VERSION 5.8 ;
BUSBITCHARS "[]" ;
DIVIDERCHAR "/" ;
UNITS
    DATABASE MICRONS 1000 ;
END UNITS

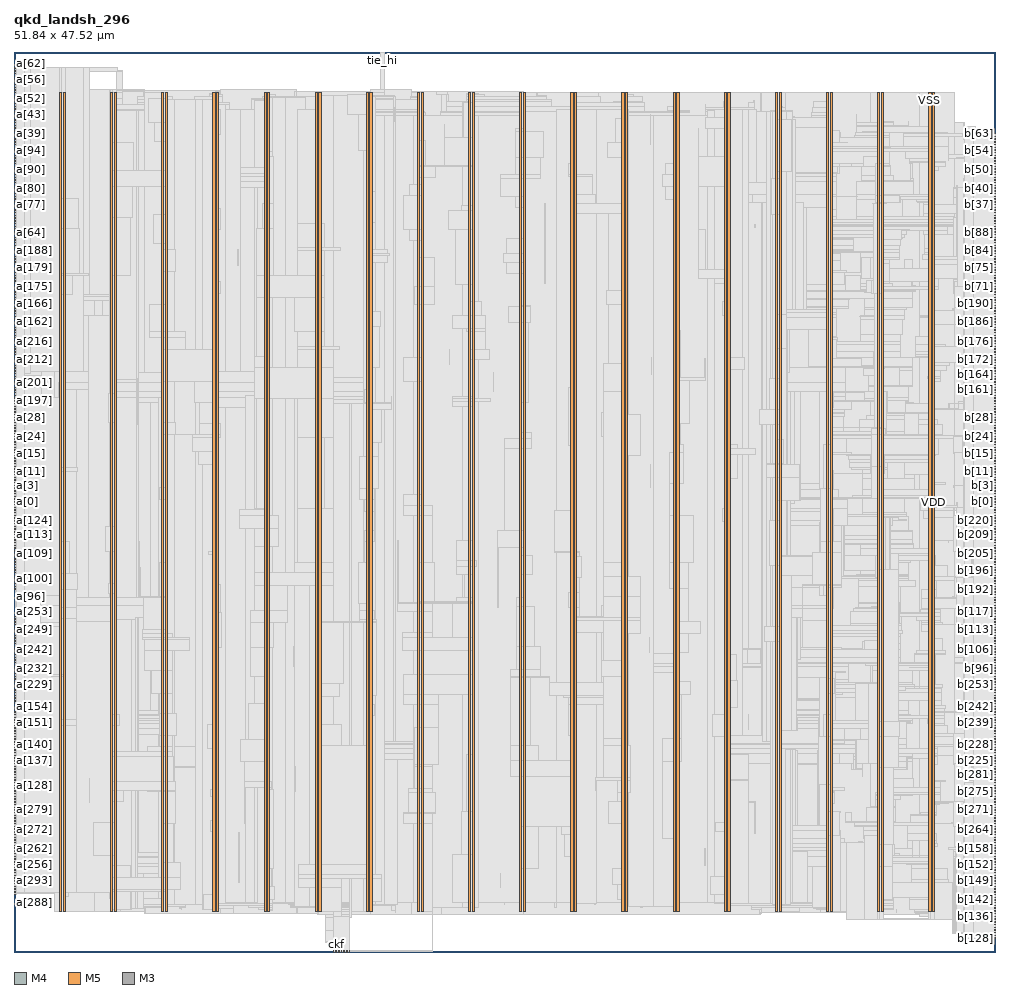
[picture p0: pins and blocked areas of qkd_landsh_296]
MACRO qkd_landsh_296
  FOREIGN qkd_landsh_296 0 0 ;
  CLASS BLOCK ;
  SIZE 51.84 BY 47.52 ;
  PIN a[0]
    DIRECTION INPUT ;
    USE SIGNAL ;
    PORT
      LAYER M4 ;
        RECT  0 23.76 0.084 23.784 ;
    END
  END a[0]
  PIN a[100]
    DIRECTION INPUT ;
    USE SIGNAL ;
    PORT
      LAYER M4 ;
        RECT  0 19.728 0.084 19.752 ;
    END
  END a[100]
  PIN a[101]
    DIRECTION INPUT ;
    USE SIGNAL ;
    PORT
      LAYER M4 ;
        RECT  0 19.872 0.084 19.896 ;
    END
  END a[101]
  PIN a[102]
    DIRECTION INPUT ;
    USE SIGNAL ;
    PORT
      LAYER M4 ;
        RECT  0 20.016 0.084 20.04 ;
    END
  END a[102]
  PIN a[103]
    DIRECTION INPUT ;
    USE SIGNAL ;
    PORT
      LAYER M4 ;
        RECT  0 20.16 0.084 20.184 ;
    END
  END a[103]
  PIN a[104]
    DIRECTION INPUT ;
    USE SIGNAL ;
    PORT
      LAYER M4 ;
        RECT  0 20.304 0.084 20.328 ;
    END
  END a[104]
  PIN a[105]
    DIRECTION INPUT ;
    USE SIGNAL ;
    PORT
      LAYER M4 ;
        RECT  0 20.448 0.084 20.472 ;
    END
  END a[105]
  PIN a[106]
    DIRECTION INPUT ;
    USE SIGNAL ;
    PORT
      LAYER M4 ;
        RECT  0 20.592 0.084 20.616 ;
    END
  END a[106]
  PIN a[107]
    DIRECTION INPUT ;
    USE SIGNAL ;
    PORT
      LAYER M4 ;
        RECT  0 20.736 0.084 20.76 ;
    END
  END a[107]
  PIN a[108]
    DIRECTION INPUT ;
    USE SIGNAL ;
    PORT
      LAYER M4 ;
        RECT  0 20.88 0.084 20.904 ;
    END
  END a[108]
  PIN a[109]
    DIRECTION INPUT ;
    USE SIGNAL ;
    PORT
      LAYER M4 ;
        RECT  0 21.024 0.084 21.048 ;
    END
  END a[109]
  PIN a[10]
    DIRECTION INPUT ;
    USE SIGNAL ;
    PORT
      LAYER M4 ;
        RECT  0 25.2 0.084 25.224 ;
    END
  END a[10]
  PIN a[110]
    DIRECTION INPUT ;
    USE SIGNAL ;
    PORT
      LAYER M4 ;
        RECT  0 21.168 0.084 21.192 ;
    END
  END a[110]
  PIN a[111]
    DIRECTION INPUT ;
    USE SIGNAL ;
    PORT
      LAYER M4 ;
        RECT  0 21.312 0.084 21.336 ;
    END
  END a[111]
  PIN a[112]
    DIRECTION INPUT ;
    USE SIGNAL ;
    PORT
      LAYER M4 ;
        RECT  0 21.456 0.084 21.48 ;
    END
  END a[112]
  PIN a[113]
    DIRECTION INPUT ;
    USE SIGNAL ;
    PORT
      LAYER M4 ;
        RECT  0 21.6 0.084 21.624 ;
    END
  END a[113]
  PIN a[114]
    DIRECTION INPUT ;
    USE SIGNAL ;
    PORT
      LAYER M4 ;
        RECT  0 21.744 0.084 21.768 ;
    END
  END a[114]
  PIN a[115]
    DIRECTION INPUT ;
    USE SIGNAL ;
    PORT
      LAYER M4 ;
        RECT  0 21.888 0.084 21.912 ;
    END
  END a[115]
  PIN a[116]
    DIRECTION INPUT ;
    USE SIGNAL ;
    PORT
      LAYER M4 ;
        RECT  0 22.032 0.084 22.056 ;
    END
  END a[116]
  PIN a[117]
    DIRECTION INPUT ;
    USE SIGNAL ;
    PORT
      LAYER M4 ;
        RECT  0 22.176 0.084 22.2 ;
    END
  END a[117]
  PIN a[118]
    DIRECTION INPUT ;
    USE SIGNAL ;
    PORT
      LAYER M4 ;
        RECT  0 22.32 0.084 22.344 ;
    END
  END a[118]
  PIN a[119]
    DIRECTION INPUT ;
    USE SIGNAL ;
    PORT
      LAYER M4 ;
        RECT  0 22.464 0.084 22.488 ;
    END
  END a[119]
  PIN a[11]
    DIRECTION INPUT ;
    USE SIGNAL ;
    PORT
      LAYER M4 ;
        RECT  0 25.344 0.084 25.368 ;
    END
  END a[11]
  PIN a[120]
    DIRECTION INPUT ;
    USE SIGNAL ;
    PORT
      LAYER M4 ;
        RECT  0 22.608 0.084 22.632 ;
    END
  END a[120]
  PIN a[121]
    DIRECTION INPUT ;
    USE SIGNAL ;
    PORT
      LAYER M4 ;
        RECT  0 22.752 0.084 22.776 ;
    END
  END a[121]
  PIN a[122]
    DIRECTION INPUT ;
    USE SIGNAL ;
    PORT
      LAYER M4 ;
        RECT  0 22.896 0.084 22.92 ;
    END
  END a[122]
  PIN a[123]
    DIRECTION INPUT ;
    USE SIGNAL ;
    PORT
      LAYER M4 ;
        RECT  0 23.04 0.084 23.064 ;
    END
  END a[123]
  PIN a[124]
    DIRECTION INPUT ;
    USE SIGNAL ;
    PORT
      LAYER M4 ;
        RECT  0 23.184 0.084 23.208 ;
    END
  END a[124]
  PIN a[125]
    DIRECTION INPUT ;
    USE SIGNAL ;
    PORT
      LAYER M4 ;
        RECT  0 23.328 0.084 23.352 ;
    END
  END a[125]
  PIN a[126]
    DIRECTION INPUT ;
    USE SIGNAL ;
    PORT
      LAYER M4 ;
        RECT  0 23.472 0.084 23.496 ;
    END
  END a[126]
  PIN a[127]
    DIRECTION INPUT ;
    USE SIGNAL ;
    PORT
      LAYER M4 ;
        RECT  0 23.616 0.084 23.64 ;
    END
  END a[127]
  PIN a[128]
    DIRECTION INPUT ;
    USE SIGNAL ;
    PORT
      LAYER M4 ;
        RECT  0 8.784 0.084 8.808 ;
    END
  END a[128]
  PIN a[129]
    DIRECTION INPUT ;
    USE SIGNAL ;
    PORT
      LAYER M4 ;
        RECT  0 8.928 0.084 8.952 ;
    END
  END a[129]
  PIN a[12]
    DIRECTION INPUT ;
    USE SIGNAL ;
    PORT
      LAYER M4 ;
        RECT  0 25.488 0.084 25.512 ;
    END
  END a[12]
  PIN a[130]
    DIRECTION INPUT ;
    USE SIGNAL ;
    PORT
      LAYER M4 ;
        RECT  0 9.072 0.084 9.096 ;
    END
  END a[130]
  PIN a[131]
    DIRECTION INPUT ;
    USE SIGNAL ;
    PORT
      LAYER M4 ;
        RECT  0 9.216 0.084 9.24 ;
    END
  END a[131]
  PIN a[132]
    DIRECTION INPUT ;
    USE SIGNAL ;
    PORT
      LAYER M4 ;
        RECT  0 9.36 0.084 9.384 ;
    END
  END a[132]
  PIN a[133]
    DIRECTION INPUT ;
    USE SIGNAL ;
    PORT
      LAYER M4 ;
        RECT  0 9.504 0.084 9.528 ;
    END
  END a[133]
  PIN a[134]
    DIRECTION INPUT ;
    USE SIGNAL ;
    PORT
      LAYER M4 ;
        RECT  0 9.648 0.084 9.672 ;
    END
  END a[134]
  PIN a[135]
    DIRECTION INPUT ;
    USE SIGNAL ;
    PORT
      LAYER M4 ;
        RECT  0 9.792 0.084 9.816 ;
    END
  END a[135]
  PIN a[136]
    DIRECTION INPUT ;
    USE SIGNAL ;
    PORT
      LAYER M4 ;
        RECT  0 9.936 0.084 9.96 ;
    END
  END a[136]
  PIN a[137]
    DIRECTION INPUT ;
    USE SIGNAL ;
    PORT
      LAYER M4 ;
        RECT  0 10.08 0.084 10.104 ;
    END
  END a[137]
  PIN a[138]
    DIRECTION INPUT ;
    USE SIGNAL ;
    PORT
      LAYER M4 ;
        RECT  0 10.224 0.084 10.248 ;
    END
  END a[138]
  PIN a[139]
    DIRECTION INPUT ;
    USE SIGNAL ;
    PORT
      LAYER M4 ;
        RECT  0 10.368 0.084 10.392 ;
    END
  END a[139]
  PIN a[13]
    DIRECTION INPUT ;
    USE SIGNAL ;
    PORT
      LAYER M4 ;
        RECT  0 25.632 0.084 25.656 ;
    END
  END a[13]
  PIN a[140]
    DIRECTION INPUT ;
    USE SIGNAL ;
    PORT
      LAYER M4 ;
        RECT  0 10.512 0.084 10.536 ;
    END
  END a[140]
  PIN a[141]
    DIRECTION INPUT ;
    USE SIGNAL ;
    PORT
      LAYER M4 ;
        RECT  0 10.656 0.084 10.68 ;
    END
  END a[141]
  PIN a[142]
    DIRECTION INPUT ;
    USE SIGNAL ;
    PORT
      LAYER M4 ;
        RECT  0 10.8 0.084 10.824 ;
    END
  END a[142]
  PIN a[143]
    DIRECTION INPUT ;
    USE SIGNAL ;
    PORT
      LAYER M4 ;
        RECT  0 10.944 0.084 10.968 ;
    END
  END a[143]
  PIN a[144]
    DIRECTION INPUT ;
    USE SIGNAL ;
    PORT
      LAYER M4 ;
        RECT  0 11.088 0.084 11.112 ;
    END
  END a[144]
  PIN a[145]
    DIRECTION INPUT ;
    USE SIGNAL ;
    PORT
      LAYER M4 ;
        RECT  0 11.232 0.084 11.256 ;
    END
  END a[145]
  PIN a[146]
    DIRECTION INPUT ;
    USE SIGNAL ;
    PORT
      LAYER M4 ;
        RECT  0 11.376 0.084 11.4 ;
    END
  END a[146]
  PIN a[147]
    DIRECTION INPUT ;
    USE SIGNAL ;
    PORT
      LAYER M4 ;
        RECT  0 11.52 0.084 11.544 ;
    END
  END a[147]
  PIN a[148]
    DIRECTION INPUT ;
    USE SIGNAL ;
    PORT
      LAYER M4 ;
        RECT  0 11.664 0.084 11.688 ;
    END
  END a[148]
  PIN a[149]
    DIRECTION INPUT ;
    USE SIGNAL ;
    PORT
      LAYER M4 ;
        RECT  0 11.808 0.084 11.832 ;
    END
  END a[149]
  PIN a[14]
    DIRECTION INPUT ;
    USE SIGNAL ;
    PORT
      LAYER M4 ;
        RECT  0 25.776 0.084 25.8 ;
    END
  END a[14]
  PIN a[150]
    DIRECTION INPUT ;
    USE SIGNAL ;
    PORT
      LAYER M4 ;
        RECT  0 11.952 0.084 11.976 ;
    END
  END a[150]
  PIN a[151]
    DIRECTION INPUT ;
    USE SIGNAL ;
    PORT
      LAYER M4 ;
        RECT  0 12.096 0.084 12.12 ;
    END
  END a[151]
  PIN a[152]
    DIRECTION INPUT ;
    USE SIGNAL ;
    PORT
      LAYER M4 ;
        RECT  0 12.24 0.084 12.264 ;
    END
  END a[152]
  PIN a[153]
    DIRECTION INPUT ;
    USE SIGNAL ;
    PORT
      LAYER M4 ;
        RECT  0 12.384 0.084 12.408 ;
    END
  END a[153]
  PIN a[154]
    DIRECTION INPUT ;
    USE SIGNAL ;
    PORT
      LAYER M4 ;
        RECT  0 12.528 0.084 12.552 ;
    END
  END a[154]
  PIN a[155]
    DIRECTION INPUT ;
    USE SIGNAL ;
    PORT
      LAYER M4 ;
        RECT  0 12.672 0.084 12.696 ;
    END
  END a[155]
  PIN a[156]
    DIRECTION INPUT ;
    USE SIGNAL ;
    PORT
      LAYER M4 ;
        RECT  0 12.816 0.084 12.84 ;
    END
  END a[156]
  PIN a[157]
    DIRECTION INPUT ;
    USE SIGNAL ;
    PORT
      LAYER M4 ;
        RECT  0 12.96 0.084 12.984 ;
    END
  END a[157]
  PIN a[158]
    DIRECTION INPUT ;
    USE SIGNAL ;
    PORT
      LAYER M4 ;
        RECT  0 13.104 0.084 13.128 ;
    END
  END a[158]
  PIN a[159]
    DIRECTION INPUT ;
    USE SIGNAL ;
    PORT
      LAYER M4 ;
        RECT  0 13.248 0.084 13.272 ;
    END
  END a[159]
  PIN a[15]
    DIRECTION INPUT ;
    USE SIGNAL ;
    PORT
      LAYER M4 ;
        RECT  0 25.92 0.084 25.944 ;
    END
  END a[15]
  PIN a[160]
    DIRECTION INPUT ;
    USE SIGNAL ;
    PORT
      LAYER M4 ;
        RECT  0 32.976 0.084 33 ;
    END
  END a[160]
  PIN a[161]
    DIRECTION INPUT ;
    USE SIGNAL ;
    PORT
      LAYER M4 ;
        RECT  0 33.12 0.084 33.144 ;
    END
  END a[161]
  PIN a[162]
    DIRECTION INPUT ;
    USE SIGNAL ;
    PORT
      LAYER M4 ;
        RECT  0 33.264 0.084 33.288 ;
    END
  END a[162]
  PIN a[163]
    DIRECTION INPUT ;
    USE SIGNAL ;
    PORT
      LAYER M4 ;
        RECT  0 33.408 0.084 33.432 ;
    END
  END a[163]
  PIN a[164]
    DIRECTION INPUT ;
    USE SIGNAL ;
    PORT
      LAYER M4 ;
        RECT  0 33.552 0.084 33.576 ;
    END
  END a[164]
  PIN a[165]
    DIRECTION INPUT ;
    USE SIGNAL ;
    PORT
      LAYER M4 ;
        RECT  0 33.696 0.084 33.72 ;
    END
  END a[165]
  PIN a[166]
    DIRECTION INPUT ;
    USE SIGNAL ;
    PORT
      LAYER M4 ;
        RECT  0 33.84 0.084 33.864 ;
    END
  END a[166]
  PIN a[167]
    DIRECTION INPUT ;
    USE SIGNAL ;
    PORT
      LAYER M4 ;
        RECT  0 33.984 0.084 34.008 ;
    END
  END a[167]
  PIN a[168]
    DIRECTION INPUT ;
    USE SIGNAL ;
    PORT
      LAYER M4 ;
        RECT  0 34.128 0.084 34.152 ;
    END
  END a[168]
  PIN a[169]
    DIRECTION INPUT ;
    USE SIGNAL ;
    PORT
      LAYER M4 ;
        RECT  0 34.272 0.084 34.296 ;
    END
  END a[169]
  PIN a[16]
    DIRECTION INPUT ;
    USE SIGNAL ;
    PORT
      LAYER M4 ;
        RECT  0 26.064 0.084 26.088 ;
    END
  END a[16]
  PIN a[170]
    DIRECTION INPUT ;
    USE SIGNAL ;
    PORT
      LAYER M4 ;
        RECT  0 34.416 0.084 34.44 ;
    END
  END a[170]
  PIN a[171]
    DIRECTION INPUT ;
    USE SIGNAL ;
    PORT
      LAYER M4 ;
        RECT  0 34.56 0.084 34.584 ;
    END
  END a[171]
  PIN a[172]
    DIRECTION INPUT ;
    USE SIGNAL ;
    PORT
      LAYER M4 ;
        RECT  0 34.704 0.084 34.728 ;
    END
  END a[172]
  PIN a[173]
    DIRECTION INPUT ;
    USE SIGNAL ;
    PORT
      LAYER M4 ;
        RECT  0 34.848 0.084 34.872 ;
    END
  END a[173]
  PIN a[174]
    DIRECTION INPUT ;
    USE SIGNAL ;
    PORT
      LAYER M4 ;
        RECT  0 34.992 0.084 35.016 ;
    END
  END a[174]
  PIN a[175]
    DIRECTION INPUT ;
    USE SIGNAL ;
    PORT
      LAYER M4 ;
        RECT  0 35.136 0.084 35.16 ;
    END
  END a[175]
  PIN a[176]
    DIRECTION INPUT ;
    USE SIGNAL ;
    PORT
      LAYER M4 ;
        RECT  0 35.28 0.084 35.304 ;
    END
  END a[176]
  PIN a[177]
    DIRECTION INPUT ;
    USE SIGNAL ;
    PORT
      LAYER M4 ;
        RECT  0 35.424 0.084 35.448 ;
    END
  END a[177]
  PIN a[178]
    DIRECTION INPUT ;
    USE SIGNAL ;
    PORT
      LAYER M4 ;
        RECT  0 35.568 0.084 35.592 ;
    END
  END a[178]
  PIN a[179]
    DIRECTION INPUT ;
    USE SIGNAL ;
    PORT
      LAYER M4 ;
        RECT  0 35.712 0.084 35.736 ;
    END
  END a[179]
  PIN a[17]
    DIRECTION INPUT ;
    USE SIGNAL ;
    PORT
      LAYER M4 ;
        RECT  0 26.208 0.084 26.232 ;
    END
  END a[17]
  PIN a[180]
    DIRECTION INPUT ;
    USE SIGNAL ;
    PORT
      LAYER M4 ;
        RECT  0 35.856 0.084 35.88 ;
    END
  END a[180]
  PIN a[181]
    DIRECTION INPUT ;
    USE SIGNAL ;
    PORT
      LAYER M4 ;
        RECT  0 36 0.084 36.024 ;
    END
  END a[181]
  PIN a[182]
    DIRECTION INPUT ;
    USE SIGNAL ;
    PORT
      LAYER M4 ;
        RECT  0 36.144 0.084 36.168 ;
    END
  END a[182]
  PIN a[183]
    DIRECTION INPUT ;
    USE SIGNAL ;
    PORT
      LAYER M4 ;
        RECT  0 36.288 0.084 36.312 ;
    END
  END a[183]
  PIN a[184]
    DIRECTION INPUT ;
    USE SIGNAL ;
    PORT
      LAYER M4 ;
        RECT  0 36.432 0.084 36.456 ;
    END
  END a[184]
  PIN a[185]
    DIRECTION INPUT ;
    USE SIGNAL ;
    PORT
      LAYER M4 ;
        RECT  0 36.576 0.084 36.6 ;
    END
  END a[185]
  PIN a[186]
    DIRECTION INPUT ;
    USE SIGNAL ;
    PORT
      LAYER M4 ;
        RECT  0 36.72 0.084 36.744 ;
    END
  END a[186]
  PIN a[187]
    DIRECTION INPUT ;
    USE SIGNAL ;
    PORT
      LAYER M4 ;
        RECT  0 36.864 0.084 36.888 ;
    END
  END a[187]
  PIN a[188]
    DIRECTION INPUT ;
    USE SIGNAL ;
    PORT
      LAYER M4 ;
        RECT  0 37.008 0.084 37.032 ;
    END
  END a[188]
  PIN a[189]
    DIRECTION INPUT ;
    USE SIGNAL ;
    PORT
      LAYER M4 ;
        RECT  0 37.152 0.084 37.176 ;
    END
  END a[189]
  PIN a[18]
    DIRECTION INPUT ;
    USE SIGNAL ;
    PORT
      LAYER M4 ;
        RECT  0 26.352 0.084 26.376 ;
    END
  END a[18]
  PIN a[190]
    DIRECTION INPUT ;
    USE SIGNAL ;
    PORT
      LAYER M4 ;
        RECT  0 37.296 0.084 37.32 ;
    END
  END a[190]
  PIN a[191]
    DIRECTION INPUT ;
    USE SIGNAL ;
    PORT
      LAYER M4 ;
        RECT  0 37.44 0.084 37.464 ;
    END
  END a[191]
  PIN a[192]
    DIRECTION INPUT ;
    USE SIGNAL ;
    PORT
      LAYER M4 ;
        RECT  0 28.368 0.084 28.392 ;
    END
  END a[192]
  PIN a[193]
    DIRECTION INPUT ;
    USE SIGNAL ;
    PORT
      LAYER M4 ;
        RECT  0 28.512 0.084 28.536 ;
    END
  END a[193]
  PIN a[194]
    DIRECTION INPUT ;
    USE SIGNAL ;
    PORT
      LAYER M4 ;
        RECT  0 28.656 0.084 28.68 ;
    END
  END a[194]
  PIN a[195]
    DIRECTION INPUT ;
    USE SIGNAL ;
    PORT
      LAYER M4 ;
        RECT  0 28.8 0.084 28.824 ;
    END
  END a[195]
  PIN a[196]
    DIRECTION INPUT ;
    USE SIGNAL ;
    PORT
      LAYER M4 ;
        RECT  0 28.944 0.084 28.968 ;
    END
  END a[196]
  PIN a[197]
    DIRECTION INPUT ;
    USE SIGNAL ;
    PORT
      LAYER M4 ;
        RECT  0 29.088 0.084 29.112 ;
    END
  END a[197]
  PIN a[198]
    DIRECTION INPUT ;
    USE SIGNAL ;
    PORT
      LAYER M4 ;
        RECT  0 29.232 0.084 29.256 ;
    END
  END a[198]
  PIN a[199]
    DIRECTION INPUT ;
    USE SIGNAL ;
    PORT
      LAYER M4 ;
        RECT  0 29.376 0.084 29.4 ;
    END
  END a[199]
  PIN a[19]
    DIRECTION INPUT ;
    USE SIGNAL ;
    PORT
      LAYER M4 ;
        RECT  0 26.496 0.084 26.52 ;
    END
  END a[19]
  PIN a[1]
    DIRECTION INPUT ;
    USE SIGNAL ;
    PORT
      LAYER M4 ;
        RECT  0 23.904 0.084 23.928 ;
    END
  END a[1]
  PIN a[200]
    DIRECTION INPUT ;
    USE SIGNAL ;
    PORT
      LAYER M4 ;
        RECT  0 29.52 0.084 29.544 ;
    END
  END a[200]
  PIN a[201]
    DIRECTION INPUT ;
    USE SIGNAL ;
    PORT
      LAYER M4 ;
        RECT  0 29.664 0.084 29.688 ;
    END
  END a[201]
  PIN a[202]
    DIRECTION INPUT ;
    USE SIGNAL ;
    PORT
      LAYER M4 ;
        RECT  0 29.808 0.084 29.832 ;
    END
  END a[202]
  PIN a[203]
    DIRECTION INPUT ;
    USE SIGNAL ;
    PORT
      LAYER M4 ;
        RECT  0 29.952 0.084 29.976 ;
    END
  END a[203]
  PIN a[204]
    DIRECTION INPUT ;
    USE SIGNAL ;
    PORT
      LAYER M4 ;
        RECT  0 30.096 0.084 30.12 ;
    END
  END a[204]
  PIN a[205]
    DIRECTION INPUT ;
    USE SIGNAL ;
    PORT
      LAYER M4 ;
        RECT  0 30.24 0.084 30.264 ;
    END
  END a[205]
  PIN a[206]
    DIRECTION INPUT ;
    USE SIGNAL ;
    PORT
      LAYER M4 ;
        RECT  0 30.384 0.084 30.408 ;
    END
  END a[206]
  PIN a[207]
    DIRECTION INPUT ;
    USE SIGNAL ;
    PORT
      LAYER M4 ;
        RECT  0 30.528 0.084 30.552 ;
    END
  END a[207]
  PIN a[208]
    DIRECTION INPUT ;
    USE SIGNAL ;
    PORT
      LAYER M4 ;
        RECT  0 30.672 0.084 30.696 ;
    END
  END a[208]
  PIN a[209]
    DIRECTION INPUT ;
    USE SIGNAL ;
    PORT
      LAYER M4 ;
        RECT  0 30.816 0.084 30.84 ;
    END
  END a[209]
  PIN a[20]
    DIRECTION INPUT ;
    USE SIGNAL ;
    PORT
      LAYER M4 ;
        RECT  0 26.64 0.084 26.664 ;
    END
  END a[20]
  PIN a[210]
    DIRECTION INPUT ;
    USE SIGNAL ;
    PORT
      LAYER M4 ;
        RECT  0 30.96 0.084 30.984 ;
    END
  END a[210]
  PIN a[211]
    DIRECTION INPUT ;
    USE SIGNAL ;
    PORT
      LAYER M4 ;
        RECT  0 31.104 0.084 31.128 ;
    END
  END a[211]
  PIN a[212]
    DIRECTION INPUT ;
    USE SIGNAL ;
    PORT
      LAYER M4 ;
        RECT  0 31.248 0.084 31.272 ;
    END
  END a[212]
  PIN a[213]
    DIRECTION INPUT ;
    USE SIGNAL ;
    PORT
      LAYER M4 ;
        RECT  0 31.392 0.084 31.416 ;
    END
  END a[213]
  PIN a[214]
    DIRECTION INPUT ;
    USE SIGNAL ;
    PORT
      LAYER M4 ;
        RECT  0 31.536 0.084 31.56 ;
    END
  END a[214]
  PIN a[215]
    DIRECTION INPUT ;
    USE SIGNAL ;
    PORT
      LAYER M4 ;
        RECT  0 31.68 0.084 31.704 ;
    END
  END a[215]
  PIN a[216]
    DIRECTION INPUT ;
    USE SIGNAL ;
    PORT
      LAYER M4 ;
        RECT  0 31.824 0.084 31.848 ;
    END
  END a[216]
  PIN a[217]
    DIRECTION INPUT ;
    USE SIGNAL ;
    PORT
      LAYER M4 ;
        RECT  0 31.968 0.084 31.992 ;
    END
  END a[217]
  PIN a[218]
    DIRECTION INPUT ;
    USE SIGNAL ;
    PORT
      LAYER M4 ;
        RECT  0 32.112 0.084 32.136 ;
    END
  END a[218]
  PIN a[219]
    DIRECTION INPUT ;
    USE SIGNAL ;
    PORT
      LAYER M4 ;
        RECT  0 32.256 0.084 32.28 ;
    END
  END a[219]
  PIN a[21]
    DIRECTION INPUT ;
    USE SIGNAL ;
    PORT
      LAYER M4 ;
        RECT  0 26.784 0.084 26.808 ;
    END
  END a[21]
  PIN a[220]
    DIRECTION INPUT ;
    USE SIGNAL ;
    PORT
      LAYER M4 ;
        RECT  0 32.4 0.084 32.424 ;
    END
  END a[220]
  PIN a[221]
    DIRECTION INPUT ;
    USE SIGNAL ;
    PORT
      LAYER M4 ;
        RECT  0 32.544 0.084 32.568 ;
    END
  END a[221]
  PIN a[222]
    DIRECTION INPUT ;
    USE SIGNAL ;
    PORT
      LAYER M4 ;
        RECT  0 32.688 0.084 32.712 ;
    END
  END a[222]
  PIN a[223]
    DIRECTION INPUT ;
    USE SIGNAL ;
    PORT
      LAYER M4 ;
        RECT  0 32.832 0.084 32.856 ;
    END
  END a[223]
  PIN a[224]
    DIRECTION INPUT ;
    USE SIGNAL ;
    PORT
      LAYER M4 ;
        RECT  0 13.392 0.084 13.416 ;
    END
  END a[224]
  PIN a[225]
    DIRECTION INPUT ;
    USE SIGNAL ;
    PORT
      LAYER M4 ;
        RECT  0 13.536 0.084 13.56 ;
    END
  END a[225]
  PIN a[226]
    DIRECTION INPUT ;
    USE SIGNAL ;
    PORT
      LAYER M4 ;
        RECT  0 13.68 0.084 13.704 ;
    END
  END a[226]
  PIN a[227]
    DIRECTION INPUT ;
    USE SIGNAL ;
    PORT
      LAYER M4 ;
        RECT  0 13.824 0.084 13.848 ;
    END
  END a[227]
  PIN a[228]
    DIRECTION INPUT ;
    USE SIGNAL ;
    PORT
      LAYER M4 ;
        RECT  0 13.968 0.084 13.992 ;
    END
  END a[228]
  PIN a[229]
    DIRECTION INPUT ;
    USE SIGNAL ;
    PORT
      LAYER M4 ;
        RECT  0 14.112 0.084 14.136 ;
    END
  END a[229]
  PIN a[22]
    DIRECTION INPUT ;
    USE SIGNAL ;
    PORT
      LAYER M4 ;
        RECT  0 26.928 0.084 26.952 ;
    END
  END a[22]
  PIN a[230]
    DIRECTION INPUT ;
    USE SIGNAL ;
    PORT
      LAYER M4 ;
        RECT  0 14.256 0.084 14.28 ;
    END
  END a[230]
  PIN a[231]
    DIRECTION INPUT ;
    USE SIGNAL ;
    PORT
      LAYER M4 ;
        RECT  0 14.4 0.084 14.424 ;
    END
  END a[231]
  PIN a[232]
    DIRECTION INPUT ;
    USE SIGNAL ;
    PORT
      LAYER M4 ;
        RECT  0 14.544 0.084 14.568 ;
    END
  END a[232]
  PIN a[233]
    DIRECTION INPUT ;
    USE SIGNAL ;
    PORT
      LAYER M4 ;
        RECT  0 14.688 0.084 14.712 ;
    END
  END a[233]
  PIN a[234]
    DIRECTION INPUT ;
    USE SIGNAL ;
    PORT
      LAYER M4 ;
        RECT  0 14.832 0.084 14.856 ;
    END
  END a[234]
  PIN a[235]
    DIRECTION INPUT ;
    USE SIGNAL ;
    PORT
      LAYER M4 ;
        RECT  0 14.976 0.084 15 ;
    END
  END a[235]
  PIN a[236]
    DIRECTION INPUT ;
    USE SIGNAL ;
    PORT
      LAYER M4 ;
        RECT  0 15.12 0.084 15.144 ;
    END
  END a[236]
  PIN a[237]
    DIRECTION INPUT ;
    USE SIGNAL ;
    PORT
      LAYER M4 ;
        RECT  0 15.264 0.084 15.288 ;
    END
  END a[237]
  PIN a[238]
    DIRECTION INPUT ;
    USE SIGNAL ;
    PORT
      LAYER M4 ;
        RECT  0 15.408 0.084 15.432 ;
    END
  END a[238]
  PIN a[239]
    DIRECTION INPUT ;
    USE SIGNAL ;
    PORT
      LAYER M4 ;
        RECT  0 15.552 0.084 15.576 ;
    END
  END a[239]
  PIN a[23]
    DIRECTION INPUT ;
    USE SIGNAL ;
    PORT
      LAYER M4 ;
        RECT  0 27.072 0.084 27.096 ;
    END
  END a[23]
  PIN a[240]
    DIRECTION INPUT ;
    USE SIGNAL ;
    PORT
      LAYER M4 ;
        RECT  0 15.696 0.084 15.72 ;
    END
  END a[240]
  PIN a[241]
    DIRECTION INPUT ;
    USE SIGNAL ;
    PORT
      LAYER M4 ;
        RECT  0 15.84 0.084 15.864 ;
    END
  END a[241]
  PIN a[242]
    DIRECTION INPUT ;
    USE SIGNAL ;
    PORT
      LAYER M4 ;
        RECT  0 15.984 0.084 16.008 ;
    END
  END a[242]
  PIN a[243]
    DIRECTION INPUT ;
    USE SIGNAL ;
    PORT
      LAYER M4 ;
        RECT  0 16.128 0.084 16.152 ;
    END
  END a[243]
  PIN a[244]
    DIRECTION INPUT ;
    USE SIGNAL ;
    PORT
      LAYER M4 ;
        RECT  0 16.272 0.084 16.296 ;
    END
  END a[244]
  PIN a[245]
    DIRECTION INPUT ;
    USE SIGNAL ;
    PORT
      LAYER M4 ;
        RECT  0 16.416 0.084 16.44 ;
    END
  END a[245]
  PIN a[246]
    DIRECTION INPUT ;
    USE SIGNAL ;
    PORT
      LAYER M4 ;
        RECT  0 16.56 0.084 16.584 ;
    END
  END a[246]
  PIN a[247]
    DIRECTION INPUT ;
    USE SIGNAL ;
    PORT
      LAYER M4 ;
        RECT  0 16.704 0.084 16.728 ;
    END
  END a[247]
  PIN a[248]
    DIRECTION INPUT ;
    USE SIGNAL ;
    PORT
      LAYER M4 ;
        RECT  0 16.848 0.084 16.872 ;
    END
  END a[248]
  PIN a[249]
    DIRECTION INPUT ;
    USE SIGNAL ;
    PORT
      LAYER M4 ;
        RECT  0 16.992 0.084 17.016 ;
    END
  END a[249]
  PIN a[24]
    DIRECTION INPUT ;
    USE SIGNAL ;
    PORT
      LAYER M4 ;
        RECT  0 27.216 0.084 27.24 ;
    END
  END a[24]
  PIN a[250]
    DIRECTION INPUT ;
    USE SIGNAL ;
    PORT
      LAYER M4 ;
        RECT  0 17.136 0.084 17.16 ;
    END
  END a[250]
  PIN a[251]
    DIRECTION INPUT ;
    USE SIGNAL ;
    PORT
      LAYER M4 ;
        RECT  0 17.28 0.084 17.304 ;
    END
  END a[251]
  PIN a[252]
    DIRECTION INPUT ;
    USE SIGNAL ;
    PORT
      LAYER M4 ;
        RECT  0 17.424 0.084 17.448 ;
    END
  END a[252]
  PIN a[253]
    DIRECTION INPUT ;
    USE SIGNAL ;
    PORT
      LAYER M4 ;
        RECT  0 17.568 0.084 17.592 ;
    END
  END a[253]
  PIN a[254]
    DIRECTION INPUT ;
    USE SIGNAL ;
    PORT
      LAYER M4 ;
        RECT  0 17.712 0.084 17.736 ;
    END
  END a[254]
  PIN a[255]
    DIRECTION INPUT ;
    USE SIGNAL ;
    PORT
      LAYER M4 ;
        RECT  0 17.856 0.084 17.88 ;
    END
  END a[255]
  PIN a[256]
    DIRECTION INPUT ;
    USE SIGNAL ;
    PORT
      LAYER M4 ;
        RECT  0 4.176 0.084 4.2 ;
    END
  END a[256]
  PIN a[257]
    DIRECTION INPUT ;
    USE SIGNAL ;
    PORT
      LAYER M4 ;
        RECT  0 4.32 0.084 4.344 ;
    END
  END a[257]
  PIN a[258]
    DIRECTION INPUT ;
    USE SIGNAL ;
    PORT
      LAYER M4 ;
        RECT  0 4.464 0.084 4.488 ;
    END
  END a[258]
  PIN a[259]
    DIRECTION INPUT ;
    USE SIGNAL ;
    PORT
      LAYER M4 ;
        RECT  0 4.608 0.084 4.632 ;
    END
  END a[259]
  PIN a[25]
    DIRECTION INPUT ;
    USE SIGNAL ;
    PORT
      LAYER M4 ;
        RECT  0 27.36 0.084 27.384 ;
    END
  END a[25]
  PIN a[260]
    DIRECTION INPUT ;
    USE SIGNAL ;
    PORT
      LAYER M4 ;
        RECT  0 4.752 0.084 4.776 ;
    END
  END a[260]
  PIN a[261]
    DIRECTION INPUT ;
    USE SIGNAL ;
    PORT
      LAYER M4 ;
        RECT  0 4.896 0.084 4.92 ;
    END
  END a[261]
  PIN a[262]
    DIRECTION INPUT ;
    USE SIGNAL ;
    PORT
      LAYER M4 ;
        RECT  0 5.04 0.084 5.064 ;
    END
  END a[262]
  PIN a[263]
    DIRECTION INPUT ;
    USE SIGNAL ;
    PORT
      LAYER M4 ;
        RECT  0 5.184 0.084 5.208 ;
    END
  END a[263]
  PIN a[264]
    DIRECTION INPUT ;
    USE SIGNAL ;
    PORT
      LAYER M4 ;
        RECT  0 5.328 0.084 5.352 ;
    END
  END a[264]
  PIN a[265]
    DIRECTION INPUT ;
    USE SIGNAL ;
    PORT
      LAYER M4 ;
        RECT  0 5.472 0.084 5.496 ;
    END
  END a[265]
  PIN a[266]
    DIRECTION INPUT ;
    USE SIGNAL ;
    PORT
      LAYER M4 ;
        RECT  0 5.616 0.084 5.64 ;
    END
  END a[266]
  PIN a[267]
    DIRECTION INPUT ;
    USE SIGNAL ;
    PORT
      LAYER M4 ;
        RECT  0 5.76 0.084 5.784 ;
    END
  END a[267]
  PIN a[268]
    DIRECTION INPUT ;
    USE SIGNAL ;
    PORT
      LAYER M4 ;
        RECT  0 5.904 0.084 5.928 ;
    END
  END a[268]
  PIN a[269]
    DIRECTION INPUT ;
    USE SIGNAL ;
    PORT
      LAYER M4 ;
        RECT  0 6.048 0.084 6.072 ;
    END
  END a[269]
  PIN a[26]
    DIRECTION INPUT ;
    USE SIGNAL ;
    PORT
      LAYER M4 ;
        RECT  0 27.504 0.084 27.528 ;
    END
  END a[26]
  PIN a[270]
    DIRECTION INPUT ;
    USE SIGNAL ;
    PORT
      LAYER M4 ;
        RECT  0 6.192 0.084 6.216 ;
    END
  END a[270]
  PIN a[271]
    DIRECTION INPUT ;
    USE SIGNAL ;
    PORT
      LAYER M4 ;
        RECT  0 6.336 0.084 6.36 ;
    END
  END a[271]
  PIN a[272]
    DIRECTION INPUT ;
    USE SIGNAL ;
    PORT
      LAYER M4 ;
        RECT  0 6.48 0.084 6.504 ;
    END
  END a[272]
  PIN a[273]
    DIRECTION INPUT ;
    USE SIGNAL ;
    PORT
      LAYER M4 ;
        RECT  0 6.624 0.084 6.648 ;
    END
  END a[273]
  PIN a[274]
    DIRECTION INPUT ;
    USE SIGNAL ;
    PORT
      LAYER M4 ;
        RECT  0 6.768 0.084 6.792 ;
    END
  END a[274]
  PIN a[275]
    DIRECTION INPUT ;
    USE SIGNAL ;
    PORT
      LAYER M4 ;
        RECT  0 6.912 0.084 6.936 ;
    END
  END a[275]
  PIN a[276]
    DIRECTION INPUT ;
    USE SIGNAL ;
    PORT
      LAYER M4 ;
        RECT  0 7.056 0.084 7.08 ;
    END
  END a[276]
  PIN a[277]
    DIRECTION INPUT ;
    USE SIGNAL ;
    PORT
      LAYER M4 ;
        RECT  0 7.2 0.084 7.224 ;
    END
  END a[277]
  PIN a[278]
    DIRECTION INPUT ;
    USE SIGNAL ;
    PORT
      LAYER M4 ;
        RECT  0 7.344 0.084 7.368 ;
    END
  END a[278]
  PIN a[279]
    DIRECTION INPUT ;
    USE SIGNAL ;
    PORT
      LAYER M4 ;
        RECT  0 7.488 0.084 7.512 ;
    END
  END a[279]
  PIN a[27]
    DIRECTION INPUT ;
    USE SIGNAL ;
    PORT
      LAYER M4 ;
        RECT  0 27.648 0.084 27.672 ;
    END
  END a[27]
  PIN a[280]
    DIRECTION INPUT ;
    USE SIGNAL ;
    PORT
      LAYER M4 ;
        RECT  0 7.632 0.084 7.656 ;
    END
  END a[280]
  PIN a[281]
    DIRECTION INPUT ;
    USE SIGNAL ;
    PORT
      LAYER M4 ;
        RECT  0 7.776 0.084 7.8 ;
    END
  END a[281]
  PIN a[282]
    DIRECTION INPUT ;
    USE SIGNAL ;
    PORT
      LAYER M4 ;
        RECT  0 7.92 0.084 7.944 ;
    END
  END a[282]
  PIN a[283]
    DIRECTION INPUT ;
    USE SIGNAL ;
    PORT
      LAYER M4 ;
        RECT  0 8.064 0.084 8.088 ;
    END
  END a[283]
  PIN a[284]
    DIRECTION INPUT ;
    USE SIGNAL ;
    PORT
      LAYER M4 ;
        RECT  0 8.208 0.084 8.232 ;
    END
  END a[284]
  PIN a[285]
    DIRECTION INPUT ;
    USE SIGNAL ;
    PORT
      LAYER M4 ;
        RECT  0 8.352 0.084 8.376 ;
    END
  END a[285]
  PIN a[286]
    DIRECTION INPUT ;
    USE SIGNAL ;
    PORT
      LAYER M4 ;
        RECT  0 8.496 0.084 8.52 ;
    END
  END a[286]
  PIN a[287]
    DIRECTION INPUT ;
    USE SIGNAL ;
    PORT
      LAYER M4 ;
        RECT  0 8.64 0.084 8.664 ;
    END
  END a[287]
  PIN a[288]
    DIRECTION INPUT ;
    USE SIGNAL ;
    PORT
      LAYER M4 ;
        RECT  0 3.024 0.084 3.048 ;
    END
  END a[288]
  PIN a[289]
    DIRECTION INPUT ;
    USE SIGNAL ;
    PORT
      LAYER M4 ;
        RECT  0 3.168 0.084 3.192 ;
    END
  END a[289]
  PIN a[28]
    DIRECTION INPUT ;
    USE SIGNAL ;
    PORT
      LAYER M4 ;
        RECT  0 27.792 0.084 27.816 ;
    END
  END a[28]
  PIN a[290]
    DIRECTION INPUT ;
    USE SIGNAL ;
    PORT
      LAYER M4 ;
        RECT  0 3.312 0.084 3.336 ;
    END
  END a[290]
  PIN a[291]
    DIRECTION INPUT ;
    USE SIGNAL ;
    PORT
      LAYER M4 ;
        RECT  0 3.456 0.084 3.48 ;
    END
  END a[291]
  PIN a[292]
    DIRECTION INPUT ;
    USE SIGNAL ;
    PORT
      LAYER M4 ;
        RECT  0 3.6 0.084 3.624 ;
    END
  END a[292]
  PIN a[293]
    DIRECTION INPUT ;
    USE SIGNAL ;
    PORT
      LAYER M4 ;
        RECT  0 3.744 0.084 3.768 ;
    END
  END a[293]
  PIN a[294]
    DIRECTION INPUT ;
    USE SIGNAL ;
    PORT
      LAYER M4 ;
        RECT  0 3.888 0.084 3.912 ;
    END
  END a[294]
  PIN a[295]
    DIRECTION INPUT ;
    USE SIGNAL ;
    PORT
      LAYER M4 ;
        RECT  0 4.032 0.084 4.056 ;
    END
  END a[295]
  PIN a[29]
    DIRECTION INPUT ;
    USE SIGNAL ;
    PORT
      LAYER M4 ;
        RECT  0 27.936 0.084 27.96 ;
    END
  END a[29]
  PIN a[2]
    DIRECTION INPUT ;
    USE SIGNAL ;
    PORT
      LAYER M4 ;
        RECT  0 24.048 0.084 24.072 ;
    END
  END a[2]
  PIN a[30]
    DIRECTION INPUT ;
    USE SIGNAL ;
    PORT
      LAYER M4 ;
        RECT  0 28.08 0.084 28.104 ;
    END
  END a[30]
  PIN a[31]
    DIRECTION INPUT ;
    USE SIGNAL ;
    PORT
      LAYER M4 ;
        RECT  0 28.224 0.084 28.248 ;
    END
  END a[31]
  PIN a[32]
    DIRECTION INPUT ;
    USE SIGNAL ;
    PORT
      LAYER M4 ;
        RECT  0 42.192 0.084 42.216 ;
    END
  END a[32]
  PIN a[33]
    DIRECTION INPUT ;
    USE SIGNAL ;
    PORT
      LAYER M4 ;
        RECT  0 42.336 0.084 42.36 ;
    END
  END a[33]
  PIN a[34]
    DIRECTION INPUT ;
    USE SIGNAL ;
    PORT
      LAYER M4 ;
        RECT  0 42.48 0.084 42.504 ;
    END
  END a[34]
  PIN a[35]
    DIRECTION INPUT ;
    USE SIGNAL ;
    PORT
      LAYER M4 ;
        RECT  0 42.624 0.084 42.648 ;
    END
  END a[35]
  PIN a[36]
    DIRECTION INPUT ;
    USE SIGNAL ;
    PORT
      LAYER M4 ;
        RECT  0 42.768 0.084 42.792 ;
    END
  END a[36]
  PIN a[37]
    DIRECTION INPUT ;
    USE SIGNAL ;
    PORT
      LAYER M4 ;
        RECT  0 42.912 0.084 42.936 ;
    END
  END a[37]
  PIN a[38]
    DIRECTION INPUT ;
    USE SIGNAL ;
    PORT
      LAYER M4 ;
        RECT  0 43.056 0.084 43.08 ;
    END
  END a[38]
  PIN a[39]
    DIRECTION INPUT ;
    USE SIGNAL ;
    PORT
      LAYER M4 ;
        RECT  0 43.2 0.084 43.224 ;
    END
  END a[39]
  PIN a[3]
    DIRECTION INPUT ;
    USE SIGNAL ;
    PORT
      LAYER M4 ;
        RECT  0 24.192 0.084 24.216 ;
    END
  END a[3]
  PIN a[40]
    DIRECTION INPUT ;
    USE SIGNAL ;
    PORT
      LAYER M4 ;
        RECT  0 43.344 0.084 43.368 ;
    END
  END a[40]
  PIN a[41]
    DIRECTION INPUT ;
    USE SIGNAL ;
    PORT
      LAYER M4 ;
        RECT  0 43.488 0.084 43.512 ;
    END
  END a[41]
  PIN a[42]
    DIRECTION INPUT ;
    USE SIGNAL ;
    PORT
      LAYER M4 ;
        RECT  0 43.632 0.084 43.656 ;
    END
  END a[42]
  PIN a[43]
    DIRECTION INPUT ;
    USE SIGNAL ;
    PORT
      LAYER M4 ;
        RECT  0 43.776 0.084 43.8 ;
    END
  END a[43]
  PIN a[44]
    DIRECTION INPUT ;
    USE SIGNAL ;
    PORT
      LAYER M4 ;
        RECT  0 43.92 0.084 43.944 ;
    END
  END a[44]
  PIN a[45]
    DIRECTION INPUT ;
    USE SIGNAL ;
    PORT
      LAYER M4 ;
        RECT  0 44.064 0.084 44.088 ;
    END
  END a[45]
  PIN a[46]
    DIRECTION INPUT ;
    USE SIGNAL ;
    PORT
      LAYER M4 ;
        RECT  0 44.208 0.084 44.232 ;
    END
  END a[46]
  PIN a[47]
    DIRECTION INPUT ;
    USE SIGNAL ;
    PORT
      LAYER M4 ;
        RECT  0 44.352 0.084 44.376 ;
    END
  END a[47]
  PIN a[48]
    DIRECTION INPUT ;
    USE SIGNAL ;
    PORT
      LAYER M4 ;
        RECT  0 44.496 0.084 44.52 ;
    END
  END a[48]
  PIN a[49]
    DIRECTION INPUT ;
    USE SIGNAL ;
    PORT
      LAYER M4 ;
        RECT  0 44.64 0.084 44.664 ;
    END
  END a[49]
  PIN a[4]
    DIRECTION INPUT ;
    USE SIGNAL ;
    PORT
      LAYER M4 ;
        RECT  0 24.336 0.084 24.36 ;
    END
  END a[4]
  PIN a[50]
    DIRECTION INPUT ;
    USE SIGNAL ;
    PORT
      LAYER M4 ;
        RECT  0 44.784 0.084 44.808 ;
    END
  END a[50]
  PIN a[51]
    DIRECTION INPUT ;
    USE SIGNAL ;
    PORT
      LAYER M4 ;
        RECT  0 44.928 0.084 44.952 ;
    END
  END a[51]
  PIN a[52]
    DIRECTION INPUT ;
    USE SIGNAL ;
    PORT
      LAYER M4 ;
        RECT  0 45.072 0.084 45.096 ;
    END
  END a[52]
  PIN a[53]
    DIRECTION INPUT ;
    USE SIGNAL ;
    PORT
      LAYER M4 ;
        RECT  0 45.216 0.084 45.24 ;
    END
  END a[53]
  PIN a[54]
    DIRECTION INPUT ;
    USE SIGNAL ;
    PORT
      LAYER M4 ;
        RECT  0 45.36 0.084 45.384 ;
    END
  END a[54]
  PIN a[55]
    DIRECTION INPUT ;
    USE SIGNAL ;
    PORT
      LAYER M4 ;
        RECT  0 45.504 0.084 45.528 ;
    END
  END a[55]
  PIN a[56]
    DIRECTION INPUT ;
    USE SIGNAL ;
    PORT
      LAYER M4 ;
        RECT  0 45.648 0.084 45.672 ;
    END
  END a[56]
  PIN a[57]
    DIRECTION INPUT ;
    USE SIGNAL ;
    PORT
      LAYER M4 ;
        RECT  0 45.792 0.084 45.816 ;
    END
  END a[57]
  PIN a[58]
    DIRECTION INPUT ;
    USE SIGNAL ;
    PORT
      LAYER M4 ;
        RECT  0 45.936 0.084 45.96 ;
    END
  END a[58]
  PIN a[59]
    DIRECTION INPUT ;
    USE SIGNAL ;
    PORT
      LAYER M4 ;
        RECT  0 46.08 0.084 46.104 ;
    END
  END a[59]
  PIN a[5]
    DIRECTION INPUT ;
    USE SIGNAL ;
    PORT
      LAYER M4 ;
        RECT  0 24.48 0.084 24.504 ;
    END
  END a[5]
  PIN a[60]
    DIRECTION INPUT ;
    USE SIGNAL ;
    PORT
      LAYER M4 ;
        RECT  0 46.224 0.084 46.248 ;
    END
  END a[60]
  PIN a[61]
    DIRECTION INPUT ;
    USE SIGNAL ;
    PORT
      LAYER M4 ;
        RECT  0 46.368 0.084 46.392 ;
    END
  END a[61]
  PIN a[62]
    DIRECTION INPUT ;
    USE SIGNAL ;
    PORT
      LAYER M4 ;
        RECT  0 46.512 0.084 46.536 ;
    END
  END a[62]
  PIN a[63]
    DIRECTION INPUT ;
    USE SIGNAL ;
    PORT
      LAYER M4 ;
        RECT  0 46.656 0.084 46.68 ;
    END
  END a[63]
  PIN a[64]
    DIRECTION INPUT ;
    USE SIGNAL ;
    PORT
      LAYER M4 ;
        RECT  0 37.584 0.084 37.608 ;
    END
  END a[64]
  PIN a[65]
    DIRECTION INPUT ;
    USE SIGNAL ;
    PORT
      LAYER M4 ;
        RECT  0 37.728 0.084 37.752 ;
    END
  END a[65]
  PIN a[66]
    DIRECTION INPUT ;
    USE SIGNAL ;
    PORT
      LAYER M4 ;
        RECT  0 37.872 0.084 37.896 ;
    END
  END a[66]
  PIN a[67]
    DIRECTION INPUT ;
    USE SIGNAL ;
    PORT
      LAYER M4 ;
        RECT  0 38.016 0.084 38.04 ;
    END
  END a[67]
  PIN a[68]
    DIRECTION INPUT ;
    USE SIGNAL ;
    PORT
      LAYER M4 ;
        RECT  0 38.16 0.084 38.184 ;
    END
  END a[68]
  PIN a[69]
    DIRECTION INPUT ;
    USE SIGNAL ;
    PORT
      LAYER M4 ;
        RECT  0 38.304 0.084 38.328 ;
    END
  END a[69]
  PIN a[6]
    DIRECTION INPUT ;
    USE SIGNAL ;
    PORT
      LAYER M4 ;
        RECT  0 24.624 0.084 24.648 ;
    END
  END a[6]
  PIN a[70]
    DIRECTION INPUT ;
    USE SIGNAL ;
    PORT
      LAYER M4 ;
        RECT  0 38.448 0.084 38.472 ;
    END
  END a[70]
  PIN a[71]
    DIRECTION INPUT ;
    USE SIGNAL ;
    PORT
      LAYER M4 ;
        RECT  0 38.592 0.084 38.616 ;
    END
  END a[71]
  PIN a[72]
    DIRECTION INPUT ;
    USE SIGNAL ;
    PORT
      LAYER M4 ;
        RECT  0 38.736 0.084 38.76 ;
    END
  END a[72]
  PIN a[73]
    DIRECTION INPUT ;
    USE SIGNAL ;
    PORT
      LAYER M4 ;
        RECT  0 38.88 0.084 38.904 ;
    END
  END a[73]
  PIN a[74]
    DIRECTION INPUT ;
    USE SIGNAL ;
    PORT
      LAYER M4 ;
        RECT  0 39.024 0.084 39.048 ;
    END
  END a[74]
  PIN a[75]
    DIRECTION INPUT ;
    USE SIGNAL ;
    PORT
      LAYER M4 ;
        RECT  0 39.168 0.084 39.192 ;
    END
  END a[75]
  PIN a[76]
    DIRECTION INPUT ;
    USE SIGNAL ;
    PORT
      LAYER M4 ;
        RECT  0 39.312 0.084 39.336 ;
    END
  END a[76]
  PIN a[77]
    DIRECTION INPUT ;
    USE SIGNAL ;
    PORT
      LAYER M4 ;
        RECT  0 39.456 0.084 39.48 ;
    END
  END a[77]
  PIN a[78]
    DIRECTION INPUT ;
    USE SIGNAL ;
    PORT
      LAYER M4 ;
        RECT  0 39.6 0.084 39.624 ;
    END
  END a[78]
  PIN a[79]
    DIRECTION INPUT ;
    USE SIGNAL ;
    PORT
      LAYER M4 ;
        RECT  0 39.744 0.084 39.768 ;
    END
  END a[79]
  PIN a[7]
    DIRECTION INPUT ;
    USE SIGNAL ;
    PORT
      LAYER M4 ;
        RECT  0 24.768 0.084 24.792 ;
    END
  END a[7]
  PIN a[80]
    DIRECTION INPUT ;
    USE SIGNAL ;
    PORT
      LAYER M4 ;
        RECT  0 39.888 0.084 39.912 ;
    END
  END a[80]
  PIN a[81]
    DIRECTION INPUT ;
    USE SIGNAL ;
    PORT
      LAYER M4 ;
        RECT  0 40.032 0.084 40.056 ;
    END
  END a[81]
  PIN a[82]
    DIRECTION INPUT ;
    USE SIGNAL ;
    PORT
      LAYER M4 ;
        RECT  0 40.176 0.084 40.2 ;
    END
  END a[82]
  PIN a[83]
    DIRECTION INPUT ;
    USE SIGNAL ;
    PORT
      LAYER M4 ;
        RECT  0 40.32 0.084 40.344 ;
    END
  END a[83]
  PIN a[84]
    DIRECTION INPUT ;
    USE SIGNAL ;
    PORT
      LAYER M4 ;
        RECT  0 40.464 0.084 40.488 ;
    END
  END a[84]
  PIN a[85]
    DIRECTION INPUT ;
    USE SIGNAL ;
    PORT
      LAYER M4 ;
        RECT  0 40.608 0.084 40.632 ;
    END
  END a[85]
  PIN a[86]
    DIRECTION INPUT ;
    USE SIGNAL ;
    PORT
      LAYER M4 ;
        RECT  0 40.752 0.084 40.776 ;
    END
  END a[86]
  PIN a[87]
    DIRECTION INPUT ;
    USE SIGNAL ;
    PORT
      LAYER M4 ;
        RECT  0 40.896 0.084 40.92 ;
    END
  END a[87]
  PIN a[88]
    DIRECTION INPUT ;
    USE SIGNAL ;
    PORT
      LAYER M4 ;
        RECT  0 41.04 0.084 41.064 ;
    END
  END a[88]
  PIN a[89]
    DIRECTION INPUT ;
    USE SIGNAL ;
    PORT
      LAYER M4 ;
        RECT  0 41.184 0.084 41.208 ;
    END
  END a[89]
  PIN a[8]
    DIRECTION INPUT ;
    USE SIGNAL ;
    PORT
      LAYER M4 ;
        RECT  0 24.912 0.084 24.936 ;
    END
  END a[8]
  PIN a[90]
    DIRECTION INPUT ;
    USE SIGNAL ;
    PORT
      LAYER M4 ;
        RECT  0 41.328 0.084 41.352 ;
    END
  END a[90]
  PIN a[91]
    DIRECTION INPUT ;
    USE SIGNAL ;
    PORT
      LAYER M4 ;
        RECT  0 41.472 0.084 41.496 ;
    END
  END a[91]
  PIN a[92]
    DIRECTION INPUT ;
    USE SIGNAL ;
    PORT
      LAYER M4 ;
        RECT  0 41.616 0.084 41.64 ;
    END
  END a[92]
  PIN a[93]
    DIRECTION INPUT ;
    USE SIGNAL ;
    PORT
      LAYER M4 ;
        RECT  0 41.76 0.084 41.784 ;
    END
  END a[93]
  PIN a[94]
    DIRECTION INPUT ;
    USE SIGNAL ;
    PORT
      LAYER M4 ;
        RECT  0 41.904 0.084 41.928 ;
    END
  END a[94]
  PIN a[95]
    DIRECTION INPUT ;
    USE SIGNAL ;
    PORT
      LAYER M4 ;
        RECT  0 42.048 0.084 42.072 ;
    END
  END a[95]
  PIN a[96]
    DIRECTION INPUT ;
    USE SIGNAL ;
    PORT
      LAYER M4 ;
        RECT  0 19.152 0.084 19.176 ;
    END
  END a[96]
  PIN a[97]
    DIRECTION INPUT ;
    USE SIGNAL ;
    PORT
      LAYER M4 ;
        RECT  0 19.296 0.084 19.32 ;
    END
  END a[97]
  PIN a[98]
    DIRECTION INPUT ;
    USE SIGNAL ;
    PORT
      LAYER M4 ;
        RECT  0 19.44 0.084 19.464 ;
    END
  END a[98]
  PIN a[99]
    DIRECTION INPUT ;
    USE SIGNAL ;
    PORT
      LAYER M4 ;
        RECT  0 19.584 0.084 19.608 ;
    END
  END a[99]
  PIN a[9]
    DIRECTION INPUT ;
    USE SIGNAL ;
    PORT
      LAYER M4 ;
        RECT  0 25.056 0.084 25.08 ;
    END
  END a[9]
  PIN b[0]
    DIRECTION OUTPUT ;
    USE SIGNAL ;
    PORT
      LAYER M4 ;
        RECT  51.756 23.76 51.84 23.784 ;
    END
  END b[0]
  PIN b[100]
    DIRECTION OUTPUT ;
    USE SIGNAL ;
    PORT
      LAYER M4 ;
        RECT  51.756 15.12 51.84 15.144 ;
    END
  END b[100]
  PIN b[101]
    DIRECTION OUTPUT ;
    USE SIGNAL ;
    PORT
      LAYER M4 ;
        RECT  51.756 15.264 51.84 15.288 ;
    END
  END b[101]
  PIN b[102]
    DIRECTION OUTPUT ;
    USE SIGNAL ;
    PORT
      LAYER M4 ;
        RECT  51.756 15.408 51.84 15.432 ;
    END
  END b[102]
  PIN b[103]
    DIRECTION OUTPUT ;
    USE SIGNAL ;
    PORT
      LAYER M4 ;
        RECT  51.756 15.552 51.84 15.576 ;
    END
  END b[103]
  PIN b[104]
    DIRECTION OUTPUT ;
    USE SIGNAL ;
    PORT
      LAYER M4 ;
        RECT  51.756 15.696 51.84 15.72 ;
    END
  END b[104]
  PIN b[105]
    DIRECTION OUTPUT ;
    USE SIGNAL ;
    PORT
      LAYER M4 ;
        RECT  51.756 15.84 51.84 15.864 ;
    END
  END b[105]
  PIN b[106]
    DIRECTION OUTPUT ;
    USE SIGNAL ;
    PORT
      LAYER M4 ;
        RECT  51.756 15.984 51.84 16.008 ;
    END
  END b[106]
  PIN b[107]
    DIRECTION OUTPUT ;
    USE SIGNAL ;
    PORT
      LAYER M4 ;
        RECT  51.756 16.128 51.84 16.152 ;
    END
  END b[107]
  PIN b[108]
    DIRECTION OUTPUT ;
    USE SIGNAL ;
    PORT
      LAYER M4 ;
        RECT  51.756 16.272 51.84 16.296 ;
    END
  END b[108]
  PIN b[109]
    DIRECTION OUTPUT ;
    USE SIGNAL ;
    PORT
      LAYER M4 ;
        RECT  51.756 16.416 51.84 16.44 ;
    END
  END b[109]
  PIN b[10]
    DIRECTION OUTPUT ;
    USE SIGNAL ;
    PORT
      LAYER M4 ;
        RECT  51.756 25.2 51.84 25.224 ;
    END
  END b[10]
  PIN b[110]
    DIRECTION OUTPUT ;
    USE SIGNAL ;
    PORT
      LAYER M4 ;
        RECT  51.756 16.56 51.84 16.584 ;
    END
  END b[110]
  PIN b[111]
    DIRECTION OUTPUT ;
    USE SIGNAL ;
    PORT
      LAYER M4 ;
        RECT  51.756 16.704 51.84 16.728 ;
    END
  END b[111]
  PIN b[112]
    DIRECTION OUTPUT ;
    USE SIGNAL ;
    PORT
      LAYER M4 ;
        RECT  51.756 16.848 51.84 16.872 ;
    END
  END b[112]
  PIN b[113]
    DIRECTION OUTPUT ;
    USE SIGNAL ;
    PORT
      LAYER M4 ;
        RECT  51.756 16.992 51.84 17.016 ;
    END
  END b[113]
  PIN b[114]
    DIRECTION OUTPUT ;
    USE SIGNAL ;
    PORT
      LAYER M4 ;
        RECT  51.756 17.136 51.84 17.16 ;
    END
  END b[114]
  PIN b[115]
    DIRECTION OUTPUT ;
    USE SIGNAL ;
    PORT
      LAYER M4 ;
        RECT  51.756 17.28 51.84 17.304 ;
    END
  END b[115]
  PIN b[116]
    DIRECTION OUTPUT ;
    USE SIGNAL ;
    PORT
      LAYER M4 ;
        RECT  51.756 17.424 51.84 17.448 ;
    END
  END b[116]
  PIN b[117]
    DIRECTION OUTPUT ;
    USE SIGNAL ;
    PORT
      LAYER M4 ;
        RECT  51.756 17.568 51.84 17.592 ;
    END
  END b[117]
  PIN b[118]
    DIRECTION OUTPUT ;
    USE SIGNAL ;
    PORT
      LAYER M4 ;
        RECT  51.756 17.712 51.84 17.736 ;
    END
  END b[118]
  PIN b[119]
    DIRECTION OUTPUT ;
    USE SIGNAL ;
    PORT
      LAYER M4 ;
        RECT  51.756 17.856 51.84 17.88 ;
    END
  END b[119]
  PIN b[11]
    DIRECTION OUTPUT ;
    USE SIGNAL ;
    PORT
      LAYER M4 ;
        RECT  51.756 25.344 51.84 25.368 ;
    END
  END b[11]
  PIN b[120]
    DIRECTION OUTPUT ;
    USE SIGNAL ;
    PORT
      LAYER M4 ;
        RECT  51.756 18 51.84 18.024 ;
    END
  END b[120]
  PIN b[121]
    DIRECTION OUTPUT ;
    USE SIGNAL ;
    PORT
      LAYER M4 ;
        RECT  51.756 18.144 51.84 18.168 ;
    END
  END b[121]
  PIN b[122]
    DIRECTION OUTPUT ;
    USE SIGNAL ;
    PORT
      LAYER M4 ;
        RECT  51.756 18.288 51.84 18.312 ;
    END
  END b[122]
  PIN b[123]
    DIRECTION OUTPUT ;
    USE SIGNAL ;
    PORT
      LAYER M4 ;
        RECT  51.756 18.432 51.84 18.456 ;
    END
  END b[123]
  PIN b[124]
    DIRECTION OUTPUT ;
    USE SIGNAL ;
    PORT
      LAYER M4 ;
        RECT  51.756 18.576 51.84 18.6 ;
    END
  END b[124]
  PIN b[125]
    DIRECTION OUTPUT ;
    USE SIGNAL ;
    PORT
      LAYER M4 ;
        RECT  51.756 18.72 51.84 18.744 ;
    END
  END b[125]
  PIN b[126]
    DIRECTION OUTPUT ;
    USE SIGNAL ;
    PORT
      LAYER M4 ;
        RECT  51.756 18.864 51.84 18.888 ;
    END
  END b[126]
  PIN b[127]
    DIRECTION OUTPUT ;
    USE SIGNAL ;
    PORT
      LAYER M4 ;
        RECT  51.756 19.008 51.84 19.032 ;
    END
  END b[127]
  PIN b[128]
    DIRECTION OUTPUT ;
    USE SIGNAL ;
    PORT
      LAYER M4 ;
        RECT  51.756 0.72 51.84 0.744 ;
    END
  END b[128]
  PIN b[129]
    DIRECTION OUTPUT ;
    USE SIGNAL ;
    PORT
      LAYER M4 ;
        RECT  51.756 0.864 51.84 0.888 ;
    END
  END b[129]
  PIN b[12]
    DIRECTION OUTPUT ;
    USE SIGNAL ;
    PORT
      LAYER M4 ;
        RECT  51.756 25.488 51.84 25.512 ;
    END
  END b[12]
  PIN b[130]
    DIRECTION OUTPUT ;
    USE SIGNAL ;
    PORT
      LAYER M4 ;
        RECT  51.756 1.008 51.84 1.032 ;
    END
  END b[130]
  PIN b[131]
    DIRECTION OUTPUT ;
    USE SIGNAL ;
    PORT
      LAYER M4 ;
        RECT  51.756 1.152 51.84 1.176 ;
    END
  END b[131]
  PIN b[132]
    DIRECTION OUTPUT ;
    USE SIGNAL ;
    PORT
      LAYER M4 ;
        RECT  51.756 1.296 51.84 1.32 ;
    END
  END b[132]
  PIN b[133]
    DIRECTION OUTPUT ;
    USE SIGNAL ;
    PORT
      LAYER M4 ;
        RECT  51.756 1.44 51.84 1.464 ;
    END
  END b[133]
  PIN b[134]
    DIRECTION OUTPUT ;
    USE SIGNAL ;
    PORT
      LAYER M4 ;
        RECT  51.756 1.584 51.84 1.608 ;
    END
  END b[134]
  PIN b[135]
    DIRECTION OUTPUT ;
    USE SIGNAL ;
    PORT
      LAYER M4 ;
        RECT  51.756 1.728 51.84 1.752 ;
    END
  END b[135]
  PIN b[136]
    DIRECTION OUTPUT ;
    USE SIGNAL ;
    PORT
      LAYER M4 ;
        RECT  51.756 1.872 51.84 1.896 ;
    END
  END b[136]
  PIN b[137]
    DIRECTION OUTPUT ;
    USE SIGNAL ;
    PORT
      LAYER M4 ;
        RECT  51.756 2.016 51.84 2.04 ;
    END
  END b[137]
  PIN b[138]
    DIRECTION OUTPUT ;
    USE SIGNAL ;
    PORT
      LAYER M4 ;
        RECT  51.756 2.16 51.84 2.184 ;
    END
  END b[138]
  PIN b[139]
    DIRECTION OUTPUT ;
    USE SIGNAL ;
    PORT
      LAYER M4 ;
        RECT  51.756 2.304 51.84 2.328 ;
    END
  END b[139]
  PIN b[13]
    DIRECTION OUTPUT ;
    USE SIGNAL ;
    PORT
      LAYER M4 ;
        RECT  51.756 25.632 51.84 25.656 ;
    END
  END b[13]
  PIN b[140]
    DIRECTION OUTPUT ;
    USE SIGNAL ;
    PORT
      LAYER M4 ;
        RECT  51.756 2.448 51.84 2.472 ;
    END
  END b[140]
  PIN b[141]
    DIRECTION OUTPUT ;
    USE SIGNAL ;
    PORT
      LAYER M4 ;
        RECT  51.756 2.592 51.84 2.616 ;
    END
  END b[141]
  PIN b[142]
    DIRECTION OUTPUT ;
    USE SIGNAL ;
    PORT
      LAYER M4 ;
        RECT  51.756 2.736 51.84 2.76 ;
    END
  END b[142]
  PIN b[143]
    DIRECTION OUTPUT ;
    USE SIGNAL ;
    PORT
      LAYER M4 ;
        RECT  51.756 2.88 51.84 2.904 ;
    END
  END b[143]
  PIN b[144]
    DIRECTION OUTPUT ;
    USE SIGNAL ;
    PORT
      LAYER M4 ;
        RECT  51.756 3.024 51.84 3.048 ;
    END
  END b[144]
  PIN b[145]
    DIRECTION OUTPUT ;
    USE SIGNAL ;
    PORT
      LAYER M4 ;
        RECT  51.756 3.168 51.84 3.192 ;
    END
  END b[145]
  PIN b[146]
    DIRECTION OUTPUT ;
    USE SIGNAL ;
    PORT
      LAYER M4 ;
        RECT  51.756 3.312 51.84 3.336 ;
    END
  END b[146]
  PIN b[147]
    DIRECTION OUTPUT ;
    USE SIGNAL ;
    PORT
      LAYER M4 ;
        RECT  51.756 3.456 51.84 3.48 ;
    END
  END b[147]
  PIN b[148]
    DIRECTION OUTPUT ;
    USE SIGNAL ;
    PORT
      LAYER M4 ;
        RECT  51.756 3.6 51.84 3.624 ;
    END
  END b[148]
  PIN b[149]
    DIRECTION OUTPUT ;
    USE SIGNAL ;
    PORT
      LAYER M4 ;
        RECT  51.756 3.744 51.84 3.768 ;
    END
  END b[149]
  PIN b[14]
    DIRECTION OUTPUT ;
    USE SIGNAL ;
    PORT
      LAYER M4 ;
        RECT  51.756 25.776 51.84 25.8 ;
    END
  END b[14]
  PIN b[150]
    DIRECTION OUTPUT ;
    USE SIGNAL ;
    PORT
      LAYER M4 ;
        RECT  51.756 3.888 51.84 3.912 ;
    END
  END b[150]
  PIN b[151]
    DIRECTION OUTPUT ;
    USE SIGNAL ;
    PORT
      LAYER M4 ;
        RECT  51.756 4.032 51.84 4.056 ;
    END
  END b[151]
  PIN b[152]
    DIRECTION OUTPUT ;
    USE SIGNAL ;
    PORT
      LAYER M4 ;
        RECT  51.756 4.176 51.84 4.2 ;
    END
  END b[152]
  PIN b[153]
    DIRECTION OUTPUT ;
    USE SIGNAL ;
    PORT
      LAYER M4 ;
        RECT  51.756 4.32 51.84 4.344 ;
    END
  END b[153]
  PIN b[154]
    DIRECTION OUTPUT ;
    USE SIGNAL ;
    PORT
      LAYER M4 ;
        RECT  51.756 4.464 51.84 4.488 ;
    END
  END b[154]
  PIN b[155]
    DIRECTION OUTPUT ;
    USE SIGNAL ;
    PORT
      LAYER M4 ;
        RECT  51.756 4.608 51.84 4.632 ;
    END
  END b[155]
  PIN b[156]
    DIRECTION OUTPUT ;
    USE SIGNAL ;
    PORT
      LAYER M4 ;
        RECT  51.756 4.752 51.84 4.776 ;
    END
  END b[156]
  PIN b[157]
    DIRECTION OUTPUT ;
    USE SIGNAL ;
    PORT
      LAYER M4 ;
        RECT  51.756 4.896 51.84 4.92 ;
    END
  END b[157]
  PIN b[158]
    DIRECTION OUTPUT ;
    USE SIGNAL ;
    PORT
      LAYER M4 ;
        RECT  51.756 5.04 51.84 5.064 ;
    END
  END b[158]
  PIN b[159]
    DIRECTION OUTPUT ;
    USE SIGNAL ;
    PORT
      LAYER M4 ;
        RECT  51.756 5.184 51.84 5.208 ;
    END
  END b[159]
  PIN b[15]
    DIRECTION OUTPUT ;
    USE SIGNAL ;
    PORT
      LAYER M4 ;
        RECT  51.756 25.92 51.84 25.944 ;
    END
  END b[15]
  PIN b[160]
    DIRECTION OUTPUT ;
    USE SIGNAL ;
    PORT
      LAYER M4 ;
        RECT  51.756 29.52 51.84 29.544 ;
    END
  END b[160]
  PIN b[161]
    DIRECTION OUTPUT ;
    USE SIGNAL ;
    PORT
      LAYER M4 ;
        RECT  51.756 29.664 51.84 29.688 ;
    END
  END b[161]
  PIN b[162]
    DIRECTION OUTPUT ;
    USE SIGNAL ;
    PORT
      LAYER M4 ;
        RECT  51.756 29.808 51.84 29.832 ;
    END
  END b[162]
  PIN b[163]
    DIRECTION OUTPUT ;
    USE SIGNAL ;
    PORT
      LAYER M4 ;
        RECT  51.756 29.952 51.84 29.976 ;
    END
  END b[163]
  PIN b[164]
    DIRECTION OUTPUT ;
    USE SIGNAL ;
    PORT
      LAYER M4 ;
        RECT  51.756 30.096 51.84 30.12 ;
    END
  END b[164]
  PIN b[165]
    DIRECTION OUTPUT ;
    USE SIGNAL ;
    PORT
      LAYER M4 ;
        RECT  51.756 30.24 51.84 30.264 ;
    END
  END b[165]
  PIN b[166]
    DIRECTION OUTPUT ;
    USE SIGNAL ;
    PORT
      LAYER M4 ;
        RECT  51.756 30.384 51.84 30.408 ;
    END
  END b[166]
  PIN b[167]
    DIRECTION OUTPUT ;
    USE SIGNAL ;
    PORT
      LAYER M4 ;
        RECT  51.756 30.528 51.84 30.552 ;
    END
  END b[167]
  PIN b[168]
    DIRECTION OUTPUT ;
    USE SIGNAL ;
    PORT
      LAYER M4 ;
        RECT  51.756 30.672 51.84 30.696 ;
    END
  END b[168]
  PIN b[169]
    DIRECTION OUTPUT ;
    USE SIGNAL ;
    PORT
      LAYER M4 ;
        RECT  51.756 30.816 51.84 30.84 ;
    END
  END b[169]
  PIN b[16]
    DIRECTION OUTPUT ;
    USE SIGNAL ;
    PORT
      LAYER M4 ;
        RECT  51.756 26.064 51.84 26.088 ;
    END
  END b[16]
  PIN b[170]
    DIRECTION OUTPUT ;
    USE SIGNAL ;
    PORT
      LAYER M4 ;
        RECT  51.756 30.96 51.84 30.984 ;
    END
  END b[170]
  PIN b[171]
    DIRECTION OUTPUT ;
    USE SIGNAL ;
    PORT
      LAYER M4 ;
        RECT  51.756 31.104 51.84 31.128 ;
    END
  END b[171]
  PIN b[172]
    DIRECTION OUTPUT ;
    USE SIGNAL ;
    PORT
      LAYER M4 ;
        RECT  51.756 31.248 51.84 31.272 ;
    END
  END b[172]
  PIN b[173]
    DIRECTION OUTPUT ;
    USE SIGNAL ;
    PORT
      LAYER M4 ;
        RECT  51.756 31.392 51.84 31.416 ;
    END
  END b[173]
  PIN b[174]
    DIRECTION OUTPUT ;
    USE SIGNAL ;
    PORT
      LAYER M4 ;
        RECT  51.756 31.536 51.84 31.56 ;
    END
  END b[174]
  PIN b[175]
    DIRECTION OUTPUT ;
    USE SIGNAL ;
    PORT
      LAYER M4 ;
        RECT  51.756 31.68 51.84 31.704 ;
    END
  END b[175]
  PIN b[176]
    DIRECTION OUTPUT ;
    USE SIGNAL ;
    PORT
      LAYER M4 ;
        RECT  51.756 31.824 51.84 31.848 ;
    END
  END b[176]
  PIN b[177]
    DIRECTION OUTPUT ;
    USE SIGNAL ;
    PORT
      LAYER M4 ;
        RECT  51.756 31.968 51.84 31.992 ;
    END
  END b[177]
  PIN b[178]
    DIRECTION OUTPUT ;
    USE SIGNAL ;
    PORT
      LAYER M4 ;
        RECT  51.756 32.112 51.84 32.136 ;
    END
  END b[178]
  PIN b[179]
    DIRECTION OUTPUT ;
    USE SIGNAL ;
    PORT
      LAYER M4 ;
        RECT  51.756 32.256 51.84 32.28 ;
    END
  END b[179]
  PIN b[17]
    DIRECTION OUTPUT ;
    USE SIGNAL ;
    PORT
      LAYER M4 ;
        RECT  51.756 26.208 51.84 26.232 ;
    END
  END b[17]
  PIN b[180]
    DIRECTION OUTPUT ;
    USE SIGNAL ;
    PORT
      LAYER M4 ;
        RECT  51.756 32.4 51.84 32.424 ;
    END
  END b[180]
  PIN b[181]
    DIRECTION OUTPUT ;
    USE SIGNAL ;
    PORT
      LAYER M4 ;
        RECT  51.756 32.544 51.84 32.568 ;
    END
  END b[181]
  PIN b[182]
    DIRECTION OUTPUT ;
    USE SIGNAL ;
    PORT
      LAYER M4 ;
        RECT  51.756 32.688 51.84 32.712 ;
    END
  END b[182]
  PIN b[183]
    DIRECTION OUTPUT ;
    USE SIGNAL ;
    PORT
      LAYER M4 ;
        RECT  51.756 32.832 51.84 32.856 ;
    END
  END b[183]
  PIN b[184]
    DIRECTION OUTPUT ;
    USE SIGNAL ;
    PORT
      LAYER M4 ;
        RECT  51.756 32.976 51.84 33 ;
    END
  END b[184]
  PIN b[185]
    DIRECTION OUTPUT ;
    USE SIGNAL ;
    PORT
      LAYER M4 ;
        RECT  51.756 33.12 51.84 33.144 ;
    END
  END b[185]
  PIN b[186]
    DIRECTION OUTPUT ;
    USE SIGNAL ;
    PORT
      LAYER M4 ;
        RECT  51.756 33.264 51.84 33.288 ;
    END
  END b[186]
  PIN b[187]
    DIRECTION OUTPUT ;
    USE SIGNAL ;
    PORT
      LAYER M4 ;
        RECT  51.756 33.408 51.84 33.432 ;
    END
  END b[187]
  PIN b[188]
    DIRECTION OUTPUT ;
    USE SIGNAL ;
    PORT
      LAYER M4 ;
        RECT  51.756 33.552 51.84 33.576 ;
    END
  END b[188]
  PIN b[189]
    DIRECTION OUTPUT ;
    USE SIGNAL ;
    PORT
      LAYER M4 ;
        RECT  51.756 33.696 51.84 33.72 ;
    END
  END b[189]
  PIN b[18]
    DIRECTION OUTPUT ;
    USE SIGNAL ;
    PORT
      LAYER M4 ;
        RECT  51.756 26.352 51.84 26.376 ;
    END
  END b[18]
  PIN b[190]
    DIRECTION OUTPUT ;
    USE SIGNAL ;
    PORT
      LAYER M4 ;
        RECT  51.756 33.84 51.84 33.864 ;
    END
  END b[190]
  PIN b[191]
    DIRECTION OUTPUT ;
    USE SIGNAL ;
    PORT
      LAYER M4 ;
        RECT  51.756 33.984 51.84 34.008 ;
    END
  END b[191]
  PIN b[192]
    DIRECTION OUTPUT ;
    USE SIGNAL ;
    PORT
      LAYER M4 ;
        RECT  51.756 19.152 51.84 19.176 ;
    END
  END b[192]
  PIN b[193]
    DIRECTION OUTPUT ;
    USE SIGNAL ;
    PORT
      LAYER M4 ;
        RECT  51.756 19.296 51.84 19.32 ;
    END
  END b[193]
  PIN b[194]
    DIRECTION OUTPUT ;
    USE SIGNAL ;
    PORT
      LAYER M4 ;
        RECT  51.756 19.44 51.84 19.464 ;
    END
  END b[194]
  PIN b[195]
    DIRECTION OUTPUT ;
    USE SIGNAL ;
    PORT
      LAYER M4 ;
        RECT  51.756 19.584 51.84 19.608 ;
    END
  END b[195]
  PIN b[196]
    DIRECTION OUTPUT ;
    USE SIGNAL ;
    PORT
      LAYER M4 ;
        RECT  51.756 19.728 51.84 19.752 ;
    END
  END b[196]
  PIN b[197]
    DIRECTION OUTPUT ;
    USE SIGNAL ;
    PORT
      LAYER M4 ;
        RECT  51.756 19.872 51.84 19.896 ;
    END
  END b[197]
  PIN b[198]
    DIRECTION OUTPUT ;
    USE SIGNAL ;
    PORT
      LAYER M4 ;
        RECT  51.756 20.016 51.84 20.04 ;
    END
  END b[198]
  PIN b[199]
    DIRECTION OUTPUT ;
    USE SIGNAL ;
    PORT
      LAYER M4 ;
        RECT  51.756 20.16 51.84 20.184 ;
    END
  END b[199]
  PIN b[19]
    DIRECTION OUTPUT ;
    USE SIGNAL ;
    PORT
      LAYER M4 ;
        RECT  51.756 26.496 51.84 26.52 ;
    END
  END b[19]
  PIN b[1]
    DIRECTION OUTPUT ;
    USE SIGNAL ;
    PORT
      LAYER M4 ;
        RECT  51.756 23.904 51.84 23.928 ;
    END
  END b[1]
  PIN b[200]
    DIRECTION OUTPUT ;
    USE SIGNAL ;
    PORT
      LAYER M4 ;
        RECT  51.756 20.304 51.84 20.328 ;
    END
  END b[200]
  PIN b[201]
    DIRECTION OUTPUT ;
    USE SIGNAL ;
    PORT
      LAYER M4 ;
        RECT  51.756 20.448 51.84 20.472 ;
    END
  END b[201]
  PIN b[202]
    DIRECTION OUTPUT ;
    USE SIGNAL ;
    PORT
      LAYER M4 ;
        RECT  51.756 20.592 51.84 20.616 ;
    END
  END b[202]
  PIN b[203]
    DIRECTION OUTPUT ;
    USE SIGNAL ;
    PORT
      LAYER M4 ;
        RECT  51.756 20.736 51.84 20.76 ;
    END
  END b[203]
  PIN b[204]
    DIRECTION OUTPUT ;
    USE SIGNAL ;
    PORT
      LAYER M4 ;
        RECT  51.756 20.88 51.84 20.904 ;
    END
  END b[204]
  PIN b[205]
    DIRECTION OUTPUT ;
    USE SIGNAL ;
    PORT
      LAYER M4 ;
        RECT  51.756 21.024 51.84 21.048 ;
    END
  END b[205]
  PIN b[206]
    DIRECTION OUTPUT ;
    USE SIGNAL ;
    PORT
      LAYER M4 ;
        RECT  51.756 21.168 51.84 21.192 ;
    END
  END b[206]
  PIN b[207]
    DIRECTION OUTPUT ;
    USE SIGNAL ;
    PORT
      LAYER M4 ;
        RECT  51.756 21.312 51.84 21.336 ;
    END
  END b[207]
  PIN b[208]
    DIRECTION OUTPUT ;
    USE SIGNAL ;
    PORT
      LAYER M4 ;
        RECT  51.756 21.456 51.84 21.48 ;
    END
  END b[208]
  PIN b[209]
    DIRECTION OUTPUT ;
    USE SIGNAL ;
    PORT
      LAYER M4 ;
        RECT  51.756 21.6 51.84 21.624 ;
    END
  END b[209]
  PIN b[20]
    DIRECTION OUTPUT ;
    USE SIGNAL ;
    PORT
      LAYER M4 ;
        RECT  51.756 26.64 51.84 26.664 ;
    END
  END b[20]
  PIN b[210]
    DIRECTION OUTPUT ;
    USE SIGNAL ;
    PORT
      LAYER M4 ;
        RECT  51.756 21.744 51.84 21.768 ;
    END
  END b[210]
  PIN b[211]
    DIRECTION OUTPUT ;
    USE SIGNAL ;
    PORT
      LAYER M4 ;
        RECT  51.756 21.888 51.84 21.912 ;
    END
  END b[211]
  PIN b[212]
    DIRECTION OUTPUT ;
    USE SIGNAL ;
    PORT
      LAYER M4 ;
        RECT  51.756 22.032 51.84 22.056 ;
    END
  END b[212]
  PIN b[213]
    DIRECTION OUTPUT ;
    USE SIGNAL ;
    PORT
      LAYER M4 ;
        RECT  51.756 22.176 51.84 22.2 ;
    END
  END b[213]
  PIN b[214]
    DIRECTION OUTPUT ;
    USE SIGNAL ;
    PORT
      LAYER M4 ;
        RECT  51.756 22.32 51.84 22.344 ;
    END
  END b[214]
  PIN b[215]
    DIRECTION OUTPUT ;
    USE SIGNAL ;
    PORT
      LAYER M4 ;
        RECT  51.756 22.464 51.84 22.488 ;
    END
  END b[215]
  PIN b[216]
    DIRECTION OUTPUT ;
    USE SIGNAL ;
    PORT
      LAYER M4 ;
        RECT  51.756 22.608 51.84 22.632 ;
    END
  END b[216]
  PIN b[217]
    DIRECTION OUTPUT ;
    USE SIGNAL ;
    PORT
      LAYER M4 ;
        RECT  51.756 22.752 51.84 22.776 ;
    END
  END b[217]
  PIN b[218]
    DIRECTION OUTPUT ;
    USE SIGNAL ;
    PORT
      LAYER M4 ;
        RECT  51.756 22.896 51.84 22.92 ;
    END
  END b[218]
  PIN b[219]
    DIRECTION OUTPUT ;
    USE SIGNAL ;
    PORT
      LAYER M4 ;
        RECT  51.756 23.04 51.84 23.064 ;
    END
  END b[219]
  PIN b[21]
    DIRECTION OUTPUT ;
    USE SIGNAL ;
    PORT
      LAYER M4 ;
        RECT  51.756 26.784 51.84 26.808 ;
    END
  END b[21]
  PIN b[220]
    DIRECTION OUTPUT ;
    USE SIGNAL ;
    PORT
      LAYER M4 ;
        RECT  51.756 23.184 51.84 23.208 ;
    END
  END b[220]
  PIN b[221]
    DIRECTION OUTPUT ;
    USE SIGNAL ;
    PORT
      LAYER M4 ;
        RECT  51.756 23.328 51.84 23.352 ;
    END
  END b[221]
  PIN b[222]
    DIRECTION OUTPUT ;
    USE SIGNAL ;
    PORT
      LAYER M4 ;
        RECT  51.756 23.472 51.84 23.496 ;
    END
  END b[222]
  PIN b[223]
    DIRECTION OUTPUT ;
    USE SIGNAL ;
    PORT
      LAYER M4 ;
        RECT  51.756 23.616 51.84 23.64 ;
    END
  END b[223]
  PIN b[224]
    DIRECTION OUTPUT ;
    USE SIGNAL ;
    PORT
      LAYER M4 ;
        RECT  51.756 9.936 51.84 9.96 ;
    END
  END b[224]
  PIN b[225]
    DIRECTION OUTPUT ;
    USE SIGNAL ;
    PORT
      LAYER M4 ;
        RECT  51.756 10.08 51.84 10.104 ;
    END
  END b[225]
  PIN b[226]
    DIRECTION OUTPUT ;
    USE SIGNAL ;
    PORT
      LAYER M4 ;
        RECT  51.756 10.224 51.84 10.248 ;
    END
  END b[226]
  PIN b[227]
    DIRECTION OUTPUT ;
    USE SIGNAL ;
    PORT
      LAYER M4 ;
        RECT  51.756 10.368 51.84 10.392 ;
    END
  END b[227]
  PIN b[228]
    DIRECTION OUTPUT ;
    USE SIGNAL ;
    PORT
      LAYER M4 ;
        RECT  51.756 10.512 51.84 10.536 ;
    END
  END b[228]
  PIN b[229]
    DIRECTION OUTPUT ;
    USE SIGNAL ;
    PORT
      LAYER M4 ;
        RECT  51.756 10.656 51.84 10.68 ;
    END
  END b[229]
  PIN b[22]
    DIRECTION OUTPUT ;
    USE SIGNAL ;
    PORT
      LAYER M4 ;
        RECT  51.756 26.928 51.84 26.952 ;
    END
  END b[22]
  PIN b[230]
    DIRECTION OUTPUT ;
    USE SIGNAL ;
    PORT
      LAYER M4 ;
        RECT  51.756 10.8 51.84 10.824 ;
    END
  END b[230]
  PIN b[231]
    DIRECTION OUTPUT ;
    USE SIGNAL ;
    PORT
      LAYER M4 ;
        RECT  51.756 10.944 51.84 10.968 ;
    END
  END b[231]
  PIN b[232]
    DIRECTION OUTPUT ;
    USE SIGNAL ;
    PORT
      LAYER M4 ;
        RECT  51.756 11.088 51.84 11.112 ;
    END
  END b[232]
  PIN b[233]
    DIRECTION OUTPUT ;
    USE SIGNAL ;
    PORT
      LAYER M4 ;
        RECT  51.756 11.232 51.84 11.256 ;
    END
  END b[233]
  PIN b[234]
    DIRECTION OUTPUT ;
    USE SIGNAL ;
    PORT
      LAYER M4 ;
        RECT  51.756 11.376 51.84 11.4 ;
    END
  END b[234]
  PIN b[235]
    DIRECTION OUTPUT ;
    USE SIGNAL ;
    PORT
      LAYER M4 ;
        RECT  51.756 11.52 51.84 11.544 ;
    END
  END b[235]
  PIN b[236]
    DIRECTION OUTPUT ;
    USE SIGNAL ;
    PORT
      LAYER M4 ;
        RECT  51.756 11.664 51.84 11.688 ;
    END
  END b[236]
  PIN b[237]
    DIRECTION OUTPUT ;
    USE SIGNAL ;
    PORT
      LAYER M4 ;
        RECT  51.756 11.808 51.84 11.832 ;
    END
  END b[237]
  PIN b[238]
    DIRECTION OUTPUT ;
    USE SIGNAL ;
    PORT
      LAYER M4 ;
        RECT  51.756 11.952 51.84 11.976 ;
    END
  END b[238]
  PIN b[239]
    DIRECTION OUTPUT ;
    USE SIGNAL ;
    PORT
      LAYER M4 ;
        RECT  51.756 12.096 51.84 12.12 ;
    END
  END b[239]
  PIN b[23]
    DIRECTION OUTPUT ;
    USE SIGNAL ;
    PORT
      LAYER M4 ;
        RECT  51.756 27.072 51.84 27.096 ;
    END
  END b[23]
  PIN b[240]
    DIRECTION OUTPUT ;
    USE SIGNAL ;
    PORT
      LAYER M4 ;
        RECT  51.756 12.24 51.84 12.264 ;
    END
  END b[240]
  PIN b[241]
    DIRECTION OUTPUT ;
    USE SIGNAL ;
    PORT
      LAYER M4 ;
        RECT  51.756 12.384 51.84 12.408 ;
    END
  END b[241]
  PIN b[242]
    DIRECTION OUTPUT ;
    USE SIGNAL ;
    PORT
      LAYER M4 ;
        RECT  51.756 12.528 51.84 12.552 ;
    END
  END b[242]
  PIN b[243]
    DIRECTION OUTPUT ;
    USE SIGNAL ;
    PORT
      LAYER M4 ;
        RECT  51.756 12.672 51.84 12.696 ;
    END
  END b[243]
  PIN b[244]
    DIRECTION OUTPUT ;
    USE SIGNAL ;
    PORT
      LAYER M4 ;
        RECT  51.756 12.816 51.84 12.84 ;
    END
  END b[244]
  PIN b[245]
    DIRECTION OUTPUT ;
    USE SIGNAL ;
    PORT
      LAYER M4 ;
        RECT  51.756 12.96 51.84 12.984 ;
    END
  END b[245]
  PIN b[246]
    DIRECTION OUTPUT ;
    USE SIGNAL ;
    PORT
      LAYER M4 ;
        RECT  51.756 13.104 51.84 13.128 ;
    END
  END b[246]
  PIN b[247]
    DIRECTION OUTPUT ;
    USE SIGNAL ;
    PORT
      LAYER M4 ;
        RECT  51.756 13.248 51.84 13.272 ;
    END
  END b[247]
  PIN b[248]
    DIRECTION OUTPUT ;
    USE SIGNAL ;
    PORT
      LAYER M4 ;
        RECT  51.756 13.392 51.84 13.416 ;
    END
  END b[248]
  PIN b[249]
    DIRECTION OUTPUT ;
    USE SIGNAL ;
    PORT
      LAYER M4 ;
        RECT  51.756 13.536 51.84 13.56 ;
    END
  END b[249]
  PIN b[24]
    DIRECTION OUTPUT ;
    USE SIGNAL ;
    PORT
      LAYER M4 ;
        RECT  51.756 27.216 51.84 27.24 ;
    END
  END b[24]
  PIN b[250]
    DIRECTION OUTPUT ;
    USE SIGNAL ;
    PORT
      LAYER M4 ;
        RECT  51.756 13.68 51.84 13.704 ;
    END
  END b[250]
  PIN b[251]
    DIRECTION OUTPUT ;
    USE SIGNAL ;
    PORT
      LAYER M4 ;
        RECT  51.756 13.824 51.84 13.848 ;
    END
  END b[251]
  PIN b[252]
    DIRECTION OUTPUT ;
    USE SIGNAL ;
    PORT
      LAYER M4 ;
        RECT  51.756 13.968 51.84 13.992 ;
    END
  END b[252]
  PIN b[253]
    DIRECTION OUTPUT ;
    USE SIGNAL ;
    PORT
      LAYER M4 ;
        RECT  51.756 14.112 51.84 14.136 ;
    END
  END b[253]
  PIN b[254]
    DIRECTION OUTPUT ;
    USE SIGNAL ;
    PORT
      LAYER M4 ;
        RECT  51.756 14.256 51.84 14.28 ;
    END
  END b[254]
  PIN b[255]
    DIRECTION OUTPUT ;
    USE SIGNAL ;
    PORT
      LAYER M4 ;
        RECT  51.756 14.4 51.84 14.424 ;
    END
  END b[255]
  PIN b[256]
    DIRECTION OUTPUT ;
    USE SIGNAL ;
    PORT
      LAYER M4 ;
        RECT  51.756 5.328 51.84 5.352 ;
    END
  END b[256]
  PIN b[257]
    DIRECTION OUTPUT ;
    USE SIGNAL ;
    PORT
      LAYER M4 ;
        RECT  51.756 5.472 51.84 5.496 ;
    END
  END b[257]
  PIN b[258]
    DIRECTION OUTPUT ;
    USE SIGNAL ;
    PORT
      LAYER M4 ;
        RECT  51.756 5.616 51.84 5.64 ;
    END
  END b[258]
  PIN b[259]
    DIRECTION OUTPUT ;
    USE SIGNAL ;
    PORT
      LAYER M4 ;
        RECT  51.756 5.76 51.84 5.784 ;
    END
  END b[259]
  PIN b[25]
    DIRECTION OUTPUT ;
    USE SIGNAL ;
    PORT
      LAYER M4 ;
        RECT  51.756 27.36 51.84 27.384 ;
    END
  END b[25]
  PIN b[260]
    DIRECTION OUTPUT ;
    USE SIGNAL ;
    PORT
      LAYER M4 ;
        RECT  51.756 5.904 51.84 5.928 ;
    END
  END b[260]
  PIN b[261]
    DIRECTION OUTPUT ;
    USE SIGNAL ;
    PORT
      LAYER M4 ;
        RECT  51.756 6.048 51.84 6.072 ;
    END
  END b[261]
  PIN b[262]
    DIRECTION OUTPUT ;
    USE SIGNAL ;
    PORT
      LAYER M4 ;
        RECT  51.756 6.192 51.84 6.216 ;
    END
  END b[262]
  PIN b[263]
    DIRECTION OUTPUT ;
    USE SIGNAL ;
    PORT
      LAYER M4 ;
        RECT  51.756 6.336 51.84 6.36 ;
    END
  END b[263]
  PIN b[264]
    DIRECTION OUTPUT ;
    USE SIGNAL ;
    PORT
      LAYER M4 ;
        RECT  51.756 6.48 51.84 6.504 ;
    END
  END b[264]
  PIN b[265]
    DIRECTION OUTPUT ;
    USE SIGNAL ;
    PORT
      LAYER M4 ;
        RECT  51.756 6.624 51.84 6.648 ;
    END
  END b[265]
  PIN b[266]
    DIRECTION OUTPUT ;
    USE SIGNAL ;
    PORT
      LAYER M4 ;
        RECT  51.756 6.768 51.84 6.792 ;
    END
  END b[266]
  PIN b[267]
    DIRECTION OUTPUT ;
    USE SIGNAL ;
    PORT
      LAYER M4 ;
        RECT  51.756 6.912 51.84 6.936 ;
    END
  END b[267]
  PIN b[268]
    DIRECTION OUTPUT ;
    USE SIGNAL ;
    PORT
      LAYER M4 ;
        RECT  51.756 7.056 51.84 7.08 ;
    END
  END b[268]
  PIN b[269]
    DIRECTION OUTPUT ;
    USE SIGNAL ;
    PORT
      LAYER M4 ;
        RECT  51.756 7.2 51.84 7.224 ;
    END
  END b[269]
  PIN b[26]
    DIRECTION OUTPUT ;
    USE SIGNAL ;
    PORT
      LAYER M4 ;
        RECT  51.756 27.504 51.84 27.528 ;
    END
  END b[26]
  PIN b[270]
    DIRECTION OUTPUT ;
    USE SIGNAL ;
    PORT
      LAYER M4 ;
        RECT  51.756 7.344 51.84 7.368 ;
    END
  END b[270]
  PIN b[271]
    DIRECTION OUTPUT ;
    USE SIGNAL ;
    PORT
      LAYER M4 ;
        RECT  51.756 7.488 51.84 7.512 ;
    END
  END b[271]
  PIN b[272]
    DIRECTION OUTPUT ;
    USE SIGNAL ;
    PORT
      LAYER M4 ;
        RECT  51.756 7.632 51.84 7.656 ;
    END
  END b[272]
  PIN b[273]
    DIRECTION OUTPUT ;
    USE SIGNAL ;
    PORT
      LAYER M4 ;
        RECT  51.756 7.776 51.84 7.8 ;
    END
  END b[273]
  PIN b[274]
    DIRECTION OUTPUT ;
    USE SIGNAL ;
    PORT
      LAYER M4 ;
        RECT  51.756 7.92 51.84 7.944 ;
    END
  END b[274]
  PIN b[275]
    DIRECTION OUTPUT ;
    USE SIGNAL ;
    PORT
      LAYER M4 ;
        RECT  51.756 8.064 51.84 8.088 ;
    END
  END b[275]
  PIN b[276]
    DIRECTION OUTPUT ;
    USE SIGNAL ;
    PORT
      LAYER M4 ;
        RECT  51.756 8.208 51.84 8.232 ;
    END
  END b[276]
  PIN b[277]
    DIRECTION OUTPUT ;
    USE SIGNAL ;
    PORT
      LAYER M4 ;
        RECT  51.756 8.352 51.84 8.376 ;
    END
  END b[277]
  PIN b[278]
    DIRECTION OUTPUT ;
    USE SIGNAL ;
    PORT
      LAYER M4 ;
        RECT  51.756 8.496 51.84 8.52 ;
    END
  END b[278]
  PIN b[279]
    DIRECTION OUTPUT ;
    USE SIGNAL ;
    PORT
      LAYER M4 ;
        RECT  51.756 8.64 51.84 8.664 ;
    END
  END b[279]
  PIN b[27]
    DIRECTION OUTPUT ;
    USE SIGNAL ;
    PORT
      LAYER M4 ;
        RECT  51.756 27.648 51.84 27.672 ;
    END
  END b[27]
  PIN b[280]
    DIRECTION OUTPUT ;
    USE SIGNAL ;
    PORT
      LAYER M4 ;
        RECT  51.756 8.784 51.84 8.808 ;
    END
  END b[280]
  PIN b[281]
    DIRECTION OUTPUT ;
    USE SIGNAL ;
    PORT
      LAYER M4 ;
        RECT  51.756 8.928 51.84 8.952 ;
    END
  END b[281]
  PIN b[282]
    DIRECTION OUTPUT ;
    USE SIGNAL ;
    PORT
      LAYER M4 ;
        RECT  51.756 9.072 51.84 9.096 ;
    END
  END b[282]
  PIN b[283]
    DIRECTION OUTPUT ;
    USE SIGNAL ;
    PORT
      LAYER M4 ;
        RECT  51.756 9.216 51.84 9.24 ;
    END
  END b[283]
  PIN b[284]
    DIRECTION OUTPUT ;
    USE SIGNAL ;
    PORT
      LAYER M4 ;
        RECT  51.756 9.36 51.84 9.384 ;
    END
  END b[284]
  PIN b[285]
    DIRECTION OUTPUT ;
    USE SIGNAL ;
    PORT
      LAYER M4 ;
        RECT  51.756 9.504 51.84 9.528 ;
    END
  END b[285]
  PIN b[286]
    DIRECTION OUTPUT ;
    USE SIGNAL ;
    PORT
      LAYER M4 ;
        RECT  51.756 9.648 51.84 9.672 ;
    END
  END b[286]
  PIN b[287]
    DIRECTION OUTPUT ;
    USE SIGNAL ;
    PORT
      LAYER M4 ;
        RECT  51.756 9.792 51.84 9.816 ;
    END
  END b[287]
  PIN b[288]
    DIRECTION OUTPUT ;
    USE SIGNAL ;
    PORT
      LAYER M4 ;
        RECT  51.756 28.368 51.84 28.392 ;
    END
  END b[288]
  PIN b[289]
    DIRECTION OUTPUT ;
    USE SIGNAL ;
    PORT
      LAYER M4 ;
        RECT  51.756 28.512 51.84 28.536 ;
    END
  END b[289]
  PIN b[28]
    DIRECTION OUTPUT ;
    USE SIGNAL ;
    PORT
      LAYER M4 ;
        RECT  51.756 27.792 51.84 27.816 ;
    END
  END b[28]
  PIN b[290]
    DIRECTION OUTPUT ;
    USE SIGNAL ;
    PORT
      LAYER M4 ;
        RECT  51.756 28.656 51.84 28.68 ;
    END
  END b[290]
  PIN b[291]
    DIRECTION OUTPUT ;
    USE SIGNAL ;
    PORT
      LAYER M4 ;
        RECT  51.756 28.8 51.84 28.824 ;
    END
  END b[291]
  PIN b[292]
    DIRECTION OUTPUT ;
    USE SIGNAL ;
    PORT
      LAYER M4 ;
        RECT  51.756 28.944 51.84 28.968 ;
    END
  END b[292]
  PIN b[293]
    DIRECTION OUTPUT ;
    USE SIGNAL ;
    PORT
      LAYER M4 ;
        RECT  51.756 29.088 51.84 29.112 ;
    END
  END b[293]
  PIN b[294]
    DIRECTION OUTPUT ;
    USE SIGNAL ;
    PORT
      LAYER M4 ;
        RECT  51.756 29.232 51.84 29.256 ;
    END
  END b[294]
  PIN b[295]
    DIRECTION OUTPUT ;
    USE SIGNAL ;
    PORT
      LAYER M4 ;
        RECT  51.756 29.376 51.84 29.4 ;
    END
  END b[295]
  PIN b[29]
    DIRECTION OUTPUT ;
    USE SIGNAL ;
    PORT
      LAYER M4 ;
        RECT  51.756 27.936 51.84 27.96 ;
    END
  END b[29]
  PIN b[2]
    DIRECTION OUTPUT ;
    USE SIGNAL ;
    PORT
      LAYER M4 ;
        RECT  51.756 24.048 51.84 24.072 ;
    END
  END b[2]
  PIN b[30]
    DIRECTION OUTPUT ;
    USE SIGNAL ;
    PORT
      LAYER M4 ;
        RECT  51.756 28.08 51.84 28.104 ;
    END
  END b[30]
  PIN b[31]
    DIRECTION OUTPUT ;
    USE SIGNAL ;
    PORT
      LAYER M4 ;
        RECT  51.756 28.224 51.84 28.248 ;
    END
  END b[31]
  PIN b[32]
    DIRECTION OUTPUT ;
    USE SIGNAL ;
    PORT
      LAYER M4 ;
        RECT  51.756 38.736 51.84 38.76 ;
    END
  END b[32]
  PIN b[33]
    DIRECTION OUTPUT ;
    USE SIGNAL ;
    PORT
      LAYER M4 ;
        RECT  51.756 38.88 51.84 38.904 ;
    END
  END b[33]
  PIN b[34]
    DIRECTION OUTPUT ;
    USE SIGNAL ;
    PORT
      LAYER M4 ;
        RECT  51.756 39.024 51.84 39.048 ;
    END
  END b[34]
  PIN b[35]
    DIRECTION OUTPUT ;
    USE SIGNAL ;
    PORT
      LAYER M4 ;
        RECT  51.756 39.168 51.84 39.192 ;
    END
  END b[35]
  PIN b[36]
    DIRECTION OUTPUT ;
    USE SIGNAL ;
    PORT
      LAYER M4 ;
        RECT  51.756 39.312 51.84 39.336 ;
    END
  END b[36]
  PIN b[37]
    DIRECTION OUTPUT ;
    USE SIGNAL ;
    PORT
      LAYER M4 ;
        RECT  51.756 39.456 51.84 39.48 ;
    END
  END b[37]
  PIN b[38]
    DIRECTION OUTPUT ;
    USE SIGNAL ;
    PORT
      LAYER M4 ;
        RECT  51.756 39.6 51.84 39.624 ;
    END
  END b[38]
  PIN b[39]
    DIRECTION OUTPUT ;
    USE SIGNAL ;
    PORT
      LAYER M4 ;
        RECT  51.756 39.744 51.84 39.768 ;
    END
  END b[39]
  PIN b[3]
    DIRECTION OUTPUT ;
    USE SIGNAL ;
    PORT
      LAYER M4 ;
        RECT  51.756 24.192 51.84 24.216 ;
    END
  END b[3]
  PIN b[40]
    DIRECTION OUTPUT ;
    USE SIGNAL ;
    PORT
      LAYER M4 ;
        RECT  51.756 39.888 51.84 39.912 ;
    END
  END b[40]
  PIN b[41]
    DIRECTION OUTPUT ;
    USE SIGNAL ;
    PORT
      LAYER M4 ;
        RECT  51.756 40.032 51.84 40.056 ;
    END
  END b[41]
  PIN b[42]
    DIRECTION OUTPUT ;
    USE SIGNAL ;
    PORT
      LAYER M4 ;
        RECT  51.756 40.176 51.84 40.2 ;
    END
  END b[42]
  PIN b[43]
    DIRECTION OUTPUT ;
    USE SIGNAL ;
    PORT
      LAYER M4 ;
        RECT  51.756 40.32 51.84 40.344 ;
    END
  END b[43]
  PIN b[44]
    DIRECTION OUTPUT ;
    USE SIGNAL ;
    PORT
      LAYER M4 ;
        RECT  51.756 40.464 51.84 40.488 ;
    END
  END b[44]
  PIN b[45]
    DIRECTION OUTPUT ;
    USE SIGNAL ;
    PORT
      LAYER M4 ;
        RECT  51.756 40.608 51.84 40.632 ;
    END
  END b[45]
  PIN b[46]
    DIRECTION OUTPUT ;
    USE SIGNAL ;
    PORT
      LAYER M4 ;
        RECT  51.756 40.752 51.84 40.776 ;
    END
  END b[46]
  PIN b[47]
    DIRECTION OUTPUT ;
    USE SIGNAL ;
    PORT
      LAYER M4 ;
        RECT  51.756 40.896 51.84 40.92 ;
    END
  END b[47]
  PIN b[48]
    DIRECTION OUTPUT ;
    USE SIGNAL ;
    PORT
      LAYER M4 ;
        RECT  51.756 41.04 51.84 41.064 ;
    END
  END b[48]
  PIN b[49]
    DIRECTION OUTPUT ;
    USE SIGNAL ;
    PORT
      LAYER M4 ;
        RECT  51.756 41.184 51.84 41.208 ;
    END
  END b[49]
  PIN b[4]
    DIRECTION OUTPUT ;
    USE SIGNAL ;
    PORT
      LAYER M4 ;
        RECT  51.756 24.336 51.84 24.36 ;
    END
  END b[4]
  PIN b[50]
    DIRECTION OUTPUT ;
    USE SIGNAL ;
    PORT
      LAYER M4 ;
        RECT  51.756 41.328 51.84 41.352 ;
    END
  END b[50]
  PIN b[51]
    DIRECTION OUTPUT ;
    USE SIGNAL ;
    PORT
      LAYER M4 ;
        RECT  51.756 41.472 51.84 41.496 ;
    END
  END b[51]
  PIN b[52]
    DIRECTION OUTPUT ;
    USE SIGNAL ;
    PORT
      LAYER M4 ;
        RECT  51.756 41.616 51.84 41.64 ;
    END
  END b[52]
  PIN b[53]
    DIRECTION OUTPUT ;
    USE SIGNAL ;
    PORT
      LAYER M4 ;
        RECT  51.756 41.76 51.84 41.784 ;
    END
  END b[53]
  PIN b[54]
    DIRECTION OUTPUT ;
    USE SIGNAL ;
    PORT
      LAYER M4 ;
        RECT  51.756 41.904 51.84 41.928 ;
    END
  END b[54]
  PIN b[55]
    DIRECTION OUTPUT ;
    USE SIGNAL ;
    PORT
      LAYER M4 ;
        RECT  51.756 42.048 51.84 42.072 ;
    END
  END b[55]
  PIN b[56]
    DIRECTION OUTPUT ;
    USE SIGNAL ;
    PORT
      LAYER M4 ;
        RECT  51.756 42.192 51.84 42.216 ;
    END
  END b[56]
  PIN b[57]
    DIRECTION OUTPUT ;
    USE SIGNAL ;
    PORT
      LAYER M4 ;
        RECT  51.756 42.336 51.84 42.36 ;
    END
  END b[57]
  PIN b[58]
    DIRECTION OUTPUT ;
    USE SIGNAL ;
    PORT
      LAYER M4 ;
        RECT  51.756 42.48 51.84 42.504 ;
    END
  END b[58]
  PIN b[59]
    DIRECTION OUTPUT ;
    USE SIGNAL ;
    PORT
      LAYER M4 ;
        RECT  51.756 42.624 51.84 42.648 ;
    END
  END b[59]
  PIN b[5]
    DIRECTION OUTPUT ;
    USE SIGNAL ;
    PORT
      LAYER M4 ;
        RECT  51.756 24.48 51.84 24.504 ;
    END
  END b[5]
  PIN b[60]
    DIRECTION OUTPUT ;
    USE SIGNAL ;
    PORT
      LAYER M4 ;
        RECT  51.756 42.768 51.84 42.792 ;
    END
  END b[60]
  PIN b[61]
    DIRECTION OUTPUT ;
    USE SIGNAL ;
    PORT
      LAYER M4 ;
        RECT  51.756 42.912 51.84 42.936 ;
    END
  END b[61]
  PIN b[62]
    DIRECTION OUTPUT ;
    USE SIGNAL ;
    PORT
      LAYER M4 ;
        RECT  51.756 43.056 51.84 43.08 ;
    END
  END b[62]
  PIN b[63]
    DIRECTION OUTPUT ;
    USE SIGNAL ;
    PORT
      LAYER M4 ;
        RECT  51.756 43.2 51.84 43.224 ;
    END
  END b[63]
  PIN b[64]
    DIRECTION OUTPUT ;
    USE SIGNAL ;
    PORT
      LAYER M4 ;
        RECT  51.756 34.128 51.84 34.152 ;
    END
  END b[64]
  PIN b[65]
    DIRECTION OUTPUT ;
    USE SIGNAL ;
    PORT
      LAYER M4 ;
        RECT  51.756 34.272 51.84 34.296 ;
    END
  END b[65]
  PIN b[66]
    DIRECTION OUTPUT ;
    USE SIGNAL ;
    PORT
      LAYER M4 ;
        RECT  51.756 34.416 51.84 34.44 ;
    END
  END b[66]
  PIN b[67]
    DIRECTION OUTPUT ;
    USE SIGNAL ;
    PORT
      LAYER M4 ;
        RECT  51.756 34.56 51.84 34.584 ;
    END
  END b[67]
  PIN b[68]
    DIRECTION OUTPUT ;
    USE SIGNAL ;
    PORT
      LAYER M4 ;
        RECT  51.756 34.704 51.84 34.728 ;
    END
  END b[68]
  PIN b[69]
    DIRECTION OUTPUT ;
    USE SIGNAL ;
    PORT
      LAYER M4 ;
        RECT  51.756 34.848 51.84 34.872 ;
    END
  END b[69]
  PIN b[6]
    DIRECTION OUTPUT ;
    USE SIGNAL ;
    PORT
      LAYER M4 ;
        RECT  51.756 24.624 51.84 24.648 ;
    END
  END b[6]
  PIN b[70]
    DIRECTION OUTPUT ;
    USE SIGNAL ;
    PORT
      LAYER M4 ;
        RECT  51.756 34.992 51.84 35.016 ;
    END
  END b[70]
  PIN b[71]
    DIRECTION OUTPUT ;
    USE SIGNAL ;
    PORT
      LAYER M4 ;
        RECT  51.756 35.136 51.84 35.16 ;
    END
  END b[71]
  PIN b[72]
    DIRECTION OUTPUT ;
    USE SIGNAL ;
    PORT
      LAYER M4 ;
        RECT  51.756 35.28 51.84 35.304 ;
    END
  END b[72]
  PIN b[73]
    DIRECTION OUTPUT ;
    USE SIGNAL ;
    PORT
      LAYER M4 ;
        RECT  51.756 35.424 51.84 35.448 ;
    END
  END b[73]
  PIN b[74]
    DIRECTION OUTPUT ;
    USE SIGNAL ;
    PORT
      LAYER M4 ;
        RECT  51.756 35.568 51.84 35.592 ;
    END
  END b[74]
  PIN b[75]
    DIRECTION OUTPUT ;
    USE SIGNAL ;
    PORT
      LAYER M4 ;
        RECT  51.756 35.712 51.84 35.736 ;
    END
  END b[75]
  PIN b[76]
    DIRECTION OUTPUT ;
    USE SIGNAL ;
    PORT
      LAYER M4 ;
        RECT  51.756 35.856 51.84 35.88 ;
    END
  END b[76]
  PIN b[77]
    DIRECTION OUTPUT ;
    USE SIGNAL ;
    PORT
      LAYER M4 ;
        RECT  51.756 36 51.84 36.024 ;
    END
  END b[77]
  PIN b[78]
    DIRECTION OUTPUT ;
    USE SIGNAL ;
    PORT
      LAYER M4 ;
        RECT  51.756 36.144 51.84 36.168 ;
    END
  END b[78]
  PIN b[79]
    DIRECTION OUTPUT ;
    USE SIGNAL ;
    PORT
      LAYER M4 ;
        RECT  51.756 36.288 51.84 36.312 ;
    END
  END b[79]
  PIN b[7]
    DIRECTION OUTPUT ;
    USE SIGNAL ;
    PORT
      LAYER M4 ;
        RECT  51.756 24.768 51.84 24.792 ;
    END
  END b[7]
  PIN b[80]
    DIRECTION OUTPUT ;
    USE SIGNAL ;
    PORT
      LAYER M4 ;
        RECT  51.756 36.432 51.84 36.456 ;
    END
  END b[80]
  PIN b[81]
    DIRECTION OUTPUT ;
    USE SIGNAL ;
    PORT
      LAYER M4 ;
        RECT  51.756 36.576 51.84 36.6 ;
    END
  END b[81]
  PIN b[82]
    DIRECTION OUTPUT ;
    USE SIGNAL ;
    PORT
      LAYER M4 ;
        RECT  51.756 36.72 51.84 36.744 ;
    END
  END b[82]
  PIN b[83]
    DIRECTION OUTPUT ;
    USE SIGNAL ;
    PORT
      LAYER M4 ;
        RECT  51.756 36.864 51.84 36.888 ;
    END
  END b[83]
  PIN b[84]
    DIRECTION OUTPUT ;
    USE SIGNAL ;
    PORT
      LAYER M4 ;
        RECT  51.756 37.008 51.84 37.032 ;
    END
  END b[84]
  PIN b[85]
    DIRECTION OUTPUT ;
    USE SIGNAL ;
    PORT
      LAYER M4 ;
        RECT  51.756 37.152 51.84 37.176 ;
    END
  END b[85]
  PIN b[86]
    DIRECTION OUTPUT ;
    USE SIGNAL ;
    PORT
      LAYER M4 ;
        RECT  51.756 37.296 51.84 37.32 ;
    END
  END b[86]
  PIN b[87]
    DIRECTION OUTPUT ;
    USE SIGNAL ;
    PORT
      LAYER M4 ;
        RECT  51.756 37.44 51.84 37.464 ;
    END
  END b[87]
  PIN b[88]
    DIRECTION OUTPUT ;
    USE SIGNAL ;
    PORT
      LAYER M4 ;
        RECT  51.756 37.584 51.84 37.608 ;
    END
  END b[88]
  PIN b[89]
    DIRECTION OUTPUT ;
    USE SIGNAL ;
    PORT
      LAYER M4 ;
        RECT  51.756 37.728 51.84 37.752 ;
    END
  END b[89]
  PIN b[8]
    DIRECTION OUTPUT ;
    USE SIGNAL ;
    PORT
      LAYER M4 ;
        RECT  51.756 24.912 51.84 24.936 ;
    END
  END b[8]
  PIN b[90]
    DIRECTION OUTPUT ;
    USE SIGNAL ;
    PORT
      LAYER M4 ;
        RECT  51.756 37.872 51.84 37.896 ;
    END
  END b[90]
  PIN b[91]
    DIRECTION OUTPUT ;
    USE SIGNAL ;
    PORT
      LAYER M4 ;
        RECT  51.756 38.016 51.84 38.04 ;
    END
  END b[91]
  PIN b[92]
    DIRECTION OUTPUT ;
    USE SIGNAL ;
    PORT
      LAYER M4 ;
        RECT  51.756 38.16 51.84 38.184 ;
    END
  END b[92]
  PIN b[93]
    DIRECTION OUTPUT ;
    USE SIGNAL ;
    PORT
      LAYER M4 ;
        RECT  51.756 38.304 51.84 38.328 ;
    END
  END b[93]
  PIN b[94]
    DIRECTION OUTPUT ;
    USE SIGNAL ;
    PORT
      LAYER M4 ;
        RECT  51.756 38.448 51.84 38.472 ;
    END
  END b[94]
  PIN b[95]
    DIRECTION OUTPUT ;
    USE SIGNAL ;
    PORT
      LAYER M4 ;
        RECT  51.756 38.592 51.84 38.616 ;
    END
  END b[95]
  PIN b[96]
    DIRECTION OUTPUT ;
    USE SIGNAL ;
    PORT
      LAYER M4 ;
        RECT  51.756 14.544 51.84 14.568 ;
    END
  END b[96]
  PIN b[97]
    DIRECTION OUTPUT ;
    USE SIGNAL ;
    PORT
      LAYER M4 ;
        RECT  51.756 14.688 51.84 14.712 ;
    END
  END b[97]
  PIN b[98]
    DIRECTION OUTPUT ;
    USE SIGNAL ;
    PORT
      LAYER M4 ;
        RECT  51.756 14.832 51.84 14.856 ;
    END
  END b[98]
  PIN b[99]
    DIRECTION OUTPUT ;
    USE SIGNAL ;
    PORT
      LAYER M4 ;
        RECT  51.756 14.976 51.84 15 ;
    END
  END b[99]
  PIN b[9]
    DIRECTION OUTPUT ;
    USE SIGNAL ;
    PORT
      LAYER M4 ;
        RECT  51.756 25.056 51.84 25.08 ;
    END
  END b[9]
  PIN ck
    DIRECTION INPUT ;
    USE SIGNAL ;
    PORT
      LAYER M5 ;
        RECT  16.848 0 16.872 0.084 ;
    END
  END ck
  PIN ckf
    DIRECTION INPUT ;
    USE SIGNAL ;
    PORT
      LAYER M5 ;
        RECT  16.992 0 17.016 0.084 ;
    END
  END ckf
  PIN ea
    DIRECTION INPUT ;
    USE SIGNAL ;
    PORT
      LAYER M5 ;
        RECT  17.136 0 17.16 0.084 ;
    END
  END ea
  PIN fault
    DIRECTION OUTPUT ;
    USE SIGNAL ;
    PORT
      LAYER M3 ;
        RECT  19.332 47.483 19.35 47.52 ;
    END
  END fault
  PIN k0
    DIRECTION INPUT ;
    USE SIGNAL ;
    PORT
      LAYER M5 ;
        RECT  17.28 0 17.304 0.084 ;
    END
  END k0
  PIN k1
    DIRECTION INPUT ;
    USE SIGNAL ;
    PORT
      LAYER M5 ;
        RECT  17.424 0 17.448 0.084 ;
    END
  END k1
  PIN k2
    DIRECTION INPUT ;
    USE SIGNAL ;
    PORT
      LAYER M5 ;
        RECT  17.568 0 17.592 0.084 ;
    END
  END k2
  PIN rs
    DIRECTION INPUT ;
    USE SIGNAL ;
    PORT
      LAYER M5 ;
        RECT  17.712 0 17.736 0.084 ;
    END
  END rs
  PIN tie_hi
    DIRECTION OUTPUT ;
    USE SIGNAL ;
    PORT
      LAYER M3 ;
        RECT  19.44 47.483 19.458 47.52 ;
    END
  END tie_hi
  PIN tie_lo
    DIRECTION OUTPUT ;
    USE SIGNAL ;
    PORT
      LAYER M3 ;
        RECT  19.548 47.483 19.566 47.52 ;
    END
  END tie_lo
  PIN VDD
    DIRECTION INOUT ;
    USE POWER ;
    PORT
      LAYER M5 ;
        RECT  48.492 2.151 48.612 45.369 ;
        RECT  45.792 2.151 45.912 45.369 ;
        RECT  43.092 2.151 43.212 45.369 ;
        RECT  40.392 2.151 40.512 45.369 ;
        RECT  37.692 2.151 37.812 45.369 ;
        RECT  34.992 2.151 35.112 45.369 ;
        RECT  32.292 2.151 32.412 45.369 ;
        RECT  29.592 2.151 29.712 45.369 ;
        RECT  26.892 2.151 27.012 45.369 ;
        RECT  24.192 2.151 24.312 45.369 ;
        RECT  21.492 2.151 21.612 45.369 ;
        RECT  18.792 2.151 18.912 45.369 ;
        RECT  16.092 2.151 16.212 45.369 ;
        RECT  13.392 2.151 13.512 45.369 ;
        RECT  10.692 2.151 10.812 45.369 ;
        RECT  7.992 2.151 8.112 45.369 ;
        RECT  5.292 2.151 5.412 45.369 ;
        RECT  2.592 2.151 2.712 45.369 ;
    END
  END VDD
  PIN VSS
    DIRECTION INOUT ;
    USE GROUND ;
    PORT
      LAYER M5 ;
        RECT  48.3 2.137 48.42 45.383 ;
        RECT  45.6 2.137 45.72 45.383 ;
        RECT  42.9 2.137 43.02 45.383 ;
        RECT  40.2 2.137 40.32 45.383 ;
        RECT  37.5 2.137 37.62 45.383 ;
        RECT  34.8 2.137 34.92 45.383 ;
        RECT  32.1 2.137 32.22 45.383 ;
        RECT  29.4 2.137 29.52 45.383 ;
        RECT  26.7 2.137 26.82 45.383 ;
        RECT  24 2.137 24.12 45.383 ;
        RECT  21.3 2.137 21.42 45.383 ;
        RECT  18.6 2.137 18.72 45.383 ;
        RECT  15.9 2.137 16.02 45.383 ;
        RECT  13.2 2.137 13.32 45.383 ;
        RECT  10.5 2.137 10.62 45.383 ;
        RECT  7.8 2.137 7.92 45.383 ;
        RECT  5.1 2.137 5.22 45.383 ;
        RECT  2.4 2.137 2.52 45.383 ;
    END
  END VSS
  OBS
    LAYER RVTN ;
     RECT  2.16 2.16 49.68 2.295 ;
     RECT  2.16 2.565 49.68 2.835 ;
     RECT  2.16 3.105 49.68 3.375 ;
     RECT  2.16 3.645 49.68 3.915 ;
     RECT  2.16 4.185 49.68 4.455 ;
     RECT  2.16 4.725 49.68 4.995 ;
     RECT  2.16 5.265 49.68 5.535 ;
     RECT  2.16 5.805 49.68 6.075 ;
     RECT  2.16 6.345 49.68 6.615 ;
     RECT  2.16 6.885 49.68 7.155 ;
     RECT  2.16 7.425 49.68 7.695 ;
     RECT  2.16 7.965 49.68 8.235 ;
     RECT  2.16 8.505 49.68 8.775 ;
     RECT  2.16 9.045 49.68 9.315 ;
     RECT  2.16 9.585 49.68 9.855 ;
     RECT  2.16 10.125 49.68 10.395 ;
     RECT  2.16 10.665 49.68 10.935 ;
     RECT  2.16 11.205 49.68 11.475 ;
     RECT  2.16 11.745 49.68 12.015 ;
     RECT  2.16 12.285 49.68 12.555 ;
     RECT  2.16 12.825 49.68 13.095 ;
     RECT  2.16 13.365 49.68 13.635 ;
     RECT  2.16 13.905 49.68 14.175 ;
     RECT  2.16 14.445 49.68 14.715 ;
     RECT  2.16 14.985 49.68 15.255 ;
     RECT  2.16 15.525 49.68 15.795 ;
     RECT  2.16 16.065 49.68 16.335 ;
     RECT  2.16 16.605 49.68 16.875 ;
     RECT  2.16 17.145 49.68 17.415 ;
     RECT  2.16 17.685 49.68 17.955 ;
     RECT  2.16 18.225 49.68 18.495 ;
     RECT  2.16 18.765 49.68 19.035 ;
     RECT  2.16 19.305 49.68 19.575 ;
     RECT  2.16 19.845 49.68 20.115 ;
     RECT  2.16 20.385 49.68 20.655 ;
     RECT  2.16 20.925 49.68 21.195 ;
     RECT  2.16 21.465 49.68 21.735 ;
     RECT  2.16 22.005 49.68 22.275 ;
     RECT  2.16 22.545 49.68 22.815 ;
     RECT  2.16 23.085 49.68 23.355 ;
     RECT  2.16 23.625 49.68 23.895 ;
     RECT  2.16 24.165 49.68 24.435 ;
     RECT  2.16 24.705 49.68 24.975 ;
     RECT  2.16 25.245 49.68 25.515 ;
     RECT  2.16 25.785 49.68 26.055 ;
     RECT  2.16 26.325 49.68 26.595 ;
     RECT  2.16 26.865 49.68 27.135 ;
     RECT  2.16 27.405 49.68 27.675 ;
     RECT  2.16 27.945 49.68 28.215 ;
     RECT  2.16 28.485 49.68 28.755 ;
     RECT  2.16 29.025 49.68 29.295 ;
     RECT  2.16 29.565 49.68 29.835 ;
     RECT  2.16 30.105 49.68 30.375 ;
     RECT  2.16 30.645 49.68 30.915 ;
     RECT  2.16 31.185 49.68 31.455 ;
     RECT  2.16 31.725 49.68 31.995 ;
     RECT  2.16 32.265 49.68 32.535 ;
     RECT  2.16 32.805 49.68 33.075 ;
     RECT  2.16 33.345 49.68 33.615 ;
     RECT  2.16 33.885 49.68 34.155 ;
     RECT  2.16 34.425 49.68 34.695 ;
     RECT  2.16 34.965 49.68 35.235 ;
     RECT  2.16 35.505 49.68 35.775 ;
     RECT  2.16 36.045 49.68 36.315 ;
     RECT  2.16 36.585 49.68 36.855 ;
     RECT  2.16 37.125 49.68 37.395 ;
     RECT  2.16 37.665 49.68 37.935 ;
     RECT  2.16 38.205 49.68 38.475 ;
     RECT  2.16 38.745 49.68 39.015 ;
     RECT  2.16 39.285 49.68 39.555 ;
     RECT  2.16 39.825 49.68 40.095 ;
     RECT  2.16 40.365 49.68 40.635 ;
     RECT  2.16 40.905 49.68 41.175 ;
     RECT  2.16 41.445 49.68 41.715 ;
     RECT  2.16 41.985 49.68 42.255 ;
     RECT  2.16 42.525 49.68 42.795 ;
     RECT  2.16 43.065 49.68 43.335 ;
     RECT  2.16 43.605 49.68 43.875 ;
     RECT  2.16 44.145 49.68 44.415 ;
     RECT  2.16 44.685 49.68 44.955 ;
     RECT  2.16 45.225 49.68 45.36 ;
    LAYER RVTP ;
     RECT  2.16 2.295 49.68 2.565 ;
     RECT  2.16 2.835 49.68 3.105 ;
     RECT  2.16 3.375 49.68 3.645 ;
     RECT  2.16 3.915 49.68 4.185 ;
     RECT  2.16 4.455 49.68 4.725 ;
     RECT  2.16 4.995 49.68 5.265 ;
     RECT  2.16 5.535 49.68 5.805 ;
     RECT  2.16 6.075 49.68 6.345 ;
     RECT  2.16 6.615 49.68 6.885 ;
     RECT  2.16 7.155 49.68 7.425 ;
     RECT  2.16 7.695 49.68 7.965 ;
     RECT  2.16 8.235 49.68 8.505 ;
     RECT  2.16 8.775 49.68 9.045 ;
     RECT  2.16 9.315 49.68 9.585 ;
     RECT  2.16 9.855 49.68 10.125 ;
     RECT  2.16 10.395 49.68 10.665 ;
     RECT  2.16 10.935 49.68 11.205 ;
     RECT  2.16 11.475 49.68 11.745 ;
     RECT  2.16 12.015 49.68 12.285 ;
     RECT  2.16 12.555 49.68 12.825 ;
     RECT  2.16 13.095 49.68 13.365 ;
     RECT  2.16 13.635 49.68 13.905 ;
     RECT  2.16 14.175 49.68 14.445 ;
     RECT  2.16 14.715 49.68 14.985 ;
     RECT  2.16 15.255 49.68 15.525 ;
     RECT  2.16 15.795 49.68 16.065 ;
     RECT  2.16 16.335 49.68 16.605 ;
     RECT  2.16 16.875 49.68 17.145 ;
     RECT  2.16 17.415 49.68 17.685 ;
     RECT  2.16 17.955 49.68 18.225 ;
     RECT  2.16 18.495 49.68 18.765 ;
     RECT  2.16 19.035 49.68 19.305 ;
     RECT  2.16 19.575 49.68 19.845 ;
     RECT  2.16 20.115 49.68 20.385 ;
     RECT  2.16 20.655 49.68 20.925 ;
     RECT  2.16 21.195 49.68 21.465 ;
     RECT  2.16 21.735 49.68 22.005 ;
     RECT  2.16 22.275 49.68 22.545 ;
     RECT  2.16 22.815 49.68 23.085 ;
     RECT  2.16 23.355 49.68 23.625 ;
     RECT  2.16 23.895 49.68 24.165 ;
     RECT  2.16 24.435 49.68 24.705 ;
     RECT  2.16 24.975 49.68 25.245 ;
     RECT  2.16 25.515 49.68 25.785 ;
     RECT  2.16 26.055 49.68 26.325 ;
     RECT  2.16 26.595 49.68 26.865 ;
     RECT  2.16 27.135 49.68 27.405 ;
     RECT  2.16 27.675 49.68 27.945 ;
     RECT  2.16 28.215 49.68 28.485 ;
     RECT  2.16 28.755 49.68 29.025 ;
     RECT  2.16 29.295 49.68 29.565 ;
     RECT  2.16 29.835 49.68 30.105 ;
     RECT  2.16 30.375 49.68 30.645 ;
     RECT  2.16 30.915 49.68 31.185 ;
     RECT  2.16 31.455 49.68 31.725 ;
     RECT  2.16 31.995 49.68 32.265 ;
     RECT  2.16 32.535 49.68 32.805 ;
     RECT  2.16 33.075 49.68 33.345 ;
     RECT  2.16 33.615 49.68 33.885 ;
     RECT  2.16 34.155 49.68 34.425 ;
     RECT  2.16 34.695 49.68 34.965 ;
     RECT  2.16 35.235 49.68 35.505 ;
     RECT  2.16 35.775 49.68 36.045 ;
     RECT  2.16 36.315 49.68 36.585 ;
     RECT  2.16 36.855 49.68 37.125 ;
     RECT  2.16 37.395 49.68 37.665 ;
     RECT  2.16 37.935 49.68 38.205 ;
     RECT  2.16 38.475 49.68 38.745 ;
     RECT  2.16 39.015 49.68 39.285 ;
     RECT  2.16 39.555 49.68 39.825 ;
     RECT  2.16 40.095 49.68 40.365 ;
     RECT  2.16 40.635 49.68 40.905 ;
     RECT  2.16 41.175 49.68 41.445 ;
     RECT  2.16 41.715 49.68 41.985 ;
     RECT  2.16 42.255 49.68 42.525 ;
     RECT  2.16 42.795 49.68 43.065 ;
     RECT  2.16 43.335 49.68 43.605 ;
     RECT  2.16 43.875 49.68 44.145 ;
     RECT  2.16 44.415 49.68 44.685 ;
     RECT  2.16 44.955 49.68 45.225 ;
    LAYER M1 ;
     RECT  2.16 2.151 49.68 45.369 ;
    LAYER M2 ;
     RECT  0.031 3.042 0.067 3.06 ;
     RECT  0.031 12.564 0.067 12.582 ;
     RECT  0.031 21.402 0.067 21.42 ;
     RECT  0.031 29.196 0.067 29.214 ;
     RECT  0.067 8.208 0.103 8.226 ;
     RECT  0.067 12.564 0.103 12.816 ;
     RECT  0.067 21.402 0.103 21.798 ;
     RECT  0.067 3.042 0.131 3.636 ;
     RECT  0.067 6.858 0.139 6.876 ;
     RECT  0.103 17.082 0.139 17.1 ;
     RECT  0.067 29.196 0.139 29.826 ;
     RECT  0.103 33.048 0.139 33.066 ;
     RECT  0.103 38.718 0.139 39.078 ;
     RECT  0.131 3.114 0.175 3.636 ;
     RECT  0.103 21.096 0.175 21.798 ;
     RECT  0.103 37.602 0.175 37.62 ;
     RECT  0.139 38.682 0.175 39.078 ;
     RECT  0.175 20.7 0.211 21.798 ;
     RECT  0.103 40.41 0.211 40.428 ;
     RECT  0.103 23.058 0.239 23.076 ;
     RECT  0.139 25.524 0.239 25.542 ;
     RECT  0.103 8.208 0.247 8.532 ;
     RECT  0.139 6.426 0.283 6.876 ;
     RECT  0.247 7.776 0.319 8.532 ;
     RECT  0.247 10.746 0.319 10.764 ;
     RECT  0.283 6.12 0.355 6.876 ;
     RECT  0.319 7.668 0.355 8.532 ;
     RECT  0.319 10.746 0.419 10.809 ;
     RECT  0.103 31.77 0.427 31.788 ;
     RECT  0.139 33.012 0.427 33.066 ;
     RECT  0.175 37.602 0.427 39.078 ;
     RECT  0.103 43.506 0.427 43.524 ;
     RECT  0.427 19.044 0.463 19.062 ;
     RECT  0.139 28.188 0.463 28.206 ;
     RECT  0.139 29.034 0.463 30.33 ;
     RECT  0.427 43.506 0.463 44.208 ;
     RECT  0.427 45.198 0.463 45.216 ;
     RECT  0.355 6.12 0.491 8.532 ;
     RECT  0.103 11.952 0.499 12.888 ;
     RECT  0.463 13.644 0.499 13.662 ;
     RECT  0.139 16.884 0.499 17.1 ;
     RECT  0.463 19.044 0.499 19.26 ;
     RECT  0.211 20.628 0.499 21.798 ;
     RECT  0.211 24.48 0.499 24.498 ;
     RECT  0.463 28.188 0.499 30.33 ;
     RECT  0.427 36.216 0.499 39.078 ;
     RECT  0.211 40.41 0.499 40.626 ;
     RECT  0.463 45.036 0.499 45.216 ;
     RECT  0.211 4.77 0.535 4.788 ;
     RECT  0.491 7.506 0.535 8.532 ;
     RECT  0.499 11.952 0.535 14.814 ;
     RECT  0.499 16.308 0.535 17.172 ;
     RECT  0.499 18.846 0.535 19.26 ;
     RECT  0.499 20.628 0.535 21.96 ;
     RECT  0.463 22.752 0.535 22.806 ;
     RECT  0.499 24.21 0.535 24.498 ;
     RECT  0.103 26.64 0.535 26.658 ;
     RECT  0.499 27.99 0.535 30.744 ;
     RECT  0.427 31.77 0.535 33.066 ;
     RECT  0.499 36.216 0.535 41.238 ;
     RECT  0.499 42.03 0.535 42.048 ;
     RECT  0.463 43.272 0.535 44.208 ;
     RECT  0.499 44.964 0.535 45.558 ;
     RECT  0.535 7.506 0.607 9.378 ;
     RECT  0.535 26.64 1.147 30.744 ;
     RECT  0.535 31.77 1.147 34.758 ;
     RECT  1.147 26.64 1.247 34.758 ;
     RECT  0.607 7.506 1.687 9.81 ;
     RECT  0.535 18.846 1.975 19.332 ;
     RECT  0.535 20.16 1.975 22.806 ;
     RECT  0.175 3.114 2.16 3.708 ;
     RECT  0.535 4.5 2.16 4.788 ;
     RECT  0.491 6.12 2.16 6.444 ;
     RECT  1.687 7.2 2.16 9.81 ;
     RECT  0.571 10.602 2.16 10.692 ;
     RECT  0.535 11.682 2.16 14.814 ;
     RECT  0.535 15.732 2.16 17.244 ;
     RECT  1.975 18.846 2.16 22.806 ;
     RECT  0.535 23.67 2.16 24.498 ;
     RECT  1.247 26.64 2.16 30.744 ;
     RECT  1.247 31.77 2.16 34.758 ;
     RECT  0.535 35.82 2.16 45.558 ;
     RECT  2.16 2.151 4.271 45.558 ;
     RECT  4.271 2.151 5.611 45.414 ;
     RECT  5.611 2.151 6.871 45.45 ;
     RECT  6.871 2.151 6.907 45.486 ;
     RECT  6.907 2.034 10.903 45.486 ;
     RECT  10.903 2.034 14.927 45.522 ;
     RECT  14.927 2.034 16.051 45.45 ;
     RECT  16.051 1.998 18.823 45.45 ;
     RECT  19.435 46.746 19.535 46.764 ;
     RECT  18.823 1.998 21.011 45.522 ;
     RECT  21.011 1.998 22.559 45.45 ;
     RECT  22.559 1.998 26.879 45.414 ;
     RECT  26.879 1.998 39.407 45.369 ;
     RECT  39.407 2.034 39.479 45.369 ;
     RECT  39.479 2.106 40.747 45.369 ;
     RECT  40.747 2.07 45.211 45.369 ;
     RECT  45.211 1.962 47.803 45.369 ;
     RECT  47.803 1.881 49.68 45.369 ;
     RECT  49.68 23.328 50.171 43.794 ;
     RECT  49.68 1.881 50.207 22.572 ;
     RECT  50.207 1.881 50.567 21.654 ;
     RECT  50.567 1.926 50.603 21.654 ;
     RECT  50.603 1.962 50.675 21.654 ;
     RECT  50.171 23.328 50.675 43.596 ;
     RECT  50.675 2.196 50.711 21.654 ;
     RECT  50.207 22.446 50.711 22.572 ;
     RECT  50.675 23.526 50.711 40.554 ;
     RECT  50.675 41.886 50.711 42.174 ;
     RECT  50.675 43.236 50.711 43.596 ;
     RECT  50.711 3.996 50.747 7.182 ;
     RECT  50.711 8.046 50.747 8.064 ;
     RECT  50.711 11.376 50.747 13.662 ;
     RECT  50.711 16.506 50.747 16.524 ;
     RECT  50.711 18.846 50.747 21.222 ;
     RECT  50.711 26.676 50.747 30.204 ;
     RECT  50.711 31.896 50.747 32.292 ;
     RECT  50.711 35.55 50.747 35.73 ;
     RECT  50.711 37.026 50.747 37.764 ;
     RECT  50.711 41.994 50.747 42.174 ;
     RECT  50.711 43.578 50.747 43.596 ;
     RECT  50.747 13.104 50.783 13.122 ;
     RECT  50.711 10.404 51.719 10.494 ;
     RECT  50.711 33.426 51.719 33.606 ;
     RECT  50.711 2.376 51.755 3.132 ;
     RECT  50.747 4.734 51.755 6.444 ;
     RECT  50.711 9.09 51.755 9.342 ;
     RECT  51.719 10.476 51.755 10.494 ;
     RECT  50.711 14.994 51.755 15.624 ;
     RECT  50.747 20.088 51.755 20.214 ;
     RECT  50.711 22.554 51.755 22.572 ;
     RECT  50.711 23.634 51.755 25.002 ;
     RECT  50.747 26.676 51.755 28.278 ;
     RECT  50.747 32.274 51.755 32.292 ;
     RECT  51.719 33.588 51.755 33.606 ;
     RECT  50.711 34.704 51.755 34.722 ;
     RECT  50.747 35.712 51.755 35.73 ;
     RECT  50.747 41.994 51.755 42.012 ;
    LAYER M3 ;
     RECT  17.028 0.043 17.046 0.523 ;
     RECT  16.452 0.523 17.046 0.571 ;
     RECT  50.148 0.715 50.166 0.859 ;
     RECT  50.148 0.859 50.706 1.003 ;
     RECT  16.452 0.571 17.082 1.147 ;
     RECT  16.452 1.147 17.19 1.819 ;
     RECT  49.572 1.003 50.706 1.921 ;
     RECT  16.452 1.819 17.802 1.993 ;
     RECT  45.216 1.957 45.234 1.993 ;
     RECT  47.808 1.876 47.826 1.993 ;
     RECT  49.248 1.921 50.706 2.011 ;
     RECT  39.384 1.993 39.402 2.029 ;
     RECT  47.592 1.993 47.826 2.029 ;
     RECT  39.384 2.029 39.474 2.065 ;
     RECT  47.592 2.029 48.294 2.065 ;
     RECT  40.752 2.065 40.77 2.101 ;
     RECT  43.956 1.723 43.974 2.101 ;
     RECT  45.216 1.993 45.378 2.101 ;
     RECT  47.52 2.065 48.294 2.101 ;
     RECT  49.212 2.011 50.706 2.101 ;
     RECT  47.52 2.101 50.706 2.129 ;
     RECT  16.056 1.993 17.802 2.143 ;
     RECT  40.68 2.101 41.454 2.143 ;
     RECT  45.216 2.101 45.558 2.143 ;
     RECT  13.215 2.143 13.305 2.191 ;
     RECT  20.124 2.065 20.142 2.191 ;
     RECT  46.584 2.065 46.602 2.219 ;
     RECT  50.508 2.129 50.706 2.219 ;
     RECT  10.515 2.143 10.605 2.227 ;
     RECT  15.915 2.143 17.802 2.227 ;
     RECT  18.615 2.143 18.705 2.227 ;
     RECT  39.348 2.065 39.474 2.227 ;
     RECT  45.216 2.143 45.705 2.227 ;
     RECT  5.115 2.143 5.205 2.251 ;
     RECT  13.215 2.191 13.662 2.263 ;
     RECT  42.588 2.101 44.01 2.263 ;
     RECT  47.52 2.129 49.626 2.263 ;
     RECT  9.972 2.227 10.605 2.285 ;
     RECT  14.94 2.065 14.958 2.29 ;
     RECT  5.115 2.251 5.814 2.299 ;
     RECT  6.912 2.029 6.93 2.299 ;
     RECT  8.82 2.263 8.838 2.299 ;
     RECT  10.26 2.285 10.605 2.299 ;
     RECT  11.592 2.101 11.61 2.299 ;
     RECT  42.372 2.263 44.01 2.299 ;
     RECT  45.216 2.227 46.458 2.299 ;
     RECT  51.732 2.155 51.75 2.299 ;
     RECT  8.748 2.299 8.838 2.335 ;
     RECT  12.924 2.263 13.662 2.335 ;
     RECT  14.904 2.29 14.958 2.335 ;
     RECT  15.915 2.227 18.705 2.335 ;
     RECT  38.952 2.227 39.474 2.335 ;
     RECT  40.215 2.143 41.454 2.335 ;
     RECT  42.192 2.299 44.01 2.335 ;
     RECT  24.015 2.143 24.105 2.347 ;
     RECT  5.115 2.299 5.994 2.371 ;
     RECT  6.804 2.299 6.93 2.371 ;
     RECT  7.815 2.143 7.905 2.371 ;
     RECT  34.815 2.143 34.905 2.395 ;
     RECT  2.415 2.143 2.505 2.413 ;
     RECT  5.115 2.371 7.905 2.413 ;
     RECT  8.748 2.335 9.054 2.413 ;
     RECT  14.616 2.335 18.705 2.413 ;
     RECT  21.315 2.143 21.405 2.413 ;
     RECT  22.284 2.335 22.374 2.413 ;
     RECT  26.715 2.143 26.805 2.413 ;
     RECT  29.415 2.143 29.505 2.413 ;
     RECT  32.115 2.143 32.205 2.413 ;
     RECT  33.084 2.371 33.174 2.413 ;
     RECT  34.236 2.395 34.905 2.413 ;
     RECT  37.515 2.143 37.605 2.413 ;
     RECT  10.26 2.299 11.61 2.461 ;
     RECT  12.384 2.335 13.662 2.461 ;
     RECT  14.616 2.413 18.897 2.461 ;
     RECT  19.944 2.191 20.142 2.461 ;
     RECT  37.515 2.413 37.797 2.461 ;
     RECT  38.952 2.335 44.01 2.461 ;
     RECT  44.82 2.299 46.458 2.461 ;
     RECT  5.115 2.413 9.054 2.488 ;
     RECT  24.015 2.347 24.498 2.488 ;
     RECT  14.616 2.461 20.142 2.491 ;
     RECT  14.616 2.491 20.25 2.497 ;
     RECT  32.115 2.413 33.174 2.497 ;
     RECT  34.236 2.413 35.097 2.497 ;
     RECT  30.636 2.497 30.726 2.539 ;
     RECT  14.472 2.497 20.25 2.561 ;
     RECT  10.26 2.461 13.662 2.569 ;
     RECT  14.472 2.561 16.578 2.569 ;
     RECT  37.515 2.461 46.458 2.569 ;
     RECT  21.315 2.413 22.374 2.605 ;
     RECT  24.015 2.488 24.534 2.605 ;
     RECT  17.316 2.561 20.25 2.641 ;
     RECT  21.24 2.605 22.374 2.641 ;
     RECT  28.548 2.371 28.638 2.641 ;
     RECT  51.696 2.299 51.75 2.669 ;
     RECT  28.512 2.641 28.638 2.731 ;
     RECT  30.6 2.539 30.726 2.731 ;
     RECT  37.008 2.569 46.458 2.731 ;
     RECT  47.268 2.263 49.626 2.765 ;
     RECT  26.715 2.413 26.997 2.767 ;
     RECT  27.9 2.731 28.638 2.767 ;
     RECT  29.415 2.413 29.697 2.767 ;
     RECT  32.115 2.497 35.097 2.767 ;
     RECT  5.115 2.488 9.522 2.803 ;
     RECT  23.472 2.605 24.534 2.839 ;
     RECT  25.884 2.533 25.902 2.839 ;
     RECT  17.316 2.641 22.374 2.875 ;
     RECT  23.472 2.839 25.902 2.875 ;
     RECT  2.415 2.413 2.697 2.911 ;
     RECT  26.715 2.767 28.638 2.911 ;
     RECT  29.415 2.767 29.754 2.911 ;
     RECT  30.492 2.731 30.726 2.911 ;
     RECT  50.508 2.219 50.634 3.001 ;
     RECT  0.108 3.019 0.126 3.037 ;
     RECT  17.316 2.875 25.902 3.037 ;
     RECT  26.715 2.911 30.978 3.037 ;
     RECT  17.316 3.037 31.05 3.067 ;
     RECT  31.932 2.767 35.097 3.067 ;
     RECT  36.54 2.731 46.458 3.109 ;
     RECT  47.268 2.765 49.122 3.109 ;
     RECT  51.732 2.669 51.75 3.137 ;
     RECT  2.415 2.911 2.862 3.163 ;
     RECT  50.508 3.001 50.706 3.163 ;
     RECT  17.316 3.067 35.097 3.271 ;
     RECT  36.54 3.109 49.122 3.299 ;
     RECT  5.04 2.803 9.522 3.307 ;
     RECT  4.572 3.307 9.522 3.341 ;
     RECT  36.54 3.299 46.386 3.379 ;
     RECT  10.26 2.569 16.578 3.415 ;
     RECT  17.316 3.271 35.694 3.415 ;
     RECT  36.504 3.379 46.386 3.415 ;
     RECT  1.404 3.307 1.422 3.451 ;
     RECT  2.304 3.163 2.862 3.451 ;
     RECT  47.232 3.299 49.122 3.479 ;
     RECT  1.404 3.451 2.862 3.541 ;
     RECT  47.304 3.479 49.122 3.569 ;
     RECT  10.26 3.415 46.386 3.577 ;
     RECT  0.036 3.037 0.126 3.595 ;
     RECT  0.036 3.595 0.162 3.613 ;
     RECT  1.404 3.541 3.33 3.613 ;
     RECT  51.66 3.451 51.678 3.677 ;
     RECT  4.572 3.341 9.234 3.685 ;
     RECT  47.376 3.569 49.122 3.685 ;
     RECT  1.404 3.613 3.366 3.721 ;
     RECT  4.32 3.685 9.234 3.721 ;
     RECT  9.972 3.577 46.386 3.749 ;
     RECT  50.184 3.163 50.706 3.749 ;
     RECT  12.42 3.749 46.386 3.839 ;
     RECT  47.376 3.685 49.338 3.839 ;
     RECT  1.404 3.721 3.438 3.847 ;
     RECT  4.248 3.721 9.234 3.847 ;
     RECT  0.036 3.613 0.558 3.883 ;
     RECT  1.404 3.847 9.234 3.883 ;
     RECT  12.42 3.839 44.37 3.965 ;
     RECT  50.22 3.749 50.706 3.991 ;
     RECT  50.22 3.991 50.742 4.061 ;
     RECT  36.468 3.965 44.37 4.109 ;
     RECT  50.22 4.061 50.706 4.289 ;
     RECT  50.652 4.289 50.706 4.379 ;
     RECT  47.376 3.839 49.266 4.415 ;
     RECT  36.648 4.109 44.37 4.451 ;
     RECT  0.036 3.883 9.234 4.507 ;
     RECT  9.972 3.749 11.358 4.507 ;
     RECT  47.376 4.415 48.597 4.621 ;
     RECT  0.036 4.507 11.358 4.649 ;
     RECT  12.42 3.965 35.694 4.657 ;
     RECT  3.888 4.649 11.358 4.693 ;
     RECT  12.348 4.657 35.694 4.693 ;
     RECT  45.108 3.839 46.242 4.693 ;
     RECT  47.124 4.621 48.597 4.693 ;
     RECT  44.928 4.693 48.597 4.793 ;
     RECT  0.036 4.649 2.934 4.829 ;
     RECT  0.036 4.829 2.826 4.955 ;
     RECT  45.615 4.793 48.597 4.991 ;
     RECT  3.888 4.693 35.694 4.999 ;
     RECT  49.608 4.603 49.698 5.026 ;
     RECT  3.888 4.999 35.91 5.035 ;
     RECT  36.648 4.451 43.902 5.035 ;
     RECT  49.608 5.026 49.734 5.323 ;
     RECT  3.888 5.035 43.902 5.341 ;
     RECT  49.608 5.323 49.806 5.431 ;
     RECT  45.615 4.991 47.466 5.459 ;
     RECT  3.888 5.341 44.802 5.503 ;
     RECT  49.32 5.431 49.806 5.531 ;
     RECT  49.716 5.531 49.806 5.567 ;
     RECT  48.315 4.991 48.597 5.575 ;
     RECT  49.788 5.567 49.806 5.639 ;
     RECT  45.615 5.459 46.422 5.693 ;
     RECT  3.816 5.503 44.802 5.729 ;
     RECT  48.315 5.575 48.762 5.729 ;
     RECT  0.036 4.955 2.79 5.737 ;
     RECT  0.036 5.737 2.898 5.755 ;
     RECT  3.816 5.729 43.866 5.755 ;
     RECT  51.732 4.459 51.75 5.755 ;
     RECT  44.604 5.729 44.802 5.837 ;
     RECT  47.16 5.459 47.466 5.881 ;
     RECT  48.315 5.729 48.69 5.881 ;
     RECT  45.615 5.693 46.278 5.971 ;
     RECT  0.036 5.755 43.866 5.999 ;
     RECT  50.688 4.379 50.706 6.043 ;
     RECT  51.696 5.755 51.75 6.179 ;
     RECT  47.16 5.881 48.69 6.269 ;
     RECT  0.036 5.999 43.614 6.413 ;
     RECT  44.856 5.971 46.278 6.421 ;
     RECT  51.732 6.179 51.75 6.449 ;
     RECT  44.856 6.421 46.386 6.619 ;
     RECT  50.148 6.043 50.706 6.619 ;
     RECT  44.388 6.619 46.386 6.691 ;
     RECT  47.16 6.269 48.597 6.691 ;
     RECT  49.608 6.619 50.742 6.763 ;
     RECT  44.388 6.691 48.597 6.845 ;
     RECT  49.5 6.763 50.742 6.845 ;
     RECT  44.388 6.845 46.53 6.853 ;
     RECT  43.92 6.853 46.53 6.881 ;
     RECT  47.34 6.845 48.597 7.231 ;
     RECT  47.34 7.231 48.69 7.259 ;
     RECT  43.92 6.881 44.226 7.349 ;
     RECT  49.608 6.845 50.742 7.349 ;
     RECT  49.608 7.349 49.626 7.373 ;
     RECT  47.88 7.259 48.69 7.385 ;
     RECT  45 6.881 46.53 7.619 ;
     RECT  45.288 7.619 46.53 7.661 ;
     RECT  48.315 7.385 48.69 7.771 ;
     RECT  0.036 6.413 43.197 7.861 ;
     RECT  48.315 7.771 48.87 7.861 ;
     RECT  48.315 7.861 49.338 7.961 ;
     RECT  45.504 7.661 46.53 8.041 ;
     RECT  50.688 7.349 50.742 8.093 ;
     RECT  45.504 8.041 46.782 8.275 ;
     RECT  45.504 8.275 47.43 8.311 ;
     RECT  48.315 7.961 48.906 8.311 ;
     RECT  50.688 8.093 50.706 8.311 ;
     RECT  45.504 8.311 48.906 8.429 ;
     RECT  0.036 7.861 43.326 8.545 ;
     RECT  0.036 8.545 43.866 8.699 ;
     RECT  45.615 8.429 48.906 8.699 ;
     RECT  48.315 8.699 48.906 8.977 ;
     RECT  48.315 8.977 49.158 9.077 ;
     RECT  50.184 8.311 50.706 9.077 ;
     RECT  45.615 8.699 47.502 9.149 ;
     RECT  51.732 9.067 51.75 9.347 ;
     RECT  44.784 9.247 44.802 9.625 ;
     RECT  44.208 9.625 44.802 9.677 ;
     RECT  0.036 8.699 43.197 9.779 ;
     RECT  48.315 9.077 48.597 9.895 ;
     RECT  12.24 9.779 43.197 9.931 ;
     RECT  44.316 9.677 44.802 10.057 ;
     RECT  45.615 9.149 47.466 10.057 ;
     RECT  51.696 9.787 51.714 10.219 ;
     RECT  44.316 10.057 47.466 10.327 ;
     RECT  48.315 9.895 48.762 10.327 ;
     RECT  51.696 10.219 51.75 10.427 ;
     RECT  12.24 9.931 43.578 10.471 ;
     RECT  44.316 10.327 48.762 10.471 ;
     RECT  51.732 10.427 51.75 10.499 ;
     RECT  12.24 10.471 48.762 10.733 ;
     RECT  48.315 10.733 48.762 10.867 ;
     RECT  49.608 9.925 49.626 10.867 ;
     RECT  12.24 10.733 47.106 10.931 ;
     RECT  48.315 10.867 49.626 10.939 ;
     RECT  50.688 9.077 50.706 10.939 ;
     RECT  0.036 9.779 11.466 10.975 ;
     RECT  0.036 10.975 11.502 11.011 ;
     RECT  12.24 10.931 43.866 11.011 ;
     RECT  48.315 10.939 50.706 11.371 ;
     RECT  48.315 11.371 50.742 11.549 ;
     RECT  0.036 11.011 43.866 11.785 ;
     RECT  44.676 10.931 47.106 11.785 ;
     RECT  48.315 11.549 49.302 11.939 ;
     RECT  0.036 11.785 47.106 12.091 ;
     RECT  48.315 11.939 49.122 12.091 ;
     RECT  0.036 12.091 47.466 12.245 ;
     RECT  1.404 12.245 47.466 12.325 ;
     RECT  48.24 12.091 49.122 12.325 ;
     RECT  1.404 12.325 49.122 12.479 ;
     RECT  1.404 12.479 47.322 12.515 ;
     RECT  0.036 12.245 0.558 12.587 ;
     RECT  1.404 12.515 27.09 12.749 ;
     RECT  27.936 12.515 47.214 12.749 ;
     RECT  27.936 12.749 43.578 12.797 ;
     RECT  0.072 12.587 0.558 12.821 ;
     RECT  48.315 12.479 49.122 12.865 ;
     RECT  1.404 12.749 3.366 13.019 ;
     RECT  48.315 12.865 49.194 13.019 ;
     RECT  50.184 11.549 50.742 13.099 ;
     RECT  0.108 12.821 0.558 13.133 ;
     RECT  50.184 13.099 50.778 13.277 ;
     RECT  27.936 12.797 43.362 13.291 ;
     RECT  44.496 12.749 47.214 13.297 ;
     RECT  48.315 13.019 48.978 13.297 ;
     RECT  4.212 12.749 27.09 13.325 ;
     RECT  22.32 13.325 27.09 13.333 ;
     RECT  27.9 13.291 43.362 13.333 ;
     RECT  50.184 13.277 50.742 13.387 ;
     RECT  4.212 13.325 21.597 13.603 ;
     RECT  22.32 13.333 43.362 13.603 ;
     RECT  50.148 13.387 50.742 13.709 ;
     RECT  22.32 13.603 43.722 13.711 ;
     RECT  44.496 13.297 48.978 13.711 ;
     RECT  1.404 13.019 2.697 13.837 ;
     RECT  3.42 13.603 21.597 13.837 ;
     RECT  22.32 13.711 48.978 13.901 ;
     RECT  48.276 13.901 48.978 13.981 ;
     RECT  1.404 13.837 21.597 14.009 ;
     RECT  22.32 13.901 47.538 14.099 ;
     RECT  48.276 13.981 49.05 14.099 ;
     RECT  0.468 13.133 0.558 14.141 ;
     RECT  22.32 14.099 47.466 14.243 ;
     RECT  3.924 14.009 21.597 14.413 ;
     RECT  22.32 14.243 44.082 14.413 ;
     RECT  0.504 14.141 0.558 14.861 ;
     RECT  45.324 14.243 47.466 14.881 ;
     RECT  48.276 14.099 48.654 14.881 ;
     RECT  0.504 14.861 0.522 15.019 ;
     RECT  1.404 14.009 3.15 15.061 ;
     RECT  3.924 14.413 44.082 15.061 ;
     RECT  45.324 14.881 48.654 15.151 ;
     RECT  1.404 15.061 44.082 15.215 ;
     RECT  39.492 15.215 44.082 15.223 ;
     RECT  39.492 15.223 44.226 15.259 ;
     RECT  44.964 15.151 48.654 15.259 ;
     RECT  50.148 13.709 50.706 15.259 ;
     RECT  39.492 15.259 48.654 15.287 ;
     RECT  39.492 15.287 46.818 15.557 ;
     RECT  49.68 15.259 50.706 15.557 ;
     RECT  51.732 14.971 51.75 15.629 ;
     RECT  0.144 15.019 0.522 15.727 ;
     RECT  47.556 15.287 48.654 15.727 ;
     RECT  47.556 15.727 49.158 15.755 ;
     RECT  47.664 15.755 49.158 15.899 ;
     RECT  1.404 15.215 38.754 15.961 ;
     RECT  39.492 15.557 46.782 15.961 ;
     RECT  50.148 15.557 50.706 16.501 ;
     RECT  48.315 15.899 49.05 16.529 ;
     RECT  50.148 16.501 50.742 16.589 ;
     RECT  1.404 15.961 46.782 16.673 ;
     RECT  26.208 16.673 46.782 16.843 ;
     RECT  48.315 16.529 48.597 16.915 ;
     RECT  26.208 16.843 46.926 16.979 ;
     RECT  50.148 16.589 50.706 17.021 ;
     RECT  0.144 15.727 0.558 17.077 ;
     RECT  0.108 17.077 0.558 17.165 ;
     RECT  26.208 16.979 46.854 17.249 ;
     RECT  47.916 16.915 48.597 17.275 ;
     RECT  0.144 17.165 0.558 17.309 ;
     RECT  44.172 17.249 46.854 17.339 ;
     RECT  1.404 16.673 25.29 17.411 ;
     RECT  47.916 17.275 49.05 17.411 ;
     RECT  0.18 17.309 0.558 17.453 ;
     RECT  9.18 17.411 25.29 17.491 ;
     RECT  26.208 17.249 43.197 17.491 ;
     RECT  47.916 17.411 48.906 17.491 ;
     RECT  0.324 17.453 0.558 17.597 ;
     RECT  46.764 17.339 46.854 17.725 ;
     RECT  47.664 17.491 48.906 17.725 ;
     RECT  0.504 17.597 0.558 17.741 ;
     RECT  0.504 17.741 0.522 17.885 ;
     RECT  46.764 17.725 48.906 17.915 ;
     RECT  44.172 17.339 46.026 17.987 ;
     RECT  50.184 17.021 50.706 18.031 ;
     RECT  47.844 17.915 48.906 18.059 ;
     RECT  9.18 17.491 43.197 18.121 ;
     RECT  44.352 17.987 46.026 18.149 ;
     RECT  47.916 18.059 48.906 18.157 ;
     RECT  49.788 18.031 50.706 18.157 ;
     RECT  44.424 18.149 46.026 18.185 ;
     RECT  1.404 17.411 8.406 18.301 ;
     RECT  9.18 18.121 43.254 18.301 ;
     RECT  44.568 18.185 46.026 18.391 ;
     RECT  46.764 17.915 46.818 18.391 ;
     RECT  44.568 18.391 46.818 18.455 ;
     RECT  47.916 18.157 50.706 18.689 ;
     RECT  49.572 18.689 50.706 18.761 ;
     RECT  0.108 18.811 0.126 18.841 ;
     RECT  49.68 18.761 50.706 18.841 ;
     RECT  47.916 18.689 48.69 19.139 ;
     RECT  0.108 18.841 0.522 19.309 ;
     RECT  44.568 18.455 46.782 19.309 ;
     RECT  0.108 19.309 0.558 19.325 ;
     RECT  49.68 18.841 50.742 19.337 ;
     RECT  1.404 18.301 43.254 19.345 ;
     RECT  44.568 19.309 47.574 19.607 ;
     RECT  50.688 19.337 50.742 19.613 ;
     RECT  48.315 19.139 48.69 19.615 ;
     RECT  49.68 19.337 49.698 19.615 ;
     RECT  1.404 19.345 43.362 19.741 ;
     RECT  44.568 19.607 47.25 19.741 ;
     RECT  1.404 19.741 47.25 19.805 ;
     RECT  48.315 19.615 49.698 19.841 ;
     RECT  2.304 19.805 47.25 19.853 ;
     RECT  44.46 19.853 47.25 19.913 ;
     RECT  51.732 19.867 51.75 20.219 ;
     RECT  48.315 19.841 49.266 20.381 ;
     RECT  44.676 19.913 47.25 20.551 ;
     RECT  50.688 19.613 50.706 20.578 ;
     RECT  44.676 20.551 47.358 20.695 ;
     RECT  48.315 20.381 48.654 20.695 ;
     RECT  50.652 20.578 50.706 20.695 ;
     RECT  1.404 19.805 1.422 20.875 ;
     RECT  2.304 19.853 43.362 20.875 ;
     RECT  44.676 20.695 48.654 20.921 ;
     RECT  49.788 20.875 49.806 21.019 ;
     RECT  50.652 20.695 50.742 21.019 ;
     RECT  1.404 20.875 43.362 21.053 ;
     RECT  0.144 19.325 0.558 21.091 ;
     RECT  2.415 21.053 43.362 21.115 ;
     RECT  49.788 21.019 50.742 21.163 ;
     RECT  0.108 21.091 0.558 21.235 ;
     RECT  1.404 21.053 1.422 21.235 ;
     RECT  44.676 20.921 48.597 21.299 ;
     RECT  49.608 21.163 50.742 21.299 ;
     RECT  50.184 21.299 50.742 21.341 ;
     RECT  0.108 21.235 1.422 21.397 ;
     RECT  48.312 21.299 48.597 21.533 ;
     RECT  2.415 21.115 43.83 21.541 ;
     RECT  44.676 21.299 47.502 21.541 ;
     RECT  2.415 21.541 47.502 21.569 ;
     RECT  50.184 21.341 50.706 21.659 ;
     RECT  48.315 21.533 48.597 21.739 ;
     RECT  49.32 21.631 49.338 21.739 ;
     RECT  2.415 21.569 47.466 21.787 ;
     RECT  50.184 21.659 50.202 22.109 ;
     RECT  2.304 21.787 47.466 22.199 ;
     RECT  2.304 22.199 43.254 22.208 ;
     RECT  43.992 22.199 47.466 22.235 ;
     RECT  48.315 21.739 49.338 22.315 ;
     RECT  0.036 21.397 1.422 22.505 ;
     RECT  51.732 22.459 51.75 22.577 ;
     RECT  2.415 22.208 43.254 22.775 ;
     RECT  48.315 22.315 49.626 22.891 ;
     RECT  43.992 22.235 47.25 23.009 ;
     RECT  43.992 23.009 47.106 23.081 ;
     RECT  44.784 23.081 47.106 23.189 ;
     RECT  9.324 22.775 43.254 23.279 ;
     RECT  48.024 22.891 49.626 23.287 ;
     RECT  50.688 22.441 50.706 23.323 ;
     RECT  26.352 23.279 43.254 23.431 ;
     RECT  43.992 23.081 44.01 23.431 ;
     RECT  47.988 23.287 49.626 23.467 ;
     RECT  2.415 22.775 8.478 23.563 ;
     RECT  47.988 23.467 49.806 23.585 ;
     RECT  2.415 23.563 8.586 23.629 ;
     RECT  9.324 23.279 25.47 23.629 ;
     RECT  49.788 23.585 49.806 23.729 ;
     RECT  26.352 23.431 44.01 23.891 ;
     RECT  47.988 23.585 48.942 23.899 ;
     RECT  50.652 23.323 50.706 23.899 ;
     RECT  47.844 23.899 48.942 23.927 ;
     RECT  50.148 23.899 50.706 23.935 ;
     RECT  50.148 23.935 50.742 23.936 ;
     RECT  44.784 23.189 47.034 23.947 ;
     RECT  47.844 23.927 48.597 23.947 ;
     RECT  39.78 23.891 44.01 23.971 ;
     RECT  44.748 23.947 48.597 23.971 ;
     RECT  39.78 23.971 48.597 23.981 ;
     RECT  2.415 23.629 25.47 24.061 ;
     RECT  26.352 23.891 38.862 24.061 ;
     RECT  50.652 23.936 50.742 24.077 ;
     RECT  44.28 23.981 48.597 24.089 ;
     RECT  44.748 24.089 48.597 24.125 ;
     RECT  2.415 24.061 25.506 24.133 ;
     RECT  26.244 24.061 38.862 24.133 ;
     RECT  50.652 24.077 50.706 24.233 ;
     RECT  2.415 24.133 38.862 24.359 ;
     RECT  44.784 24.125 48.597 24.395 ;
     RECT  39.78 23.981 43.542 24.431 ;
     RECT  10.224 24.359 38.862 24.467 ;
     RECT  49.608 24.511 49.626 24.653 ;
     RECT  48.315 24.395 48.597 24.709 ;
     RECT  2.415 24.359 9.342 24.763 ;
     RECT  48.315 24.709 49.158 24.809 ;
     RECT  39.78 24.431 43.254 24.907 ;
     RECT  44.784 24.395 47.538 25.007 ;
     RECT  51.732 23.611 51.75 25.007 ;
     RECT  2.304 24.763 9.342 25.213 ;
     RECT  10.224 24.467 38.79 25.213 ;
     RECT  39.708 24.907 43.254 25.213 ;
     RECT  47.016 25.007 47.538 25.213 ;
     RECT  48.315 24.809 48.597 25.213 ;
     RECT  50.688 24.233 50.706 25.249 ;
     RECT  50.652 25.249 50.706 25.411 ;
     RECT  2.304 25.213 43.254 25.439 ;
     RECT  44.784 25.007 46.134 25.483 ;
     RECT  44.208 25.483 46.134 25.591 ;
     RECT  44.1 25.591 46.134 25.825 ;
     RECT  47.016 25.213 48.597 25.825 ;
     RECT  2.304 25.439 9.414 25.915 ;
     RECT  50.148 25.411 50.706 25.951 ;
     RECT  44.1 25.825 48.597 25.987 ;
     RECT  50.112 25.951 50.706 26.159 ;
     RECT  44.064 25.987 48.597 26.221 ;
     RECT  2.268 25.915 9.414 26.285 ;
     RECT  43.956 26.221 48.654 26.293 ;
     RECT  2.304 26.285 9.414 26.365 ;
     RECT  10.224 25.439 43.197 26.365 ;
     RECT  49.608 26.347 49.626 27.067 ;
     RECT  50.688 26.159 50.706 27.067 ;
     RECT  2.304 26.365 43.197 27.139 ;
     RECT  43.956 26.293 48.834 27.139 ;
     RECT  49.608 27.067 50.706 27.139 ;
     RECT  2.304 27.139 50.706 27.245 ;
     RECT  2.304 27.245 49.014 27.329 ;
     RECT  50.148 27.245 50.706 27.337 ;
     RECT  2.304 27.329 47.034 27.473 ;
     RECT  0.036 22.505 0.846 27.715 ;
     RECT  47.772 27.329 49.014 27.869 ;
     RECT  50.148 27.337 50.742 27.965 ;
     RECT  44.64 27.473 47.034 28.139 ;
     RECT  47.772 27.869 48.762 28.139 ;
     RECT  2.304 27.473 43.794 28.255 ;
     RECT  51.732 26.491 51.75 28.283 ;
     RECT  45.036 28.139 47.034 28.319 ;
     RECT  2.304 28.255 43.83 28.409 ;
     RECT  45.612 28.319 47.034 28.459 ;
     RECT  47.772 28.139 48.597 28.459 ;
     RECT  30.564 28.409 43.83 28.493 ;
     RECT  30.636 28.493 43.83 28.651 ;
     RECT  2.304 28.409 29.826 28.679 ;
     RECT  49.32 28.651 49.374 28.939 ;
     RECT  50.148 27.965 50.706 28.939 ;
     RECT  49.32 28.939 50.706 28.957 ;
     RECT  45.612 28.459 48.597 28.985 ;
     RECT  49.32 28.957 50.742 28.985 ;
     RECT  45.612 28.985 47.502 29.021 ;
     RECT  49.86 28.985 50.742 29.057 ;
     RECT  30.636 28.651 44.226 29.065 ;
     RECT  45.612 29.021 47.25 29.065 ;
     RECT  30.636 29.065 47.25 29.093 ;
     RECT  14.688 28.679 29.826 29.191 ;
     RECT  0.036 27.715 1.458 29.219 ;
     RECT  44.928 29.093 47.25 29.261 ;
     RECT  50.148 29.057 50.742 29.261 ;
     RECT  2.304 28.679 13.914 29.264 ;
     RECT  14.688 29.191 29.898 29.323 ;
     RECT  30.636 29.093 43.902 29.323 ;
     RECT  2.376 29.264 13.914 29.569 ;
     RECT  14.688 29.323 43.902 29.569 ;
     RECT  0.072 29.219 1.458 29.831 ;
     RECT  45.144 29.261 47.25 29.839 ;
     RECT  45.144 29.839 47.466 29.903 ;
     RECT  2.376 29.569 43.902 30.065 ;
     RECT  50.688 29.261 50.742 30.091 ;
     RECT  48.315 28.985 48.597 30.145 ;
     RECT  50.148 30.091 50.742 30.269 ;
     RECT  48.315 30.145 48.942 30.271 ;
     RECT  48.24 30.271 48.942 30.371 ;
     RECT  0.108 29.831 1.458 30.413 ;
     RECT  45.144 29.903 45.897 30.451 ;
     RECT  46.764 29.903 47.466 30.685 ;
     RECT  48.315 30.371 48.942 30.685 ;
     RECT  44.856 30.451 45.897 30.811 ;
     RECT  50.148 30.269 50.706 30.845 ;
     RECT  2.415 30.065 43.902 30.847 ;
     RECT  44.856 30.811 45.954 30.847 ;
     RECT  46.728 30.685 47.466 30.847 ;
     RECT  2.415 30.847 47.466 30.911 ;
     RECT  48.315 30.685 49.23 30.955 ;
     RECT  48.315 30.955 49.266 30.991 ;
     RECT  0.144 30.413 1.458 31.133 ;
     RECT  48.315 30.991 49.41 31.261 ;
     RECT  0.144 31.133 1.242 31.277 ;
     RECT  1.152 31.277 1.242 31.334 ;
     RECT  8.892 30.911 47.466 31.387 ;
     RECT  48.276 31.261 49.41 31.387 ;
     RECT  8.892 31.387 49.41 31.415 ;
     RECT  47.592 31.415 49.41 31.459 ;
     RECT  1.224 31.334 1.242 31.565 ;
     RECT  47.592 31.459 49.626 31.565 ;
     RECT  2.415 30.911 8.097 31.693 ;
     RECT  8.892 31.415 46.818 31.693 ;
     RECT  47.592 31.565 49.23 31.709 ;
     RECT  0.144 31.277 0.162 31.765 ;
     RECT  50.688 30.845 50.706 31.801 ;
     RECT  50.184 31.801 50.706 31.891 ;
     RECT  2.415 31.693 46.818 32.063 ;
     RECT  47.592 31.709 49.194 32.063 ;
     RECT  50.184 31.891 50.742 32.141 ;
     RECT  18.072 32.063 46.818 32.225 ;
     RECT  0.108 31.765 0.162 32.269 ;
     RECT  0.108 32.269 0.45 32.285 ;
     RECT  51.732 32.251 51.75 32.297 ;
     RECT  50.184 32.141 50.706 32.395 ;
     RECT  18.072 32.225 43.506 32.459 ;
     RECT  0.18 32.285 0.45 32.467 ;
     RECT  18.072 32.459 43.434 32.495 ;
     RECT  47.592 32.063 48.597 32.495 ;
     RECT  44.676 32.225 46.818 32.611 ;
     RECT  2.415 32.063 17.226 32.683 ;
     RECT  50.148 32.395 50.706 32.729 ;
     RECT  2.304 32.683 17.226 33.005 ;
     RECT  0.18 32.467 0.558 33.007 ;
     RECT  50.148 32.729 50.238 33.008 ;
     RECT  0.144 33.007 0.558 33.043 ;
     RECT  2.415 33.005 17.226 33.079 ;
     RECT  18.072 32.495 20.034 33.079 ;
     RECT  0.108 33.043 0.558 33.149 ;
     RECT  2.415 33.079 20.034 33.385 ;
     RECT  51.732 33.259 51.75 33.403 ;
     RECT  44.676 32.611 46.926 33.421 ;
     RECT  51.696 33.403 51.75 33.449 ;
     RECT  21.096 32.495 43.434 33.511 ;
     RECT  48.315 32.495 48.597 33.511 ;
     RECT  2.415 33.385 20.07 33.539 ;
     RECT  47.844 33.511 48.597 33.547 ;
     RECT  49.572 33.115 49.59 33.547 ;
     RECT  44.676 33.421 47.034 33.584 ;
     RECT  11.808 33.539 20.07 33.598 ;
     RECT  47.844 33.547 49.59 33.611 ;
     RECT  51.732 33.449 51.75 33.611 ;
     RECT  0.144 33.149 0.558 33.725 ;
     RECT  11.844 33.598 20.07 33.781 ;
     RECT  20.988 33.511 43.434 33.781 ;
     RECT  48.315 33.611 49.59 33.809 ;
     RECT  2.415 33.539 3.366 33.925 ;
     RECT  44.892 33.584 47.034 33.925 ;
     RECT  49.572 33.809 49.59 33.925 ;
     RECT  11.844 33.781 43.434 33.961 ;
     RECT  49.572 33.925 49.662 33.989 ;
     RECT  49.644 33.989 49.662 34.013 ;
     RECT  44.892 33.925 47.106 34.027 ;
     RECT  11.844 33.961 44.046 34.079 ;
     RECT  0.18 33.725 0.558 34.157 ;
     RECT  11.844 34.079 39.078 34.157 ;
     RECT  50.688 33.547 50.706 34.267 ;
     RECT  2.304 33.925 3.366 34.321 ;
     RECT  20.448 34.157 39.078 34.349 ;
     RECT  2.304 34.321 3.402 34.393 ;
     RECT  4.68 33.539 10.998 34.393 ;
     RECT  2.268 34.393 10.998 34.411 ;
     RECT  11.844 34.157 19.71 34.411 ;
     RECT  39.96 34.079 44.046 34.429 ;
     RECT  39.96 34.429 44.118 34.501 ;
     RECT  44.892 34.027 47.466 34.501 ;
     RECT  2.268 34.411 19.71 34.589 ;
     RECT  50.148 34.267 50.706 34.619 ;
     RECT  51.732 34.555 51.75 34.727 ;
     RECT  0.54 34.157 0.558 34.877 ;
     RECT  20.484 34.349 39.078 34.897 ;
     RECT  39.96 34.501 47.466 34.897 ;
     RECT  20.484 34.897 47.574 34.925 ;
     RECT  44.712 34.925 47.574 35.005 ;
     RECT  48.315 33.809 48.597 35.005 ;
     RECT  44.712 35.005 48.798 35.159 ;
     RECT  47.412 35.159 47.574 35.195 ;
     RECT  44.712 35.159 46.386 35.303 ;
     RECT  49.608 34.771 49.626 35.419 ;
     RECT  50.436 34.619 50.706 35.419 ;
     RECT  49.608 35.419 50.706 35.501 ;
     RECT  44.712 35.303 46.206 35.537 ;
     RECT  2.304 34.589 19.71 35.545 ;
     RECT  20.484 34.925 43.902 35.545 ;
     RECT  48.315 35.159 48.798 35.545 ;
     RECT  49.608 35.501 49.878 35.545 ;
     RECT  50.652 35.501 50.706 35.545 ;
     RECT  2.304 35.545 43.902 35.609 ;
     RECT  12.24 35.609 43.902 35.699 ;
     RECT  33.192 35.699 43.902 35.707 ;
     RECT  44.712 35.537 44.73 35.707 ;
     RECT  51.732 35.563 51.75 35.735 ;
     RECT  50.652 35.545 50.742 35.741 ;
     RECT  33.192 35.707 44.73 35.879 ;
     RECT  33.192 35.879 43.974 35.969 ;
     RECT  47.412 35.195 47.466 36.049 ;
     RECT  2.304 35.609 11.502 36.173 ;
     RECT  0.54 35.815 0.558 36.211 ;
     RECT  48.315 35.545 49.878 36.283 ;
     RECT  50.652 35.741 50.706 36.283 ;
     RECT  2.415 36.173 11.502 36.355 ;
     RECT  12.24 35.699 32.397 36.355 ;
     RECT  2.415 36.355 32.397 36.517 ;
     RECT  33.192 35.969 43.65 36.517 ;
     RECT  47.016 36.049 47.466 36.545 ;
     RECT  45.615 35.537 46.206 36.589 ;
     RECT  48.315 36.283 50.706 36.589 ;
     RECT  44.712 35.879 44.73 36.661 ;
     RECT  45.615 36.589 46.746 36.661 ;
     RECT  47.988 36.589 50.706 36.815 ;
     RECT  2.415 36.517 43.65 36.887 ;
     RECT  0.432 36.211 0.558 36.907 ;
     RECT  11.808 36.887 43.65 36.931 ;
     RECT  44.712 36.661 46.746 36.931 ;
     RECT  48.06 36.815 50.706 36.959 ;
     RECT  50.148 36.959 50.706 37.021 ;
     RECT  2.415 36.887 11.034 37.049 ;
     RECT  2.415 37.049 10.89 37.057 ;
     RECT  11.808 36.931 46.746 37.091 ;
     RECT  48.06 36.959 49.302 37.121 ;
     RECT  2.268 37.057 10.89 37.229 ;
     RECT  2.268 37.229 10.854 37.325 ;
     RECT  30.708 37.091 46.746 37.327 ;
     RECT  50.148 37.021 50.742 37.328 ;
     RECT  0.144 36.907 0.558 37.597 ;
     RECT  11.808 37.091 29.898 37.625 ;
     RECT  30.708 37.327 46.782 37.627 ;
     RECT  11.808 37.625 16.326 37.633 ;
     RECT  30.708 37.627 46.854 37.669 ;
     RECT  30.708 37.669 46.89 37.705 ;
     RECT  0.108 37.597 0.558 37.741 ;
     RECT  30.708 37.705 46.962 37.741 ;
     RECT  11.664 37.633 16.326 37.831 ;
     RECT  0.108 37.741 0.63 37.859 ;
     RECT  30.708 37.741 47.034 37.867 ;
     RECT  48.096 37.121 49.302 37.867 ;
     RECT  17.172 37.625 29.898 37.903 ;
     RECT  30.708 37.867 47.106 37.903 ;
     RECT  2.415 37.325 10.854 38.005 ;
     RECT  11.628 37.831 16.326 38.005 ;
     RECT  50.688 37.328 50.742 38.045 ;
     RECT  17.172 37.903 47.106 38.101 ;
     RECT  48.024 37.867 49.302 38.101 ;
     RECT  50.688 38.045 50.706 38.155 ;
     RECT  50.148 38.155 50.706 38.201 ;
     RECT  17.172 38.101 49.302 38.281 ;
     RECT  17.172 38.281 49.662 38.371 ;
     RECT  2.415 38.005 16.326 38.407 ;
     RECT  17.064 38.371 49.662 38.407 ;
     RECT  2.415 38.407 49.662 38.515 ;
     RECT  2.304 38.515 49.662 38.669 ;
     RECT  2.304 38.669 43.434 38.813 ;
     RECT  44.46 38.669 49.662 38.849 ;
     RECT  2.304 38.813 14.706 38.939 ;
     RECT  48.024 38.849 49.662 39.019 ;
     RECT  50.688 38.201 50.706 39.019 ;
     RECT  15.444 38.813 43.434 39.209 ;
     RECT  48.024 39.019 50.706 39.479 ;
     RECT  0.108 37.859 0.558 39.485 ;
     RECT  48.024 39.479 48.597 39.595 ;
     RECT  47.7 39.595 48.597 39.631 ;
     RECT  2.304 38.939 14.634 39.721 ;
     RECT  15.444 39.209 38.214 39.721 ;
     RECT  44.46 38.849 46.89 39.721 ;
     RECT  47.628 39.631 48.597 39.721 ;
     RECT  2.304 39.721 38.214 39.773 ;
     RECT  49.608 39.479 50.706 39.857 ;
     RECT  2.415 39.773 38.214 39.991 ;
     RECT  38.988 39.209 43.434 39.991 ;
     RECT  51.66 39.883 51.678 40.013 ;
     RECT  44.46 39.721 48.597 40.019 ;
     RECT  49.608 39.857 49.806 40.349 ;
     RECT  0.504 39.485 0.558 40.363 ;
     RECT  0.144 40.363 0.558 40.405 ;
     RECT  49.788 40.349 49.806 40.469 ;
     RECT  50.616 39.857 50.706 40.603 ;
     RECT  0.108 40.405 0.558 40.637 ;
     RECT  2.415 39.991 43.434 40.675 ;
     RECT  44.496 40.019 47.502 40.703 ;
     RECT  44.748 40.703 47.502 40.739 ;
     RECT  47.34 40.739 47.502 40.829 ;
     RECT  48.276 40.019 48.597 40.829 ;
     RECT  50.148 40.603 50.706 40.829 ;
     RECT  2.304 40.675 43.434 40.925 ;
     RECT  44.748 40.739 46.422 40.973 ;
     RECT  2.415 40.925 43.434 41.107 ;
     RECT  48.315 40.829 48.597 41.251 ;
     RECT  44.748 40.973 46.278 41.485 ;
     RECT  48.315 41.251 48.798 41.485 ;
     RECT  44.46 41.485 46.278 41.513 ;
     RECT  2.415 41.107 43.578 41.611 ;
     RECT  44.46 41.513 46.242 41.611 ;
     RECT  47.34 40.829 47.43 41.611 ;
     RECT  2.415 41.611 46.242 41.639 ;
     RECT  2.415 41.639 17.37 41.683 ;
     RECT  47.268 41.611 47.43 41.683 ;
     RECT  48.315 41.485 49.158 41.683 ;
     RECT  47.268 41.683 49.158 41.747 ;
     RECT  2.304 41.683 17.37 41.789 ;
     RECT  49.32 41.791 49.338 41.899 ;
     RECT  50.184 40.829 50.706 41.899 ;
     RECT  47.268 41.747 48.597 41.917 ;
     RECT  51.732 41.467 51.75 42.017 ;
     RECT  2.304 41.789 2.697 42.077 ;
     RECT  49.32 41.899 50.706 42.089 ;
     RECT  50.184 42.089 50.706 42.151 ;
     RECT  18.18 41.639 46.242 42.259 ;
     RECT  47.052 41.917 48.597 42.259 ;
     RECT  3.456 41.789 17.37 42.427 ;
     RECT  18.18 42.259 48.597 42.427 ;
     RECT  3.456 42.427 48.597 42.509 ;
     RECT  46.944 42.509 48.597 42.529 ;
     RECT  49.32 42.089 49.338 42.529 ;
     RECT  50.184 42.151 50.742 42.907 ;
     RECT  50.148 42.907 50.742 42.961 ;
     RECT  3.456 42.509 46.206 43.025 ;
     RECT  46.944 42.529 49.338 43.069 ;
     RECT  50.112 42.961 50.742 43.069 ;
     RECT  44.388 43.025 46.206 43.097 ;
     RECT  46.944 43.069 50.742 43.229 ;
     RECT  3.456 43.025 43.614 43.259 ;
     RECT  44.424 43.097 46.206 43.259 ;
     RECT  44.46 43.259 46.206 43.267 ;
     RECT  46.944 43.229 49.302 43.267 ;
     RECT  36.036 43.259 43.614 43.295 ;
     RECT  44.46 43.267 49.302 43.295 ;
     RECT  36.036 43.295 43.578 43.376 ;
     RECT  0.144 40.637 0.558 43.483 ;
     RECT  0.108 43.483 0.558 43.529 ;
     RECT  44.46 43.295 48.597 43.565 ;
     RECT  50.148 43.229 50.742 43.601 ;
     RECT  44.46 43.565 47.25 43.637 ;
     RECT  2.415 42.077 2.697 43.645 ;
     RECT  3.456 43.259 35.097 43.645 ;
     RECT  44.46 43.637 46.458 43.799 ;
     RECT  50.148 43.601 50.166 43.799 ;
     RECT  45.615 43.799 46.458 43.835 ;
     RECT  47.232 43.637 47.25 43.835 ;
     RECT  2.415 43.645 35.097 43.901 ;
     RECT  36.036 43.376 43.197 44.069 ;
     RECT  36.036 44.069 41.202 44.105 ;
     RECT  42.084 44.069 43.197 44.141 ;
     RECT  0.144 43.529 0.558 44.189 ;
     RECT  44.46 43.799 44.478 44.213 ;
     RECT  22.5 43.901 35.097 44.311 ;
     RECT  2.415 43.901 21.726 44.339 ;
     RECT  42.12 44.141 43.197 44.339 ;
     RECT  2.415 44.339 21.654 44.375 ;
     RECT  22.5 44.311 35.658 44.375 ;
     RECT  36.504 44.105 41.094 44.381 ;
     RECT  34.524 44.375 35.658 44.447 ;
     RECT  39.96 44.381 41.094 44.447 ;
     RECT  2.415 44.375 21.597 44.477 ;
     RECT  36.504 44.381 39.186 44.477 ;
     RECT  36.504 44.477 39.078 44.609 ;
     RECT  40.215 44.447 40.734 44.609 ;
     RECT  42.156 44.339 43.197 44.609 ;
     RECT  22.824 44.375 33.282 44.645 ;
     RECT  34.524 44.447 35.097 44.645 ;
     RECT  40.215 44.609 40.554 44.645 ;
     RECT  2.415 44.477 11.358 44.753 ;
     RECT  36.504 44.609 36.522 44.753 ;
     RECT  0.432 44.189 0.558 44.761 ;
     RECT  0.432 44.761 0.594 44.813 ;
     RECT  6.516 44.753 11.358 44.879 ;
     RECT  29.415 44.645 33.282 44.879 ;
     RECT  38.772 44.609 39.078 44.879 ;
     RECT  22.824 44.645 28.386 44.915 ;
     RECT  31.68 44.879 33.174 44.915 ;
     RECT  37.476 44.609 37.797 44.915 ;
     RECT  42.192 44.609 43.197 44.915 ;
     RECT  39.06 44.879 39.078 44.951 ;
     RECT  23.868 44.915 28.386 44.987 ;
     RECT  6.516 44.879 8.73 45.023 ;
     RECT  12.528 44.477 21.597 45.023 ;
     RECT  2.415 44.753 5.706 45.059 ;
     RECT  12.528 45.023 20.106 45.059 ;
     RECT  20.916 45.023 21.597 45.107 ;
     RECT  34.815 44.645 35.097 45.107 ;
     RECT  37.515 44.915 37.797 45.107 ;
     RECT  40.215 44.645 40.497 45.107 ;
     RECT  42.915 44.915 43.197 45.107 ;
     RECT  45.615 43.835 45.897 45.107 ;
     RECT  48.315 43.565 48.597 45.107 ;
     RECT  2.415 45.059 4.338 45.149 ;
     RECT  6.516 45.023 8.37 45.149 ;
     RECT  9.54 44.879 10.998 45.149 ;
     RECT  13.104 45.059 20.106 45.149 ;
     RECT  23.868 44.987 28.098 45.149 ;
     RECT  29.415 44.879 30.942 45.149 ;
     RECT  32.076 44.915 33.174 45.149 ;
     RECT  6.84 45.149 7.905 45.185 ;
     RECT  9.54 45.149 9.558 45.185 ;
     RECT  13.215 45.149 14.922 45.185 ;
     RECT  20.916 45.107 21.405 45.185 ;
     RECT  23.868 45.149 25.254 45.185 ;
     RECT  29.415 45.149 30.006 45.185 ;
     RECT  30.852 45.149 30.942 45.185 ;
     RECT  32.115 45.149 33.03 45.185 ;
     RECT  18.504 45.149 20.106 45.197 ;
     RECT  27.612 45.149 28.098 45.221 ;
     RECT  15.912 45.149 16.005 45.245 ;
     RECT  17.208 45.149 17.226 45.245 ;
     RECT  0.432 44.813 0.558 45.259 ;
     RECT  22.824 44.915 22.95 45.265 ;
     RECT  2.415 45.149 4.266 45.293 ;
     RECT  10.332 45.149 10.998 45.293 ;
     RECT  13.215 45.185 13.806 45.293 ;
     RECT  22.32 45.265 22.95 45.293 ;
     RECT  23.868 45.185 24.822 45.293 ;
     RECT  32.115 45.185 32.706 45.293 ;
     RECT  6.84 45.185 6.966 45.329 ;
     RECT  10.332 45.293 10.926 45.329 ;
     RECT  23.868 45.293 24.534 45.329 ;
     RECT  27.612 45.221 27.63 45.329 ;
     RECT  30.852 45.185 30.87 45.329 ;
     RECT  2.415 45.293 2.862 45.377 ;
     RECT  5.115 45.059 5.706 45.377 ;
     RECT  7.815 45.185 7.905 45.377 ;
     RECT  10.515 45.329 10.926 45.377 ;
     RECT  13.215 45.293 13.305 45.377 ;
     RECT  15.915 45.245 16.005 45.377 ;
     RECT  18.615 45.197 19.566 45.377 ;
     RECT  20.988 45.185 21.405 45.377 ;
     RECT  24.015 45.329 24.105 45.377 ;
     RECT  26.715 45.149 26.874 45.377 ;
     RECT  29.415 45.185 29.505 45.377 ;
     RECT  32.115 45.293 32.205 45.377 ;
     RECT  34.815 45.107 34.905 45.377 ;
     RECT  37.515 45.107 37.605 45.377 ;
     RECT  40.215 45.107 40.305 45.377 ;
     RECT  42.915 45.107 43.005 45.377 ;
     RECT  45.615 45.107 45.705 45.377 ;
     RECT  48.315 45.107 48.405 45.377 ;
     RECT  0.144 45.259 0.558 45.389 ;
     RECT  22.32 45.293 22.878 45.419 ;
     RECT  26.856 45.377 26.874 45.419 ;
     RECT  10.656 45.377 10.926 45.455 ;
     RECT  14.832 45.185 14.922 45.455 ;
     RECT  22.536 45.419 22.554 45.455 ;
     RECT  2.844 45.377 2.862 45.491 ;
     RECT  6.84 45.329 6.894 45.491 ;
     RECT  10.728 45.455 10.926 45.491 ;
     RECT  10.908 45.491 10.926 45.527 ;
     RECT  14.904 45.455 14.922 45.527 ;
     RECT  18.828 45.377 19.566 45.527 ;
     RECT  20.988 45.377 21.006 45.527 ;
     RECT  6.84 45.491 6.858 45.533 ;
     RECT  3.636 45.293 4.266 45.563 ;
     RECT  0.432 45.389 0.558 45.821 ;
     RECT  3.636 45.563 3.978 45.965 ;
     RECT  3.96 45.965 3.978 46.109 ;
     RECT  0.432 45.821 0.522 46.253 ;
     RECT  0.504 46.253 0.522 46.397 ;
     RECT  5.436 45.377 5.706 46.541 ;
     RECT  5.436 46.541 5.454 46.685 ;
     RECT  19.332 45.527 19.566 47.501 ;
    LAYER M4 ;
     RECT  0.06 3.024 0.097 17.88 ;
     RECT  0.06 19.152 0.097 46.68 ;
     RECT  0.097 3.024 0.137 46.68 ;
     RECT  0.137 3.168 0.533 46.68 ;
     RECT  0.533 3.168 0.569 17.736 ;
     RECT  0.533 18.816 0.569 46.68 ;
     RECT  0.569 30.528 0.857 46.68 ;
     RECT  0.569 3.168 2.408 17.208 ;
     RECT  0.569 18.816 2.408 29.256 ;
     RECT  0.857 30.672 2.408 46.68 ;
     RECT  2.408 2.148 2.512 46.68 ;
     RECT  2.512 2.418 2.704 46.68 ;
     RECT  2.704 3.168 3.305 29.688 ;
     RECT  2.704 30.672 3.665 46.68 ;
     RECT  3.305 18.72 3.913 29.688 ;
     RECT  3.665 30.672 3.913 33.624 ;
     RECT  3.665 34.704 3.989 46.68 ;
     RECT  3.913 18.72 5.065 33.624 ;
     RECT  3.989 34.704 5.065 45.528 ;
     RECT  3.305 3.168 5.108 17.448 ;
     RECT  5.065 18.72 5.108 45.528 ;
     RECT  5.108 2.148 5.212 45.528 ;
     RECT  5.212 2.256 5.404 45.528 ;
     RECT  3.989 46.512 5.465 46.68 ;
     RECT  5.465 46.512 5.717 46.536 ;
     RECT  5.404 2.256 6.179 17.544 ;
     RECT  6.179 2.304 6.397 17.544 ;
     RECT  5.404 18.72 6.476 29.256 ;
     RECT  5.404 30.24 6.476 44.424 ;
     RECT  6.397 2.304 6.509 17.64 ;
     RECT  6.476 18.72 6.563 44.424 ;
     RECT  6.509 5.232 6.581 17.64 ;
     RECT  6.509 2.304 6.833 4.152 ;
     RECT  6.563 30.576 6.865 44.424 ;
     RECT  5.404 45.504 6.865 45.528 ;
     RECT  6.865 30.576 6.869 45.528 ;
     RECT  6.581 12.768 7.189 17.64 ;
     RECT  6.563 18.72 7.189 29.016 ;
     RECT  6.833 2.832 7.621 4.152 ;
     RECT  6.581 5.232 7.621 11.496 ;
     RECT  7.189 12.768 7.621 29.016 ;
     RECT  7.621 12.768 7.628 29.304 ;
     RECT  7.621 2.832 7.808 11.496 ;
     RECT  7.628 12.528 7.808 29.304 ;
     RECT  6.869 30.576 7.808 45.372 ;
     RECT  7.808 2.148 7.912 45.372 ;
     RECT  7.912 2.418 8.104 45.102 ;
     RECT  8.104 2.496 8.489 45 ;
     RECT  8.489 2.496 9.565 9.768 ;
     RECT  8.489 10.848 9.565 45 ;
     RECT  9.565 2.496 9.961 45 ;
     RECT  9.961 2.256 10.508 45 ;
     RECT  10.508 2.148 10.612 45.372 ;
     RECT  10.612 2.418 10.804 45.102 ;
     RECT  10.804 2.544 11.189 28.728 ;
     RECT  10.804 30.672 11.189 44.76 ;
     RECT  11.189 30.672 11.981 44.472 ;
     RECT  11.189 2.592 12.229 28.728 ;
     RECT  11.981 41.424 12.697 44.472 ;
     RECT  12.229 2.592 12.709 29.4 ;
     RECT  11.981 30.672 12.709 40.392 ;
     RECT  12.709 2.592 12.877 40.392 ;
     RECT  12.877 2.544 13.208 40.392 ;
     RECT  12.697 41.424 13.208 44.952 ;
     RECT  13.208 2.148 13.312 45.372 ;
     RECT  13.312 2.418 13.504 45.144 ;
     RECT  13.504 2.544 13.637 45.144 ;
     RECT  13.637 2.592 14.339 45.144 ;
     RECT  14.339 2.592 14.821 29.256 ;
     RECT  14.821 2.4 15.577 29.256 ;
     RECT  14.339 30.672 15.901 45.144 ;
     RECT  15.577 2.4 15.908 29.64 ;
     RECT  15.901 30.672 15.908 45.24 ;
     RECT  15.908 2.148 16.012 45.372 ;
     RECT  16.012 2.418 16.204 45.24 ;
     RECT  16.204 2.592 16.883 45.24 ;
     RECT  16.441 0.528 16.973 0.552 ;
     RECT  16.973 0.144 17.017 0.552 ;
     RECT  17.017 0.048 17.053 0.552 ;
     RECT  17.053 0.048 17.161 0.6 ;
     RECT  17.161 0.048 17.459 1.176 ;
     RECT  17.459 0.048 17.603 0.6 ;
     RECT  16.883 2.592 17.701 28.968 ;
     RECT  17.701 1.824 17.813 28.968 ;
     RECT  17.813 2.148 18.449 28.968 ;
     RECT  16.883 30.336 18.449 45.24 ;
     RECT  18.449 2.148 18.608 45.24 ;
     RECT  18.608 2.148 18.712 45.372 ;
     RECT  18.712 2.418 18.904 45.192 ;
     RECT  18.904 2.496 19.073 45.192 ;
     RECT  19.073 2.496 19.541 44.184 ;
     RECT  19.541 11.136 20.053 44.184 ;
     RECT  19.073 45.168 20.053 45.192 ;
     RECT  20.053 11.136 20.117 45.192 ;
     RECT  20.117 11.136 20.14 44.568 ;
     RECT  19.541 2.496 20.261 10.152 ;
     RECT  20.261 2.592 21.109 10.152 ;
     RECT  20.14 11.136 21.109 44.184 ;
     RECT  21.109 2.592 21.308 44.184 ;
     RECT  21.308 2.148 21.412 45.372 ;
     RECT  21.412 2.352 21.604 45.102 ;
     RECT  17.603 0.048 22.115 0.072 ;
     RECT  21.604 2.352 23.701 44.184 ;
     RECT  23.701 2.352 24.008 44.856 ;
     RECT  24.008 2.148 24.112 45.372 ;
     RECT  24.112 2.352 24.304 45.102 ;
     RECT  24.304 2.352 24.509 44.184 ;
     RECT  24.509 2.496 24.545 44.184 ;
     RECT  24.545 2.592 26.708 44.184 ;
     RECT  26.708 2.148 26.812 45.372 ;
     RECT  26.812 2.418 27.004 45.102 ;
     RECT  27.004 2.592 28.645 44.376 ;
     RECT  28.645 2.592 29.408 44.472 ;
     RECT  29.408 2.148 29.512 45.372 ;
     RECT  29.512 2.418 29.704 45.102 ;
     RECT  29.704 2.544 30.737 44.472 ;
     RECT  30.737 2.592 32.108 44.472 ;
     RECT  32.108 2.148 32.212 45.372 ;
     RECT  32.212 2.4 32.404 45.102 ;
     RECT  32.404 2.4 32.429 44.472 ;
     RECT  32.429 2.4 33.761 44.184 ;
     RECT  33.761 2.4 34.808 14.76 ;
     RECT  33.761 15.744 34.808 44.184 ;
     RECT  34.808 2.148 34.912 45.372 ;
     RECT  34.912 2.418 35.104 45.102 ;
     RECT  35.104 2.592 36.601 44.184 ;
     RECT  36.601 2.592 36.997 44.424 ;
     RECT  36.997 2.592 37.508 44.472 ;
     RECT  37.508 2.148 37.612 45.372 ;
     RECT  37.612 2.418 37.804 45.102 ;
     RECT  37.804 11.424 38.477 44.472 ;
     RECT  38.477 16.032 38.765 44.472 ;
     RECT  37.804 2.544 38.773 10.44 ;
     RECT  38.765 40.608 39.197 44.472 ;
     RECT  38.477 11.424 39.481 15.048 ;
     RECT  38.765 16.032 39.481 39.576 ;
     RECT  39.481 11.424 39.517 39.576 ;
     RECT  39.517 11.136 39.733 39.576 ;
     RECT  39.197 40.608 39.733 44.376 ;
     RECT  38.773 2.544 39.949 9.96 ;
     RECT  39.733 11.136 39.949 44.376 ;
     RECT  39.949 2.544 40.057 44.376 ;
     RECT  40.057 2.496 40.208 44.376 ;
     RECT  40.208 2.148 40.312 45.372 ;
     RECT  40.312 2.418 40.504 45.102 ;
     RECT  40.504 2.496 40.709 10.728 ;
     RECT  40.504 20.928 40.787 44.376 ;
     RECT  40.787 20.928 40.817 32.856 ;
     RECT  40.817 30.576 40.961 32.856 ;
     RECT  40.709 2.496 40.997 10.68 ;
     RECT  40.817 20.928 40.997 29.592 ;
     RECT  40.504 11.712 41.033 19.896 ;
     RECT  41.033 18.768 41.069 19.896 ;
     RECT  40.997 2.592 41.105 10.68 ;
     RECT  40.787 33.936 41.105 44.376 ;
     RECT  40.997 23.664 41.213 29.592 ;
     RECT  41.105 6.672 41.249 10.68 ;
     RECT  41.105 33.936 41.285 43.944 ;
     RECT  41.033 11.712 41.321 17.64 ;
     RECT  41.249 6.672 41.393 10.632 ;
     RECT  41.321 11.712 41.393 12.36 ;
     RECT  41.321 13.392 41.393 17.64 ;
     RECT  41.213 23.856 41.507 29.592 ;
     RECT  41.393 15.456 41.537 17.64 ;
     RECT  41.537 16.08 41.653 17.64 ;
     RECT  41.285 33.936 41.681 39.576 ;
     RECT  41.681 33.936 41.861 39.288 ;
     RECT  41.105 2.592 41.897 5.304 ;
     RECT  40.961 30.864 41.933 32.856 ;
     RECT  41.897 2.592 42.145 4.536 ;
     RECT  41.393 6.672 42.428 9.912 ;
     RECT  42.428 6.672 42.469 10.632 ;
     RECT  41.393 12.24 42.469 12.36 ;
     RECT  41.069 19.248 42.505 19.896 ;
     RECT  40.997 20.928 42.505 22.536 ;
     RECT  41.507 24.72 42.505 29.592 ;
     RECT  42.505 19.248 42.524 22.536 ;
     RECT  42.469 6.672 42.541 12.36 ;
     RECT  41.393 13.392 42.541 14.472 ;
     RECT  42.524 19.248 42.541 22.68 ;
     RECT  42.541 18.816 42.757 22.68 ;
     RECT  42.145 2.352 42.908 4.536 ;
     RECT  42.541 6.672 42.908 14.472 ;
     RECT  41.653 16.08 42.908 17.496 ;
     RECT  42.757 18.816 42.908 22.824 ;
     RECT  42.505 24.432 42.908 29.592 ;
     RECT  41.933 30.912 42.908 32.856 ;
     RECT  41.861 33.936 42.908 34.056 ;
     RECT  41.861 35.232 42.908 39.288 ;
     RECT  41.285 41.184 42.908 43.512 ;
     RECT  42.908 2.148 43.012 45.372 ;
     RECT  43.012 2.148 43.204 45.102 ;
     RECT  43.204 19.248 43.265 22.824 ;
     RECT  43.204 28.752 43.265 29.592 ;
     RECT  43.204 8.448 43.337 8.472 ;
     RECT  43.204 12.24 43.365 14.808 ;
     RECT  43.365 12.24 43.373 13.704 ;
     RECT  43.204 33.648 43.373 33.672 ;
     RECT  43.204 31.344 43.409 32.328 ;
     RECT  43.204 41.184 43.481 41.496 ;
     RECT  43.204 42.72 43.589 43.368 ;
     RECT  43.204 7.392 43.619 7.416 ;
     RECT  43.204 2.148 43.66 6.168 ;
     RECT  43.204 15.984 43.697 16.104 ;
     RECT  43.265 19.248 43.715 22.536 ;
     RECT  43.715 19.824 43.805 22.536 ;
     RECT  43.204 38.496 43.805 38.52 ;
     RECT  43.805 20.16 43.841 22.536 ;
     RECT  43.204 35.232 43.841 35.88 ;
     RECT  43.365 14.784 43.913 14.808 ;
     RECT  43.841 35.856 43.913 35.88 ;
     RECT  43.66 2.148 43.945 5.784 ;
     RECT  43.589 42.72 44.021 42.744 ;
     RECT  43.204 9.936 44.197 9.96 ;
     RECT  43.481 41.472 44.233 41.496 ;
     RECT  43.204 26.256 44.237 26.376 ;
     RECT  44.197 9.648 44.305 9.96 ;
     RECT  43.204 37.008 44.305 37.032 ;
     RECT  44.305 9.648 44.437 10.152 ;
     RECT  43.204 11.184 44.437 11.208 ;
     RECT  43.373 12.24 44.449 13.416 ;
     RECT  44.437 9.648 44.483 11.208 ;
     RECT  43.204 39.888 44.525 39.912 ;
     RECT  43.409 31.344 44.773 31.368 ;
     RECT  43.697 15.984 44.809 16.008 ;
     RECT  44.233 41.472 44.845 41.64 ;
     RECT  43.945 1.728 44.881 5.784 ;
     RECT  44.809 15.984 44.881 16.392 ;
     RECT  43.265 29.568 44.917 29.592 ;
     RECT  44.881 34.8 45.025 34.824 ;
     RECT  44.483 9.936 45.133 11.208 ;
     RECT  44.449 12.24 45.133 14.184 ;
     RECT  43.204 25.248 45.233 25.272 ;
     RECT  44.237 26.256 45.233 26.28 ;
     RECT  43.204 27.696 45.253 27.72 ;
     RECT  43.204 23.952 45.277 23.976 ;
     RECT  45.233 25.248 45.277 26.28 ;
     RECT  45.025 34.8 45.277 35.448 ;
     RECT  44.773 30.96 45.404 31.368 ;
     RECT  43.841 20.16 45.493 20.952 ;
     RECT  44.881 1.728 45.608 6.168 ;
     RECT  45.277 7.632 45.608 7.656 ;
     RECT  45.133 9.936 45.608 14.184 ;
     RECT  44.881 15.984 45.608 16.44 ;
     RECT  45.277 18.24 45.608 18.264 ;
     RECT  45.493 19.776 45.608 20.952 ;
     RECT  43.841 21.984 45.608 22.536 ;
     RECT  45.277 23.952 45.608 26.28 ;
     RECT  45.253 27.648 45.608 27.72 ;
     RECT  44.917 29.232 45.608 29.592 ;
     RECT  45.404 30.96 45.608 31.656 ;
     RECT  44.665 33.552 45.608 33.576 ;
     RECT  45.277 34.752 45.608 35.448 ;
     RECT  44.305 37.008 45.608 37.704 ;
     RECT  45.349 39.504 45.608 39.528 ;
     RECT  44.845 41.472 45.608 42.024 ;
     RECT  44.809 43.296 45.608 43.32 ;
     RECT  45.608 1.728 45.712 45.372 ;
     RECT  45.712 1.728 45.904 45.102 ;
     RECT  45.904 25.248 45.965 26.232 ;
     RECT  45.904 17.856 46.037 22.92 ;
     RECT  45.904 27.312 46.073 29.592 ;
     RECT  45.904 39.504 46.073 39.912 ;
     RECT  46.073 28.464 46.109 29.592 ;
     RECT  45.904 15.456 46.181 16.392 ;
     RECT  45.904 7.632 46.217 7.656 ;
     RECT  46.037 19.776 46.217 22.92 ;
     RECT  45.904 35.424 46.217 36.36 ;
     RECT  46.217 20.16 46.253 22.92 ;
     RECT  45.904 42.48 46.253 42.504 ;
     RECT  45.904 2.784 46.397 5.688 ;
     RECT  45.904 11.28 46.397 14.472 ;
     RECT  46.037 17.856 46.397 18.744 ;
     RECT  46.253 22.512 46.397 22.92 ;
     RECT  46.397 2.88 46.403 5.688 ;
     RECT  46.403 5.088 46.477 5.688 ;
     RECT  46.397 11.28 46.691 12.792 ;
     RECT  46.397 13.824 46.691 14.472 ;
     RECT  46.181 16.272 46.721 16.392 ;
     RECT  46.253 20.16 46.721 21.048 ;
     RECT  46.397 22.8 46.721 22.92 ;
     RECT  46.477 5.088 46.757 5.208 ;
     RECT  46.073 39.6 46.787 39.912 ;
     RECT  46.721 16.272 46.793 16.296 ;
     RECT  46.073 27.312 46.793 27.336 ;
     RECT  45.904 37.632 46.865 38.136 ;
     RECT  46.109 28.464 47.045 29.112 ;
     RECT  46.691 13.824 47.081 14.04 ;
     RECT  46.691 11.28 47.117 12.168 ;
     RECT  46.721 22.8 47.117 22.824 ;
     RECT  45.904 9.648 47.149 9.768 ;
     RECT  47.149 9.648 47.189 10.248 ;
     RECT  46.865 38.112 47.261 38.136 ;
     RECT  47.117 12.144 47.333 12.168 ;
     RECT  45.965 26.208 47.333 26.232 ;
     RECT  45.904 34.032 47.333 34.056 ;
     RECT  47.189 10.224 47.437 10.248 ;
     RECT  47.509 23.952 47.845 23.976 ;
     RECT  45.904 1.728 48.308 1.752 ;
     RECT  46.403 2.88 48.308 3.672 ;
     RECT  46.757 5.088 48.308 5.112 ;
     RECT  47.437 10.224 48.308 10.488 ;
     RECT  47.081 14.016 48.308 14.04 ;
     RECT  47.293 15.024 48.308 15.048 ;
     RECT  46.397 17.856 48.308 17.88 ;
     RECT  46.721 21.024 48.308 21.048 ;
     RECT  47.845 23.328 48.308 23.976 ;
     RECT  47.045 28.464 48.308 28.488 ;
     RECT  46.217 35.424 48.308 36.072 ;
     RECT  46.787 39.888 48.308 39.912 ;
     RECT  48.308 1.728 48.412 45.372 ;
     RECT  48.412 1.728 48.604 45.102 ;
     RECT  48.604 1.728 49.561 3.672 ;
     RECT  49.561 1.008 49.597 3.672 ;
     RECT  48.604 6.768 49.597 6.792 ;
     RECT  48.604 7.92 49.597 7.944 ;
     RECT  48.604 10.368 49.597 10.392 ;
     RECT  48.604 21.744 49.597 22.92 ;
     RECT  48.604 36.72 49.597 37.896 ;
     RECT  48.604 33.12 49.633 33.864 ;
     RECT  49.597 1.008 49.669 4.632 ;
     RECT  48.604 18.72 49.669 18.744 ;
     RECT  49.669 1.008 49.705 4.92 ;
     RECT  49.705 1.008 49.777 5.064 ;
     RECT  48.604 17.28 49.777 17.304 ;
     RECT  49.669 18.72 49.777 19.752 ;
     RECT  49.597 21.168 49.777 23.064 ;
     RECT  49.597 36.72 49.777 38.76 ;
     RECT  49.597 40.32 49.777 40.344 ;
     RECT  49.597 35.136 49.813 35.16 ;
     RECT  49.777 36.72 49.813 40.344 ;
     RECT  48.604 28.656 49.849 28.68 ;
     RECT  49.597 26.352 50.101 27.24 ;
     RECT  48.604 43.2 50.101 43.224 ;
     RECT  49.777 1.008 50.137 5.352 ;
     RECT  49.597 6.624 50.137 7.944 ;
     RECT  48.604 12.672 50.137 12.696 ;
     RECT  49.669 15.264 50.137 15.288 ;
     RECT  49.777 17.28 50.137 19.752 ;
     RECT  49.777 20.88 50.137 23.496 ;
     RECT  49.597 24.624 50.137 24.648 ;
     RECT  50.101 26.064 50.137 27.24 ;
     RECT  49.849 28.656 50.137 28.968 ;
     RECT  48.604 31.104 50.137 31.992 ;
     RECT  49.633 33.12 50.137 34.008 ;
     RECT  49.813 35.136 50.137 40.344 ;
     RECT  50.101 43.056 50.137 43.224 ;
     RECT  50.137 0.72 50.173 7.944 ;
     RECT  49.597 9.936 50.173 11.544 ;
     RECT  50.137 12.672 50.173 19.752 ;
     RECT  50.137 20.88 50.173 40.776 ;
     RECT  49.777 41.904 50.173 41.928 ;
     RECT  50.137 42.912 50.173 43.224 ;
     RECT  50.173 9.936 50.641 19.752 ;
     RECT  50.173 20.88 50.641 43.224 ;
     RECT  50.173 0.72 50.677 8.952 ;
     RECT  50.641 9.936 50.677 43.224 ;
     RECT  50.677 0.72 51.804 43.224 ;
    LAYER M5 ;
     RECT  16.848 0.016 17.736 1.859 ;
     RECT  16.848 1.859 17.304 2.137 ;
     RECT  22.08 0.037 22.104 2.137 ;
     RECT  2.4 2.137 2.52 2.151 ;
     RECT  5.1 2.137 5.22 2.151 ;
     RECT  7.8 2.137 7.92 2.151 ;
     RECT  10.5 2.137 10.62 2.151 ;
     RECT  13.2 2.137 13.32 2.151 ;
     RECT  18.6 2.137 18.72 2.151 ;
     RECT  24 2.137 24.12 2.151 ;
     RECT  26.7 2.137 26.82 2.151 ;
     RECT  29.4 2.137 29.52 2.151 ;
     RECT  32.1 2.137 32.22 2.151 ;
     RECT  34.8 2.137 34.92 2.151 ;
     RECT  37.5 2.137 37.62 2.151 ;
     RECT  40.2 2.137 40.32 2.151 ;
     RECT  42.9 2.137 43.02 2.151 ;
     RECT  45.6 2.137 45.72 2.151 ;
     RECT  48.3 2.137 48.42 2.151 ;
     RECT  5.1 2.151 5.412 2.245 ;
     RECT  10.5 2.151 10.812 2.245 ;
     RECT  24 2.151 24.312 2.629 ;
     RECT  18.6 2.151 18.912 2.677 ;
     RECT  13.2 2.151 13.512 2.773 ;
     RECT  32.1 2.151 32.412 2.773 ;
     RECT  9.984 2.245 10.812 3.059 ;
     RECT  37.5 2.151 37.812 3.061 ;
     RECT  5.1 2.245 6.168 3.205 ;
     RECT  7.8 2.151 8.112 3.205 ;
     RECT  5.1 3.205 8.112 3.301 ;
     RECT  15.9 2.137 17.304 3.397 ;
     RECT  13.2 2.773 13.752 3.443 ;
     RECT  31.872 2.773 32.412 3.589 ;
     RECT  15.024 3.397 17.304 3.877 ;
     RECT  18.6 2.677 19.416 3.877 ;
     RECT  5.1 3.301 8.808 3.923 ;
     RECT  36.768 3.061 37.812 3.971 ;
     RECT  15.024 3.877 19.416 4.115 ;
     RECT  25.68 3.397 25.704 4.163 ;
     RECT  31.584 3.589 32.412 4.403 ;
     RECT  13.2 3.443 13.608 4.405 ;
     RECT  26.7 2.151 27.012 4.405 ;
     RECT  45.6 2.151 45.912 4.501 ;
     RECT  5.1 3.923 6.168 4.547 ;
     RECT  15.024 4.115 18.912 4.595 ;
     RECT  7.8 3.923 8.808 4.739 ;
     RECT  29.4 2.151 29.712 5.029 ;
     RECT  5.1 4.547 5.412 5.077 ;
     RECT  23.136 2.629 24.312 5.171 ;
     RECT  36.48 4.549 36.504 5.459 ;
     RECT  6.528 5.365 6.552 5.555 ;
     RECT  45.6 4.501 46.392 5.653 ;
     RECT  34.8 2.151 35.112 5.989 ;
     RECT  42.9 2.151 43.212 6.133 ;
     RECT  29.088 5.029 29.712 6.229 ;
     RECT  11.856 3.685 11.88 6.323 ;
     RECT  10.5 3.059 10.812 6.373 ;
     RECT  37.5 3.971 37.812 6.373 ;
     RECT  26.7 4.405 27.672 6.613 ;
     RECT  28.896 6.229 29.712 6.613 ;
     RECT  7.8 4.739 8.424 6.805 ;
     RECT  21.3 2.137 22.104 6.805 ;
     RECT  32.1 4.403 32.412 6.805 ;
     RECT  4.176 5.077 5.412 6.851 ;
     RECT  37.056 6.373 37.812 6.851 ;
     RECT  10.368 6.373 10.812 6.947 ;
     RECT  20.544 6.805 22.104 7.333 ;
     RECT  20.544 7.333 22.248 7.379 ;
     RECT  23.616 5.171 24.312 7.427 ;
     RECT  42.9 6.133 43.608 7.427 ;
     RECT  39.12 6.277 39.144 7.909 ;
     RECT  31.392 6.805 32.412 7.955 ;
     RECT  38.784 7.909 39.144 7.955 ;
     RECT  5.1 6.851 5.412 7.957 ;
     RECT  10.5 6.947 10.812 8.197 ;
     RECT  20.832 7.379 22.248 8.435 ;
     RECT  31.872 7.955 32.412 8.437 ;
     RECT  7.8 6.805 8.52 8.485 ;
     RECT  5.1 7.957 5.784 8.533 ;
     RECT  7.056 8.485 8.52 8.533 ;
     RECT  10.368 8.197 10.812 8.579 ;
     RECT  13.2 4.405 13.704 8.579 ;
     RECT  20.832 8.435 22.104 8.627 ;
     RECT  12.192 6.805 12.216 8.677 ;
     RECT  13.2 8.579 13.608 8.677 ;
     RECT  42.9 7.427 43.212 8.869 ;
     RECT  5.1 8.533 8.52 9.011 ;
     RECT  12.192 8.677 13.608 9.011 ;
     RECT  30.72 8.533 30.744 9.061 ;
     RECT  31.872 8.437 32.568 9.061 ;
     RECT  37.5 6.851 37.812 9.061 ;
     RECT  38.784 7.955 38.808 9.061 ;
     RECT  37.5 9.061 38.808 9.107 ;
     RECT  3.984 7.909 4.008 9.155 ;
     RECT  30.72 9.061 32.568 9.203 ;
     RECT  26.7 6.613 29.712 9.253 ;
     RECT  45.6 5.653 46.44 9.733 ;
     RECT  14.832 8.485 14.856 9.779 ;
     RECT  21.168 8.627 22.104 9.781 ;
     RECT  21.12 9.781 22.104 9.925 ;
     RECT  12.192 9.011 13.512 10.069 ;
     RECT  34.224 5.989 35.112 10.069 ;
     RECT  26.208 9.253 29.712 10.115 ;
     RECT  5.1 9.011 8.424 10.307 ;
     RECT  23.904 7.427 24.312 10.403 ;
     RECT  37.5 9.107 38.76 10.451 ;
     RECT  5.1 10.307 8.376 10.595 ;
     RECT  10.5 8.579 10.812 10.741 ;
     RECT  7.056 10.595 8.376 10.835 ;
     RECT  15.9 4.595 18.912 10.883 ;
     RECT  26.208 10.115 27.672 10.883 ;
     RECT  31.104 9.203 32.568 10.883 ;
     RECT  11.952 10.069 13.512 11.219 ;
     RECT  44.448 9.637 44.472 11.219 ;
     RECT  31.104 10.883 32.412 11.267 ;
     RECT  34.224 10.069 35.256 11.267 ;
     RECT  42.48 8.869 43.212 11.363 ;
     RECT  37.5 10.451 37.812 11.365 ;
     RECT  45.6 9.733 46.68 11.365 ;
     RECT  7.68 10.835 8.376 11.413 ;
     RECT  29.4 10.115 29.712 11.413 ;
     RECT  21.12 9.925 22.392 11.843 ;
     RECT  2.4 2.151 2.712 11.941 ;
     RECT  5.1 10.595 5.412 11.941 ;
     RECT  10.224 10.741 10.812 12.035 ;
     RECT  15.9 10.883 17.304 12.035 ;
     RECT  45.6 11.365 46.728 12.179 ;
     RECT  2.4 11.941 3.288 12.275 ;
     RECT  18.6 10.883 18.912 12.469 ;
     RECT  36.864 11.365 37.812 12.515 ;
     RECT  42.768 11.363 43.212 12.515 ;
     RECT  5.1 11.941 5.592 12.563 ;
     RECT  38.784 11.749 38.808 12.563 ;
     RECT  7.68 11.413 8.568 12.611 ;
     RECT  37.5 12.515 37.812 12.901 ;
     RECT  18.6 12.469 19.032 13.045 ;
     RECT  21.3 11.843 22.392 13.045 ;
     RECT  29.28 11.413 29.712 13.045 ;
     RECT  31.104 11.267 31.128 13.045 ;
     RECT  12.384 11.219 13.512 13.139 ;
     RECT  29.28 13.045 31.128 13.429 ;
     RECT  15.9 12.035 16.872 13.477 ;
     RECT  18.6 13.045 19.08 13.525 ;
     RECT  28.992 13.429 31.128 13.525 ;
     RECT  34.8 11.267 35.256 13.573 ;
     RECT  20.544 13.045 22.392 13.621 ;
     RECT  24 10.403 24.312 13.621 ;
     RECT  7.68 12.611 8.376 13.669 ;
     RECT  42.9 12.515 43.212 13.669 ;
     RECT  15.9 13.477 17.208 14.197 ;
     RECT  28.272 13.525 31.128 14.243 ;
     RECT  34.8 13.573 35.736 14.291 ;
     RECT  37.5 12.901 38.184 14.339 ;
     RECT  42.9 13.669 43.32 14.435 ;
     RECT  26.208 10.883 27.288 14.485 ;
     RECT  28.272 14.243 28.296 14.485 ;
     RECT  26.208 14.485 28.296 14.531 ;
     RECT  2.4 12.275 2.712 14.533 ;
     RECT  12.72 13.139 13.512 14.533 ;
     RECT  31.008 14.243 31.128 14.533 ;
     RECT  32.1 11.267 32.412 14.533 ;
     RECT  1.968 14.533 2.712 14.675 ;
     RECT  20.544 13.621 24.312 14.675 ;
     RECT  7.248 13.669 8.376 14.869 ;
     RECT  26.208 14.531 27.816 14.915 ;
     RECT  31.008 14.533 32.412 15.395 ;
     RECT  37.5 14.339 38.136 15.731 ;
     RECT  34.8 14.291 35.112 15.829 ;
     RECT  6.864 14.869 8.376 15.925 ;
     RECT  21.3 14.675 24.312 15.925 ;
     RECT  10.5 12.035 10.812 16.069 ;
     RECT  12.48 14.533 13.512 16.069 ;
     RECT  14.736 15.061 14.76 16.115 ;
     RECT  26.544 14.915 27.816 16.115 ;
     RECT  40.2 2.151 40.512 16.405 ;
     RECT  6.864 15.925 9.24 16.501 ;
     RECT  6.768 16.501 9.24 16.595 ;
     RECT  20.496 15.925 24.312 16.595 ;
     RECT  33.552 15.829 33.576 16.595 ;
     RECT  6.768 16.595 8.376 16.835 ;
     RECT  32.1 15.395 32.412 16.837 ;
     RECT  34.8 15.829 35.592 16.837 ;
     RECT  20.496 16.595 22.104 16.883 ;
     RECT  29.4 14.243 29.712 16.885 ;
     RECT  31.008 15.395 31.128 16.885 ;
     RECT  6.768 16.835 8.112 17.027 ;
     RECT  39.6 16.405 40.512 17.171 ;
     RECT  12.48 16.069 13.704 17.413 ;
     RECT  15.9 14.197 17.4 17.413 ;
     RECT  18.6 13.525 19.128 17.413 ;
     RECT  15.9 17.413 19.128 17.459 ;
     RECT  34.8 16.837 36.264 17.459 ;
     RECT  29.4 16.885 31.128 17.509 ;
     RECT  32.1 16.837 33.096 17.509 ;
     RECT  18.24 17.459 19.128 17.555 ;
     RECT  2.4 14.675 2.712 17.605 ;
     RECT  29.4 17.509 33.096 17.651 ;
     RECT  29.4 17.651 31.128 17.699 ;
     RECT  10.5 16.069 10.968 17.939 ;
     RECT  21.072 16.883 22.104 17.989 ;
     RECT  12.48 17.413 14.424 18.035 ;
     RECT  18.24 17.555 19.032 18.035 ;
     RECT  2.4 17.605 3.288 18.179 ;
     RECT  29.4 17.699 29.88 18.181 ;
     RECT  26.544 16.115 27.48 18.227 ;
     RECT  31.008 17.699 31.128 18.275 ;
     RECT  18.24 18.035 18.912 18.421 ;
     RECT  20.256 17.989 22.104 18.421 ;
     RECT  23.136 16.595 24.312 18.421 ;
     RECT  20.256 18.421 24.312 18.467 ;
     RECT  21.3 18.467 24.312 18.515 ;
     RECT  23.376 18.515 24.312 18.707 ;
     RECT  26.544 18.227 27.012 18.707 ;
     RECT  6.816 17.027 8.112 18.709 ;
     RECT  6.624 18.709 8.112 18.755 ;
     RECT  31.104 18.275 31.128 18.757 ;
     RECT  32.1 17.651 33.096 18.757 ;
     RECT  5.1 12.563 5.412 18.949 ;
     RECT  29.28 18.181 29.88 18.995 ;
     RECT  2.4 18.179 2.712 19.141 ;
     RECT  34.8 17.459 35.592 19.189 ;
     RECT  42.9 14.435 43.212 19.237 ;
     RECT  12.72 18.035 14.424 19.333 ;
     RECT  15.9 17.459 16.872 19.333 ;
     RECT  41.616 17.605 41.64 19.333 ;
     RECT  42.9 19.237 43.704 19.333 ;
     RECT  10.5 17.939 10.92 19.379 ;
     RECT  41.616 19.333 43.704 19.379 ;
     RECT  4.992 18.949 5.412 19.475 ;
     RECT  29.4 18.995 29.88 19.765 ;
     RECT  31.104 18.757 33.096 19.811 ;
     RECT  23.808 18.707 24.312 19.909 ;
     RECT  26.7 18.707 27.012 19.909 ;
     RECT  2.4 19.141 3.336 20.003 ;
     RECT  12.72 19.333 16.872 20.051 ;
     RECT  45.6 12.179 46.68 20.195 ;
     RECT  6.624 18.755 6.696 20.291 ;
     RECT  23.376 19.909 24.312 20.341 ;
     RECT  40.2 17.171 40.512 20.389 ;
     RECT  7.68 18.755 8.112 20.579 ;
     RECT  14.832 20.051 16.872 20.579 ;
     RECT  18.192 18.421 18.912 20.579 ;
     RECT  21.3 18.515 22.2 20.579 ;
     RECT  31.104 19.811 32.412 20.579 ;
     RECT  34.608 19.189 35.592 20.581 ;
     RECT  23.376 20.341 24.408 20.675 ;
     RECT  29.4 19.765 29.976 20.867 ;
     RECT  26.7 19.909 27.384 20.915 ;
     RECT  3.936 20.869 3.96 21.011 ;
     RECT  10.5 19.379 10.812 21.013 ;
     RECT  42.144 19.379 43.704 21.107 ;
     RECT  29.4 20.867 29.88 21.109 ;
     RECT  10.272 21.013 10.812 21.155 ;
     RECT  28.56 21.109 29.88 21.155 ;
     RECT  5.1 19.475 5.412 21.157 ;
     RECT  25.536 18.181 25.56 21.349 ;
     RECT  26.7 20.915 27.012 21.349 ;
     RECT  12.72 20.051 13.512 21.397 ;
     RECT  2.4 20.003 2.952 21.683 ;
     RECT  6.624 20.291 6.648 21.683 ;
     RECT  42.576 21.107 43.704 21.683 ;
     RECT  18.48 20.579 18.912 21.685 ;
     RECT  20.256 18.467 20.28 21.731 ;
     RECT  23.376 20.675 24.312 21.731 ;
     RECT  18.48 21.685 19.032 22.259 ;
     RECT  25.536 21.349 27.012 22.259 ;
     RECT  12.72 21.397 13.944 22.357 ;
     RECT  4.848 21.157 5.412 22.451 ;
     RECT  37.5 15.731 37.812 22.741 ;
     RECT  39.888 20.389 40.512 22.787 ;
     RECT  11.904 22.357 13.944 23.027 ;
     RECT  34.608 20.581 35.88 23.027 ;
     RECT  21.3 20.579 22.104 23.029 ;
     RECT  18.6 22.259 19.032 23.269 ;
     RECT  28.56 21.155 29.712 23.315 ;
     RECT  48.3 2.151 48.612 23.317 ;
     RECT  11.904 23.027 13.512 23.363 ;
     RECT  12.72 23.363 13.512 23.411 ;
     RECT  14.976 20.579 16.872 23.411 ;
     RECT  37.392 22.741 37.812 23.411 ;
     RECT  20.544 23.029 22.104 23.555 ;
     RECT  40.2 22.787 40.512 23.845 ;
     RECT  7.8 20.579 8.112 23.893 ;
     RECT  18.48 23.269 19.032 23.893 ;
     RECT  47.856 23.317 48.612 23.987 ;
     RECT  20.544 23.555 21.612 24.131 ;
     RECT  42.576 21.683 43.212 24.467 ;
     RECT  18.24 23.893 19.032 24.469 ;
     RECT  7.68 23.893 8.112 24.515 ;
     RECT  34.608 23.027 35.112 24.757 ;
     RECT  37.5 23.411 37.812 24.997 ;
     RECT  40.2 23.845 41.496 25.045 ;
     RECT  2.4 21.683 2.712 25.381 ;
     RECT  2.4 25.381 3.336 25.571 ;
     RECT  45.6 20.195 45.912 25.621 ;
     RECT  10.5 21.155 10.812 25.717 ;
     RECT  33.6 24.517 33.624 25.763 ;
     RECT  39.744 25.045 41.496 25.763 ;
     RECT  39.744 25.763 40.632 25.811 ;
     RECT  18.24 24.469 19.272 26.147 ;
     RECT  32.1 20.579 32.412 26.197 ;
     RECT  37.5 24.997 38.184 26.245 ;
     RECT  34.608 24.757 35.352 26.387 ;
     RECT  9.744 25.717 10.812 26.437 ;
     RECT  37.5 26.245 39.144 26.579 ;
     RECT  25.92 22.259 27.012 26.581 ;
     RECT  29.4 23.315 29.712 26.725 ;
     RECT  37.5 26.579 38.184 26.771 ;
     RECT  34.8 26.387 35.352 26.819 ;
     RECT  42.72 24.467 43.212 26.819 ;
     RECT  18.6 26.147 19.272 26.917 ;
     RECT  40.2 25.811 40.632 27.059 ;
     RECT  25.92 26.581 27.336 27.107 ;
     RECT  9.408 26.437 10.812 27.157 ;
     RECT  14.976 23.411 16.392 27.157 ;
     RECT  0.144 27.061 0.168 27.203 ;
     RECT  31.104 20.579 31.128 27.205 ;
     RECT  7.8 24.515 8.112 27.301 ;
     RECT  9.408 27.157 10.92 27.301 ;
     RECT  45.264 25.621 45.912 27.301 ;
     RECT  7.8 27.301 10.92 27.347 ;
     RECT  26.7 27.107 27.336 27.443 ;
     RECT  45.264 27.301 46.008 27.635 ;
     RECT  45.264 27.635 45.912 27.683 ;
     RECT  40.2 27.059 40.512 27.829 ;
     RECT  9.792 27.347 10.92 27.923 ;
     RECT  34.8 26.819 35.208 27.925 ;
     RECT  7.8 27.347 8.52 27.971 ;
     RECT  5.1 22.451 5.412 27.973 ;
     RECT  32.1 26.197 33.096 28.403 ;
     RECT  31.008 27.205 31.128 28.499 ;
     RECT  39.36 27.829 40.512 28.643 ;
     RECT  18.6 26.917 19.416 28.645 ;
     RECT  24 21.731 24.312 28.789 ;
     RECT  18.6 28.645 19.944 28.981 ;
     RECT  18.48 28.981 19.944 29.027 ;
     RECT  9.792 27.923 10.812 29.029 ;
     RECT  26.7 27.443 27.012 29.029 ;
     RECT  23.136 28.789 24.312 29.077 ;
     RECT  23.136 29.077 25.176 29.219 ;
     RECT  12.816 23.411 13.512 29.221 ;
     RECT  14.976 27.157 16.872 29.221 ;
     RECT  19.92 29.027 19.944 29.315 ;
     RECT  23.136 29.219 24.312 29.315 ;
     RECT  4.992 27.973 5.412 29.507 ;
     RECT  31.104 28.499 31.128 29.605 ;
     RECT  32.1 28.403 32.412 29.605 ;
     RECT  18.48 29.027 18.912 29.699 ;
     RECT  29.28 26.725 29.712 29.795 ;
     RECT  7.8 27.971 8.112 30.133 ;
     RECT  9.552 29.029 10.812 30.133 ;
     RECT  21.3 24.131 21.612 30.133 ;
     RECT  34.8 27.925 35.688 30.181 ;
     RECT  6.528 27.877 6.552 30.275 ;
     RECT  39.888 28.643 40.512 30.275 ;
     RECT  34.8 30.181 36.504 30.323 ;
     RECT  25.296 29.605 25.32 30.611 ;
     RECT  37.5 26.771 37.812 30.757 ;
     RECT  12.72 29.221 16.872 30.851 ;
     RECT  18.6 29.699 18.912 30.853 ;
     RECT  31.104 29.605 32.412 31.091 ;
     RECT  24 29.315 24.312 31.285 ;
     RECT  36.48 30.323 36.504 31.331 ;
     RECT  20.544 30.133 21.612 31.379 ;
     RECT  33.648 30.469 33.672 31.379 ;
     RECT  37.5 30.757 38.568 31.379 ;
     RECT  12.72 30.851 13.512 31.427 ;
     RECT  7.8 30.133 10.812 31.811 ;
     RECT  22.992 30.997 23.016 31.811 ;
     RECT  24 31.285 25.128 31.811 ;
     RECT  14.976 30.851 16.872 31.813 ;
     RECT  40.2 30.275 40.512 31.861 ;
     RECT  14.976 31.813 17.16 31.955 ;
     RECT  7.8 31.811 9.048 32.437 ;
     RECT  7.152 32.437 9.048 32.771 ;
     RECT  14.976 31.955 16.392 32.773 ;
     RECT  24 31.811 24.888 32.773 ;
     RECT  34.8 30.323 35.208 32.819 ;
     RECT  23.904 32.773 24.888 32.917 ;
     RECT  18.6 30.853 19.32 33.013 ;
     RECT  26.7 29.029 27.144 33.253 ;
     RECT  3.936 32.725 3.96 33.539 ;
     RECT  23.136 32.917 24.888 33.587 ;
     RECT  37.5 31.379 37.812 33.589 ;
     RECT  40.2 31.861 40.776 33.683 ;
     RECT  18.6 33.013 19.368 33.827 ;
     RECT  26.112 33.253 27.288 34.067 ;
     RECT  26.7 34.067 27.288 34.115 ;
     RECT  21.3 31.379 21.612 34.165 ;
     RECT  7.152 32.771 8.112 34.211 ;
     RECT  31.392 31.091 32.412 34.213 ;
     RECT  24 33.587 24.696 34.355 ;
     RECT  37.392 33.589 37.812 34.355 ;
     RECT  12.816 31.427 13.512 34.549 ;
     RECT  14.832 32.773 16.392 34.549 ;
     RECT  2.4 25.571 2.712 34.741 ;
     RECT  10.5 31.811 10.812 34.789 ;
     RECT  45.456 27.683 45.912 34.789 ;
     RECT  31.296 34.213 32.412 34.931 ;
     RECT  21.168 34.165 22.2 35.123 ;
     RECT  24 34.355 24.312 35.269 ;
     RECT  37.5 34.355 37.812 35.317 ;
     RECT  10.5 34.789 10.92 35.411 ;
     RECT  37.008 35.317 37.812 35.557 ;
     RECT  12.816 34.549 16.392 35.699 ;
     RECT  2.4 34.741 3.096 35.701 ;
     RECT  5.1 29.507 5.412 35.701 ;
     RECT  2.4 35.701 3.96 35.843 ;
     RECT  26.7 34.115 27.012 35.845 ;
     RECT  7.8 34.211 8.112 35.941 ;
     RECT  36.144 35.557 37.812 36.035 ;
     RECT  18.6 33.827 18.912 36.421 ;
     RECT  26.016 35.845 27.012 36.421 ;
     RECT  21.3 35.123 22.2 36.659 ;
     RECT  18.6 36.421 19.704 36.757 ;
     RECT  18.6 36.757 19.8 36.899 ;
     RECT  25.872 36.421 27.012 36.899 ;
     RECT  14.976 35.699 16.392 37.045 ;
     RECT  7.8 35.941 8.52 37.091 ;
     RECT  11.808 36.229 11.832 37.091 ;
     RECT  18.6 36.899 19.704 37.091 ;
     RECT  14.976 37.045 17.256 37.187 ;
     RECT  7.8 37.091 8.112 37.429 ;
     RECT  21.3 36.659 21.612 37.573 ;
     RECT  26.016 36.899 27.012 37.667 ;
     RECT  36.144 36.035 36.504 38.147 ;
     RECT  10.5 35.411 10.812 38.149 ;
     RECT  20.88 37.573 21.612 38.149 ;
     RECT  23.328 35.269 24.312 38.149 ;
     RECT  2.4 35.843 3.48 38.195 ;
     RECT  12.816 35.699 13.704 38.195 ;
     RECT  39.12 38.245 39.144 38.435 ;
     RECT  14.976 37.187 16.392 38.483 ;
     RECT  18.6 37.091 18.912 38.533 ;
     RECT  5.1 35.701 6.168 38.773 ;
     RECT  7.344 37.429 8.112 38.915 ;
     RECT  40.2 33.683 40.512 38.965 ;
     RECT  29.4 29.795 29.712 39.013 ;
     RECT  31.392 34.931 32.412 39.013 ;
     RECT  22.944 38.149 24.312 39.155 ;
     RECT  10.5 38.149 10.92 39.251 ;
     RECT  26.7 37.667 27.012 39.301 ;
     RECT  23.616 39.155 24.312 39.395 ;
     RECT  13.104 38.195 13.704 39.539 ;
     RECT  28.032 35.317 28.056 39.539 ;
     RECT  29.4 39.013 32.412 39.539 ;
     RECT  45.36 34.789 45.912 39.539 ;
     RECT  45.504 39.539 45.912 39.589 ;
     RECT  34.8 32.819 35.112 39.733 ;
     RECT  2.4 38.195 3.384 39.779 ;
     RECT  26.496 39.301 27.012 39.877 ;
     RECT  20.544 38.149 21.612 39.923 ;
     RECT  45.504 39.589 46.776 39.923 ;
     RECT  29.4 39.539 30.696 40.019 ;
     RECT  18.6 38.533 19.08 40.163 ;
     RECT  5.1 38.773 6.264 40.405 ;
     RECT  7.8 38.915 8.112 40.405 ;
     RECT  34.416 39.733 35.112 40.405 ;
     RECT  36.144 38.147 36.168 40.405 ;
     RECT  37.5 36.035 37.812 40.405 ;
     RECT  20.88 39.923 21.612 40.547 ;
     RECT  39.984 38.965 40.512 40.835 ;
     RECT  25.68 39.877 27.012 40.837 ;
     RECT  21.3 40.547 21.612 40.885 ;
     RECT  29.4 40.019 30.552 40.933 ;
     RECT  25.68 40.837 27.816 41.027 ;
     RECT  34.224 40.405 35.112 41.027 ;
     RECT  29.28 40.933 30.552 41.075 ;
     RECT  40.2 40.835 40.512 41.221 ;
     RECT  5.1 40.405 8.112 41.267 ;
     RECT  21.3 40.885 22.248 41.461 ;
     RECT  24 39.395 24.312 41.461 ;
     RECT  21.3 41.461 24.312 41.507 ;
     RECT  29.28 41.075 29.712 41.651 ;
     RECT  34.416 41.027 35.112 41.651 ;
     RECT  45.504 39.923 45.912 41.651 ;
     RECT  26.496 41.027 27.816 41.941 ;
     RECT  32.1 39.539 32.412 41.941 ;
     RECT  13.2 39.539 13.704 41.987 ;
     RECT  36.144 40.405 37.812 41.987 ;
     RECT  13.2 41.987 13.656 42.275 ;
     RECT  18.6 40.163 18.912 42.325 ;
     RECT  5.1 41.267 6.312 42.755 ;
     RECT  31.344 41.941 32.412 42.755 ;
     RECT  7.8 41.267 8.112 42.805 ;
     RECT  21.3 41.507 21.72 42.851 ;
     RECT  22.704 41.507 24.312 42.995 ;
     RECT  10.5 39.251 10.812 43.141 ;
     RECT  26.496 41.941 27.96 43.331 ;
     RECT  26.496 43.331 27.012 43.475 ;
     RECT  36.144 41.987 36.168 43.475 ;
     RECT  37.5 41.987 37.812 43.477 ;
     RECT  22.704 42.995 22.728 43.667 ;
     RECT  7.392 42.805 8.112 43.813 ;
     RECT  40.2 41.221 41.064 43.955 ;
     RECT  31.776 42.755 32.412 44.003 ;
     RECT  36.528 43.477 37.812 44.051 ;
     RECT  33.6 42.613 33.624 44.195 ;
     RECT  18.192 42.325 18.912 44.197 ;
     RECT  10.5 43.141 10.92 44.483 ;
     RECT  14.976 38.483 16.212 44.483 ;
     RECT  20.064 43.861 20.088 44.579 ;
     RECT  23.712 42.995 24.312 44.867 ;
     RECT  7.104 43.813 8.112 45.059 ;
     RECT  15.408 44.483 16.212 45.155 ;
     RECT  17.616 44.197 18.912 45.251 ;
     RECT  2.4 39.779 2.712 45.369 ;
     RECT  5.1 42.755 5.412 45.369 ;
     RECT  7.8 45.059 8.112 45.369 ;
     RECT  10.5 44.483 10.812 45.369 ;
     RECT  13.2 42.275 13.512 45.369 ;
     RECT  15.9 45.155 16.212 45.369 ;
     RECT  18.6 45.251 18.912 45.369 ;
     RECT  21.3 42.851 21.612 45.369 ;
     RECT  24 44.867 24.312 45.369 ;
     RECT  26.7 43.475 27.012 45.369 ;
     RECT  29.4 41.651 29.712 45.369 ;
     RECT  32.1 44.003 32.412 45.369 ;
     RECT  34.8 41.651 35.112 45.369 ;
     RECT  37.5 44.051 37.812 45.369 ;
     RECT  40.2 43.955 40.512 45.369 ;
     RECT  42.9 26.819 43.212 45.369 ;
     RECT  45.6 41.651 45.912 45.369 ;
     RECT  48.3 23.987 48.612 45.369 ;
     RECT  2.4 45.369 2.52 45.383 ;
     RECT  5.1 45.369 5.22 45.383 ;
     RECT  7.8 45.369 7.92 45.383 ;
     RECT  10.5 45.369 10.62 45.383 ;
     RECT  13.2 45.369 13.32 45.383 ;
     RECT  15.9 45.369 16.02 45.383 ;
     RECT  18.6 45.369 18.72 45.383 ;
     RECT  21.3 45.369 21.42 45.383 ;
     RECT  24 45.369 24.12 45.383 ;
     RECT  26.7 45.369 26.82 45.383 ;
     RECT  29.4 45.369 29.52 45.383 ;
     RECT  32.1 45.369 32.22 45.383 ;
     RECT  34.8 45.369 34.92 45.383 ;
     RECT  37.5 45.369 37.62 45.383 ;
     RECT  40.2 45.369 40.32 45.383 ;
     RECT  42.9 45.369 43.02 45.383 ;
     RECT  45.6 45.369 45.72 45.383 ;
     RECT  48.3 45.369 48.42 45.383 ;
  END
END qkd_landsh_296
END LIBRARY
